VERSION 5.8 ;
BUSBITCHARS "[]" ;
DIVIDERCHAR "/" ;
UNITS
    DATABASE MICRONS 1000 ;
END UNITS

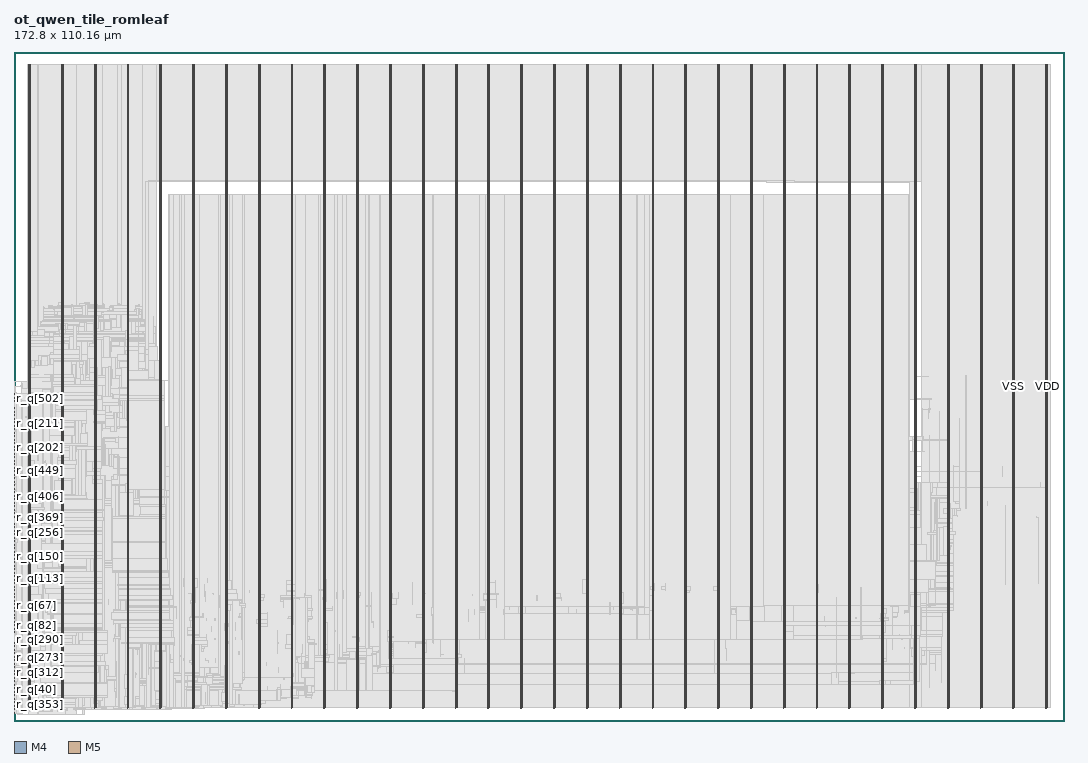
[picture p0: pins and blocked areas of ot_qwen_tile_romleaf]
MACRO ot_qwen_tile_romleaf
  FOREIGN ot_qwen_tile_romleaf 0 0 ;
  CLASS BLOCK ;
  SIZE 172.8 BY 110.16 ;
  PIN ad_d[0]
    DIRECTION INPUT ;
    USE SIGNAL ;
    PORT
      LAYER M4 ;
        RECT  0 20.4 0.084 20.424 ;
    END
  END ad_d[0]
  PIN ad_d[10]
    DIRECTION INPUT ;
    USE SIGNAL ;
    PORT
      LAYER M4 ;
        RECT  0 21.36 0.084 21.384 ;
    END
  END ad_d[10]
  PIN ad_d[11]
    DIRECTION INPUT ;
    USE SIGNAL ;
    PORT
      LAYER M4 ;
        RECT  0 21.456 0.084 21.48 ;
    END
  END ad_d[11]
  PIN ad_d[1]
    DIRECTION INPUT ;
    USE SIGNAL ;
    PORT
      LAYER M4 ;
        RECT  0 20.496 0.084 20.52 ;
    END
  END ad_d[1]
  PIN ad_d[2]
    DIRECTION INPUT ;
    USE SIGNAL ;
    PORT
      LAYER M4 ;
        RECT  0 20.592 0.084 20.616 ;
    END
  END ad_d[2]
  PIN ad_d[3]
    DIRECTION INPUT ;
    USE SIGNAL ;
    PORT
      LAYER M4 ;
        RECT  0 20.688 0.084 20.712 ;
    END
  END ad_d[3]
  PIN ad_d[4]
    DIRECTION INPUT ;
    USE SIGNAL ;
    PORT
      LAYER M4 ;
        RECT  0 20.784 0.084 20.808 ;
    END
  END ad_d[4]
  PIN ad_d[5]
    DIRECTION INPUT ;
    USE SIGNAL ;
    PORT
      LAYER M4 ;
        RECT  0 20.88 0.084 20.904 ;
    END
  END ad_d[5]
  PIN ad_d[6]
    DIRECTION INPUT ;
    USE SIGNAL ;
    PORT
      LAYER M4 ;
        RECT  0 20.976 0.084 21 ;
    END
  END ad_d[6]
  PIN ad_d[7]
    DIRECTION INPUT ;
    USE SIGNAL ;
    PORT
      LAYER M4 ;
        RECT  0 21.072 0.084 21.096 ;
    END
  END ad_d[7]
  PIN ad_d[8]
    DIRECTION INPUT ;
    USE SIGNAL ;
    PORT
      LAYER M4 ;
        RECT  0 21.168 0.084 21.192 ;
    END
  END ad_d[8]
  PIN ad_d[9]
    DIRECTION INPUT ;
    USE SIGNAL ;
    PORT
      LAYER M4 ;
        RECT  0 21.264 0.084 21.288 ;
    END
  END ad_d[9]
  PIN any_d
    DIRECTION INPUT ;
    USE SIGNAL ;
    PORT
      LAYER M4 ;
        RECT  0 21.552 0.084 21.576 ;
    END
  END any_d
  PIN ce_d
    DIRECTION INPUT ;
    USE SIGNAL ;
    PORT
      LAYER M4 ;
        RECT  0 21.648 0.084 21.672 ;
    END
  END ce_d
  PIN clk
    DIRECTION INPUT ;
    USE SIGNAL ;
    PORT
      LAYER M4 ;
        RECT  0 21.744 0.084 21.768 ;
    END
  END clk
  PIN r_q[0]
    DIRECTION OUTPUT ;
    USE SIGNAL ;
    PORT
      LAYER M4 ;
        RECT  0 21.84 0.084 21.864 ;
    END
  END r_q[0]
  PIN r_q[100]
    DIRECTION OUTPUT ;
    USE SIGNAL ;
    PORT
      LAYER M4 ;
        RECT  0 16.08 0.084 16.104 ;
    END
  END r_q[100]
  PIN r_q[101]
    DIRECTION OUTPUT ;
    USE SIGNAL ;
    PORT
      LAYER M4 ;
        RECT  0 16.176 0.084 16.2 ;
    END
  END r_q[101]
  PIN r_q[102]
    DIRECTION OUTPUT ;
    USE SIGNAL ;
    PORT
      LAYER M4 ;
        RECT  0 16.272 0.084 16.296 ;
    END
  END r_q[102]
  PIN r_q[103]
    DIRECTION OUTPUT ;
    USE SIGNAL ;
    PORT
      LAYER M4 ;
        RECT  0 16.368 0.084 16.392 ;
    END
  END r_q[103]
  PIN r_q[104]
    DIRECTION OUTPUT ;
    USE SIGNAL ;
    PORT
      LAYER M4 ;
        RECT  0 16.464 0.084 16.488 ;
    END
  END r_q[104]
  PIN r_q[105]
    DIRECTION OUTPUT ;
    USE SIGNAL ;
    PORT
      LAYER M4 ;
        RECT  0 16.56 0.084 16.584 ;
    END
  END r_q[105]
  PIN r_q[106]
    DIRECTION OUTPUT ;
    USE SIGNAL ;
    PORT
      LAYER M4 ;
        RECT  0 16.656 0.084 16.68 ;
    END
  END r_q[106]
  PIN r_q[107]
    DIRECTION OUTPUT ;
    USE SIGNAL ;
    PORT
      LAYER M4 ;
        RECT  0 16.752 0.084 16.776 ;
    END
  END r_q[107]
  PIN r_q[108]
    DIRECTION OUTPUT ;
    USE SIGNAL ;
    PORT
      LAYER M4 ;
        RECT  0 16.848 0.084 16.872 ;
    END
  END r_q[108]
  PIN r_q[109]
    DIRECTION OUTPUT ;
    USE SIGNAL ;
    PORT
      LAYER M4 ;
        RECT  0 16.944 0.084 16.968 ;
    END
  END r_q[109]
  PIN r_q[10]
    DIRECTION OUTPUT ;
    USE SIGNAL ;
    PORT
      LAYER M4 ;
        RECT  0 22.8 0.084 22.824 ;
    END
  END r_q[10]
  PIN r_q[110]
    DIRECTION OUTPUT ;
    USE SIGNAL ;
    PORT
      LAYER M4 ;
        RECT  0 17.04 0.084 17.064 ;
    END
  END r_q[110]
  PIN r_q[111]
    DIRECTION OUTPUT ;
    USE SIGNAL ;
    PORT
      LAYER M4 ;
        RECT  0 17.136 0.084 17.16 ;
    END
  END r_q[111]
  PIN r_q[112]
    DIRECTION OUTPUT ;
    USE SIGNAL ;
    PORT
      LAYER M4 ;
        RECT  0 17.232 0.084 17.256 ;
    END
  END r_q[112]
  PIN r_q[113]
    DIRECTION OUTPUT ;
    USE SIGNAL ;
    PORT
      LAYER M4 ;
        RECT  0 23.472 0.084 23.496 ;
    END
  END r_q[113]
  PIN r_q[114]
    DIRECTION OUTPUT ;
    USE SIGNAL ;
    PORT
      LAYER M4 ;
        RECT  0 23.568 0.084 23.592 ;
    END
  END r_q[114]
  PIN r_q[115]
    DIRECTION OUTPUT ;
    USE SIGNAL ;
    PORT
      LAYER M4 ;
        RECT  0 23.664 0.084 23.688 ;
    END
  END r_q[115]
  PIN r_q[116]
    DIRECTION OUTPUT ;
    USE SIGNAL ;
    PORT
      LAYER M4 ;
        RECT  0 23.76 0.084 23.784 ;
    END
  END r_q[116]
  PIN r_q[117]
    DIRECTION OUTPUT ;
    USE SIGNAL ;
    PORT
      LAYER M4 ;
        RECT  0 23.856 0.084 23.88 ;
    END
  END r_q[117]
  PIN r_q[118]
    DIRECTION OUTPUT ;
    USE SIGNAL ;
    PORT
      LAYER M4 ;
        RECT  0 23.952 0.084 23.976 ;
    END
  END r_q[118]
  PIN r_q[119]
    DIRECTION OUTPUT ;
    USE SIGNAL ;
    PORT
      LAYER M4 ;
        RECT  0 24.048 0.084 24.072 ;
    END
  END r_q[119]
  PIN r_q[11]
    DIRECTION OUTPUT ;
    USE SIGNAL ;
    PORT
      LAYER M4 ;
        RECT  0 22.896 0.084 22.92 ;
    END
  END r_q[11]
  PIN r_q[120]
    DIRECTION OUTPUT ;
    USE SIGNAL ;
    PORT
      LAYER M4 ;
        RECT  0 24.144 0.084 24.168 ;
    END
  END r_q[120]
  PIN r_q[121]
    DIRECTION OUTPUT ;
    USE SIGNAL ;
    PORT
      LAYER M4 ;
        RECT  0 24.24 0.084 24.264 ;
    END
  END r_q[121]
  PIN r_q[122]
    DIRECTION OUTPUT ;
    USE SIGNAL ;
    PORT
      LAYER M4 ;
        RECT  0 24.336 0.084 24.36 ;
    END
  END r_q[122]
  PIN r_q[123]
    DIRECTION OUTPUT ;
    USE SIGNAL ;
    PORT
      LAYER M4 ;
        RECT  0 24.432 0.084 24.456 ;
    END
  END r_q[123]
  PIN r_q[124]
    DIRECTION OUTPUT ;
    USE SIGNAL ;
    PORT
      LAYER M4 ;
        RECT  0 24.528 0.084 24.552 ;
    END
  END r_q[124]
  PIN r_q[125]
    DIRECTION OUTPUT ;
    USE SIGNAL ;
    PORT
      LAYER M4 ;
        RECT  0 24.624 0.084 24.648 ;
    END
  END r_q[125]
  PIN r_q[126]
    DIRECTION OUTPUT ;
    USE SIGNAL ;
    PORT
      LAYER M4 ;
        RECT  0 24.72 0.084 24.744 ;
    END
  END r_q[126]
  PIN r_q[127]
    DIRECTION OUTPUT ;
    USE SIGNAL ;
    PORT
      LAYER M4 ;
        RECT  0 24.816 0.084 24.84 ;
    END
  END r_q[127]
  PIN r_q[128]
    DIRECTION OUTPUT ;
    USE SIGNAL ;
    PORT
      LAYER M4 ;
        RECT  0 24.912 0.084 24.936 ;
    END
  END r_q[128]
  PIN r_q[129]
    DIRECTION OUTPUT ;
    USE SIGNAL ;
    PORT
      LAYER M4 ;
        RECT  0 25.008 0.084 25.032 ;
    END
  END r_q[129]
  PIN r_q[12]
    DIRECTION OUTPUT ;
    USE SIGNAL ;
    PORT
      LAYER M4 ;
        RECT  0 22.992 0.084 23.016 ;
    END
  END r_q[12]
  PIN r_q[130]
    DIRECTION OUTPUT ;
    USE SIGNAL ;
    PORT
      LAYER M4 ;
        RECT  0 25.104 0.084 25.128 ;
    END
  END r_q[130]
  PIN r_q[131]
    DIRECTION OUTPUT ;
    USE SIGNAL ;
    PORT
      LAYER M4 ;
        RECT  0 25.2 0.084 25.224 ;
    END
  END r_q[131]
  PIN r_q[132]
    DIRECTION OUTPUT ;
    USE SIGNAL ;
    PORT
      LAYER M4 ;
        RECT  0 25.296 0.084 25.32 ;
    END
  END r_q[132]
  PIN r_q[133]
    DIRECTION OUTPUT ;
    USE SIGNAL ;
    PORT
      LAYER M4 ;
        RECT  0 25.392 0.084 25.416 ;
    END
  END r_q[133]
  PIN r_q[134]
    DIRECTION OUTPUT ;
    USE SIGNAL ;
    PORT
      LAYER M4 ;
        RECT  0 25.488 0.084 25.512 ;
    END
  END r_q[134]
  PIN r_q[135]
    DIRECTION OUTPUT ;
    USE SIGNAL ;
    PORT
      LAYER M4 ;
        RECT  0 25.584 0.084 25.608 ;
    END
  END r_q[135]
  PIN r_q[136]
    DIRECTION OUTPUT ;
    USE SIGNAL ;
    PORT
      LAYER M4 ;
        RECT  0 25.68 0.084 25.704 ;
    END
  END r_q[136]
  PIN r_q[137]
    DIRECTION OUTPUT ;
    USE SIGNAL ;
    PORT
      LAYER M4 ;
        RECT  0 25.776 0.084 25.8 ;
    END
  END r_q[137]
  PIN r_q[138]
    DIRECTION OUTPUT ;
    USE SIGNAL ;
    PORT
      LAYER M4 ;
        RECT  0 25.872 0.084 25.896 ;
    END
  END r_q[138]
  PIN r_q[139]
    DIRECTION OUTPUT ;
    USE SIGNAL ;
    PORT
      LAYER M4 ;
        RECT  0 25.968 0.084 25.992 ;
    END
  END r_q[139]
  PIN r_q[13]
    DIRECTION OUTPUT ;
    USE SIGNAL ;
    PORT
      LAYER M4 ;
        RECT  0 23.088 0.084 23.112 ;
    END
  END r_q[13]
  PIN r_q[140]
    DIRECTION OUTPUT ;
    USE SIGNAL ;
    PORT
      LAYER M4 ;
        RECT  0 26.064 0.084 26.088 ;
    END
  END r_q[140]
  PIN r_q[141]
    DIRECTION OUTPUT ;
    USE SIGNAL ;
    PORT
      LAYER M4 ;
        RECT  0 26.16 0.084 26.184 ;
    END
  END r_q[141]
  PIN r_q[142]
    DIRECTION OUTPUT ;
    USE SIGNAL ;
    PORT
      LAYER M4 ;
        RECT  0 26.256 0.084 26.28 ;
    END
  END r_q[142]
  PIN r_q[143]
    DIRECTION OUTPUT ;
    USE SIGNAL ;
    PORT
      LAYER M4 ;
        RECT  0 26.352 0.084 26.376 ;
    END
  END r_q[143]
  PIN r_q[144]
    DIRECTION OUTPUT ;
    USE SIGNAL ;
    PORT
      LAYER M4 ;
        RECT  0 26.448 0.084 26.472 ;
    END
  END r_q[144]
  PIN r_q[145]
    DIRECTION OUTPUT ;
    USE SIGNAL ;
    PORT
      LAYER M4 ;
        RECT  0 26.544 0.084 26.568 ;
    END
  END r_q[145]
  PIN r_q[146]
    DIRECTION OUTPUT ;
    USE SIGNAL ;
    PORT
      LAYER M4 ;
        RECT  0 26.64 0.084 26.664 ;
    END
  END r_q[146]
  PIN r_q[147]
    DIRECTION OUTPUT ;
    USE SIGNAL ;
    PORT
      LAYER M4 ;
        RECT  0 26.736 0.084 26.76 ;
    END
  END r_q[147]
  PIN r_q[148]
    DIRECTION OUTPUT ;
    USE SIGNAL ;
    PORT
      LAYER M4 ;
        RECT  0 26.832 0.084 26.856 ;
    END
  END r_q[148]
  PIN r_q[149]
    DIRECTION OUTPUT ;
    USE SIGNAL ;
    PORT
      LAYER M4 ;
        RECT  0 26.928 0.084 26.952 ;
    END
  END r_q[149]
  PIN r_q[14]
    DIRECTION OUTPUT ;
    USE SIGNAL ;
    PORT
      LAYER M4 ;
        RECT  0 23.184 0.084 23.208 ;
    END
  END r_q[14]
  PIN r_q[150]
    DIRECTION OUTPUT ;
    USE SIGNAL ;
    PORT
      LAYER M4 ;
        RECT  0 27.024 0.084 27.048 ;
    END
  END r_q[150]
  PIN r_q[151]
    DIRECTION OUTPUT ;
    USE SIGNAL ;
    PORT
      LAYER M4 ;
        RECT  0 27.12 0.084 27.144 ;
    END
  END r_q[151]
  PIN r_q[152]
    DIRECTION OUTPUT ;
    USE SIGNAL ;
    PORT
      LAYER M4 ;
        RECT  0 27.216 0.084 27.24 ;
    END
  END r_q[152]
  PIN r_q[153]
    DIRECTION OUTPUT ;
    USE SIGNAL ;
    PORT
      LAYER M4 ;
        RECT  0 27.312 0.084 27.336 ;
    END
  END r_q[153]
  PIN r_q[154]
    DIRECTION OUTPUT ;
    USE SIGNAL ;
    PORT
      LAYER M4 ;
        RECT  0 27.408 0.084 27.432 ;
    END
  END r_q[154]
  PIN r_q[155]
    DIRECTION OUTPUT ;
    USE SIGNAL ;
    PORT
      LAYER M4 ;
        RECT  0 27.504 0.084 27.528 ;
    END
  END r_q[155]
  PIN r_q[156]
    DIRECTION OUTPUT ;
    USE SIGNAL ;
    PORT
      LAYER M4 ;
        RECT  0 27.6 0.084 27.624 ;
    END
  END r_q[156]
  PIN r_q[157]
    DIRECTION OUTPUT ;
    USE SIGNAL ;
    PORT
      LAYER M4 ;
        RECT  0 27.696 0.084 27.72 ;
    END
  END r_q[157]
  PIN r_q[158]
    DIRECTION OUTPUT ;
    USE SIGNAL ;
    PORT
      LAYER M4 ;
        RECT  0 27.792 0.084 27.816 ;
    END
  END r_q[158]
  PIN r_q[159]
    DIRECTION OUTPUT ;
    USE SIGNAL ;
    PORT
      LAYER M4 ;
        RECT  0 27.888 0.084 27.912 ;
    END
  END r_q[159]
  PIN r_q[15]
    DIRECTION OUTPUT ;
    USE SIGNAL ;
    PORT
      LAYER M4 ;
        RECT  0 23.28 0.084 23.304 ;
    END
  END r_q[15]
  PIN r_q[160]
    DIRECTION OUTPUT ;
    USE SIGNAL ;
    PORT
      LAYER M4 ;
        RECT  0 27.984 0.084 28.008 ;
    END
  END r_q[160]
  PIN r_q[161]
    DIRECTION OUTPUT ;
    USE SIGNAL ;
    PORT
      LAYER M4 ;
        RECT  0 28.08 0.084 28.104 ;
    END
  END r_q[161]
  PIN r_q[162]
    DIRECTION OUTPUT ;
    USE SIGNAL ;
    PORT
      LAYER M4 ;
        RECT  0 28.176 0.084 28.2 ;
    END
  END r_q[162]
  PIN r_q[163]
    DIRECTION OUTPUT ;
    USE SIGNAL ;
    PORT
      LAYER M4 ;
        RECT  0 28.272 0.084 28.296 ;
    END
  END r_q[163]
  PIN r_q[164]
    DIRECTION OUTPUT ;
    USE SIGNAL ;
    PORT
      LAYER M4 ;
        RECT  0 28.368 0.084 28.392 ;
    END
  END r_q[164]
  PIN r_q[165]
    DIRECTION OUTPUT ;
    USE SIGNAL ;
    PORT
      LAYER M4 ;
        RECT  0 28.464 0.084 28.488 ;
    END
  END r_q[165]
  PIN r_q[166]
    DIRECTION OUTPUT ;
    USE SIGNAL ;
    PORT
      LAYER M4 ;
        RECT  0 28.56 0.084 28.584 ;
    END
  END r_q[166]
  PIN r_q[167]
    DIRECTION OUTPUT ;
    USE SIGNAL ;
    PORT
      LAYER M4 ;
        RECT  0 28.656 0.084 28.68 ;
    END
  END r_q[167]
  PIN r_q[168]
    DIRECTION OUTPUT ;
    USE SIGNAL ;
    PORT
      LAYER M4 ;
        RECT  0 28.752 0.084 28.776 ;
    END
  END r_q[168]
  PIN r_q[169]
    DIRECTION OUTPUT ;
    USE SIGNAL ;
    PORT
      LAYER M4 ;
        RECT  0 28.848 0.084 28.872 ;
    END
  END r_q[169]
  PIN r_q[16]
    DIRECTION OUTPUT ;
    USE SIGNAL ;
    PORT
      LAYER M4 ;
        RECT  0 23.376 0.084 23.4 ;
    END
  END r_q[16]
  PIN r_q[170]
    DIRECTION OUTPUT ;
    USE SIGNAL ;
    PORT
      LAYER M4 ;
        RECT  0 28.944 0.084 28.968 ;
    END
  END r_q[170]
  PIN r_q[171]
    DIRECTION OUTPUT ;
    USE SIGNAL ;
    PORT
      LAYER M4 ;
        RECT  0 29.04 0.084 29.064 ;
    END
  END r_q[171]
  PIN r_q[172]
    DIRECTION OUTPUT ;
    USE SIGNAL ;
    PORT
      LAYER M4 ;
        RECT  0 29.136 0.084 29.16 ;
    END
  END r_q[172]
  PIN r_q[173]
    DIRECTION OUTPUT ;
    USE SIGNAL ;
    PORT
      LAYER M4 ;
        RECT  0 29.232 0.084 29.256 ;
    END
  END r_q[173]
  PIN r_q[174]
    DIRECTION OUTPUT ;
    USE SIGNAL ;
    PORT
      LAYER M4 ;
        RECT  0 29.328 0.084 29.352 ;
    END
  END r_q[174]
  PIN r_q[175]
    DIRECTION OUTPUT ;
    USE SIGNAL ;
    PORT
      LAYER M4 ;
        RECT  0 29.424 0.084 29.448 ;
    END
  END r_q[175]
  PIN r_q[176]
    DIRECTION OUTPUT ;
    USE SIGNAL ;
    PORT
      LAYER M4 ;
        RECT  0 29.52 0.084 29.544 ;
    END
  END r_q[176]
  PIN r_q[177]
    DIRECTION OUTPUT ;
    USE SIGNAL ;
    PORT
      LAYER M4 ;
        RECT  0 42.672 0.084 42.696 ;
    END
  END r_q[177]
  PIN r_q[178]
    DIRECTION OUTPUT ;
    USE SIGNAL ;
    PORT
      LAYER M4 ;
        RECT  0 42.768 0.084 42.792 ;
    END
  END r_q[178]
  PIN r_q[179]
    DIRECTION OUTPUT ;
    USE SIGNAL ;
    PORT
      LAYER M4 ;
        RECT  0 42.864 0.084 42.888 ;
    END
  END r_q[179]
  PIN r_q[17]
    DIRECTION OUTPUT ;
    USE SIGNAL ;
    PORT
      LAYER M4 ;
        RECT  0 4.272 0.084 4.296 ;
    END
  END r_q[17]
  PIN r_q[180]
    DIRECTION OUTPUT ;
    USE SIGNAL ;
    PORT
      LAYER M4 ;
        RECT  0 42.96 0.084 42.984 ;
    END
  END r_q[180]
  PIN r_q[181]
    DIRECTION OUTPUT ;
    USE SIGNAL ;
    PORT
      LAYER M4 ;
        RECT  0 43.056 0.084 43.08 ;
    END
  END r_q[181]
  PIN r_q[182]
    DIRECTION OUTPUT ;
    USE SIGNAL ;
    PORT
      LAYER M4 ;
        RECT  0 43.152 0.084 43.176 ;
    END
  END r_q[182]
  PIN r_q[183]
    DIRECTION OUTPUT ;
    USE SIGNAL ;
    PORT
      LAYER M4 ;
        RECT  0 43.248 0.084 43.272 ;
    END
  END r_q[183]
  PIN r_q[184]
    DIRECTION OUTPUT ;
    USE SIGNAL ;
    PORT
      LAYER M4 ;
        RECT  0 43.344 0.084 43.368 ;
    END
  END r_q[184]
  PIN r_q[185]
    DIRECTION OUTPUT ;
    USE SIGNAL ;
    PORT
      LAYER M4 ;
        RECT  0 43.44 0.084 43.464 ;
    END
  END r_q[185]
  PIN r_q[186]
    DIRECTION OUTPUT ;
    USE SIGNAL ;
    PORT
      LAYER M4 ;
        RECT  0 43.536 0.084 43.56 ;
    END
  END r_q[186]
  PIN r_q[187]
    DIRECTION OUTPUT ;
    USE SIGNAL ;
    PORT
      LAYER M4 ;
        RECT  0 43.632 0.084 43.656 ;
    END
  END r_q[187]
  PIN r_q[188]
    DIRECTION OUTPUT ;
    USE SIGNAL ;
    PORT
      LAYER M4 ;
        RECT  0 43.728 0.084 43.752 ;
    END
  END r_q[188]
  PIN r_q[189]
    DIRECTION OUTPUT ;
    USE SIGNAL ;
    PORT
      LAYER M4 ;
        RECT  0 43.824 0.084 43.848 ;
    END
  END r_q[189]
  PIN r_q[18]
    DIRECTION OUTPUT ;
    USE SIGNAL ;
    PORT
      LAYER M4 ;
        RECT  0 4.368 0.084 4.392 ;
    END
  END r_q[18]
  PIN r_q[190]
    DIRECTION OUTPUT ;
    USE SIGNAL ;
    PORT
      LAYER M4 ;
        RECT  0 43.92 0.084 43.944 ;
    END
  END r_q[190]
  PIN r_q[191]
    DIRECTION OUTPUT ;
    USE SIGNAL ;
    PORT
      LAYER M4 ;
        RECT  0 44.016 0.084 44.04 ;
    END
  END r_q[191]
  PIN r_q[192]
    DIRECTION OUTPUT ;
    USE SIGNAL ;
    PORT
      LAYER M4 ;
        RECT  0 44.112 0.084 44.136 ;
    END
  END r_q[192]
  PIN r_q[193]
    DIRECTION OUTPUT ;
    USE SIGNAL ;
    PORT
      LAYER M4 ;
        RECT  0 44.208 0.084 44.232 ;
    END
  END r_q[193]
  PIN r_q[194]
    DIRECTION OUTPUT ;
    USE SIGNAL ;
    PORT
      LAYER M4 ;
        RECT  0 44.304 0.084 44.328 ;
    END
  END r_q[194]
  PIN r_q[195]
    DIRECTION OUTPUT ;
    USE SIGNAL ;
    PORT
      LAYER M4 ;
        RECT  0 44.4 0.084 44.424 ;
    END
  END r_q[195]
  PIN r_q[196]
    DIRECTION OUTPUT ;
    USE SIGNAL ;
    PORT
      LAYER M4 ;
        RECT  0 44.496 0.084 44.52 ;
    END
  END r_q[196]
  PIN r_q[197]
    DIRECTION OUTPUT ;
    USE SIGNAL ;
    PORT
      LAYER M4 ;
        RECT  0 44.592 0.084 44.616 ;
    END
  END r_q[197]
  PIN r_q[198]
    DIRECTION OUTPUT ;
    USE SIGNAL ;
    PORT
      LAYER M4 ;
        RECT  0 44.688 0.084 44.712 ;
    END
  END r_q[198]
  PIN r_q[199]
    DIRECTION OUTPUT ;
    USE SIGNAL ;
    PORT
      LAYER M4 ;
        RECT  0 44.784 0.084 44.808 ;
    END
  END r_q[199]
  PIN r_q[19]
    DIRECTION OUTPUT ;
    USE SIGNAL ;
    PORT
      LAYER M4 ;
        RECT  0 4.464 0.084 4.488 ;
    END
  END r_q[19]
  PIN r_q[1]
    DIRECTION OUTPUT ;
    USE SIGNAL ;
    PORT
      LAYER M4 ;
        RECT  0 21.936 0.084 21.96 ;
    END
  END r_q[1]
  PIN r_q[200]
    DIRECTION OUTPUT ;
    USE SIGNAL ;
    PORT
      LAYER M4 ;
        RECT  0 44.88 0.084 44.904 ;
    END
  END r_q[200]
  PIN r_q[201]
    DIRECTION OUTPUT ;
    USE SIGNAL ;
    PORT
      LAYER M4 ;
        RECT  0 44.976 0.084 45 ;
    END
  END r_q[201]
  PIN r_q[202]
    DIRECTION OUTPUT ;
    USE SIGNAL ;
    PORT
      LAYER M4 ;
        RECT  0 45.072 0.084 45.096 ;
    END
  END r_q[202]
  PIN r_q[203]
    DIRECTION OUTPUT ;
    USE SIGNAL ;
    PORT
      LAYER M4 ;
        RECT  0 45.168 0.084 45.192 ;
    END
  END r_q[203]
  PIN r_q[204]
    DIRECTION OUTPUT ;
    USE SIGNAL ;
    PORT
      LAYER M4 ;
        RECT  0 45.264 0.084 45.288 ;
    END
  END r_q[204]
  PIN r_q[205]
    DIRECTION OUTPUT ;
    USE SIGNAL ;
    PORT
      LAYER M4 ;
        RECT  0 45.36 0.084 45.384 ;
    END
  END r_q[205]
  PIN r_q[206]
    DIRECTION OUTPUT ;
    USE SIGNAL ;
    PORT
      LAYER M4 ;
        RECT  0 45.456 0.084 45.48 ;
    END
  END r_q[206]
  PIN r_q[207]
    DIRECTION OUTPUT ;
    USE SIGNAL ;
    PORT
      LAYER M4 ;
        RECT  0 45.552 0.084 45.576 ;
    END
  END r_q[207]
  PIN r_q[208]
    DIRECTION OUTPUT ;
    USE SIGNAL ;
    PORT
      LAYER M4 ;
        RECT  0 45.648 0.084 45.672 ;
    END
  END r_q[208]
  PIN r_q[209]
    DIRECTION OUTPUT ;
    USE SIGNAL ;
    PORT
      LAYER M4 ;
        RECT  0 48.816 0.084 48.84 ;
    END
  END r_q[209]
  PIN r_q[20]
    DIRECTION OUTPUT ;
    USE SIGNAL ;
    PORT
      LAYER M4 ;
        RECT  0 4.56 0.084 4.584 ;
    END
  END r_q[20]
  PIN r_q[210]
    DIRECTION OUTPUT ;
    USE SIGNAL ;
    PORT
      LAYER M4 ;
        RECT  0 48.912 0.084 48.936 ;
    END
  END r_q[210]
  PIN r_q[211]
    DIRECTION OUTPUT ;
    USE SIGNAL ;
    PORT
      LAYER M4 ;
        RECT  0 49.008 0.084 49.032 ;
    END
  END r_q[211]
  PIN r_q[212]
    DIRECTION OUTPUT ;
    USE SIGNAL ;
    PORT
      LAYER M4 ;
        RECT  0 49.104 0.084 49.128 ;
    END
  END r_q[212]
  PIN r_q[213]
    DIRECTION OUTPUT ;
    USE SIGNAL ;
    PORT
      LAYER M4 ;
        RECT  0 49.2 0.084 49.224 ;
    END
  END r_q[213]
  PIN r_q[214]
    DIRECTION OUTPUT ;
    USE SIGNAL ;
    PORT
      LAYER M4 ;
        RECT  0 49.296 0.084 49.32 ;
    END
  END r_q[214]
  PIN r_q[215]
    DIRECTION OUTPUT ;
    USE SIGNAL ;
    PORT
      LAYER M4 ;
        RECT  0 49.392 0.084 49.416 ;
    END
  END r_q[215]
  PIN r_q[216]
    DIRECTION OUTPUT ;
    USE SIGNAL ;
    PORT
      LAYER M4 ;
        RECT  0 49.488 0.084 49.512 ;
    END
  END r_q[216]
  PIN r_q[217]
    DIRECTION OUTPUT ;
    USE SIGNAL ;
    PORT
      LAYER M4 ;
        RECT  0 49.584 0.084 49.608 ;
    END
  END r_q[217]
  PIN r_q[218]
    DIRECTION OUTPUT ;
    USE SIGNAL ;
    PORT
      LAYER M4 ;
        RECT  0 49.68 0.084 49.704 ;
    END
  END r_q[218]
  PIN r_q[219]
    DIRECTION OUTPUT ;
    USE SIGNAL ;
    PORT
      LAYER M4 ;
        RECT  0 49.776 0.084 49.8 ;
    END
  END r_q[219]
  PIN r_q[21]
    DIRECTION OUTPUT ;
    USE SIGNAL ;
    PORT
      LAYER M4 ;
        RECT  0 4.656 0.084 4.68 ;
    END
  END r_q[21]
  PIN r_q[220]
    DIRECTION OUTPUT ;
    USE SIGNAL ;
    PORT
      LAYER M4 ;
        RECT  0 49.872 0.084 49.896 ;
    END
  END r_q[220]
  PIN r_q[221]
    DIRECTION OUTPUT ;
    USE SIGNAL ;
    PORT
      LAYER M4 ;
        RECT  0 49.968 0.084 49.992 ;
    END
  END r_q[221]
  PIN r_q[222]
    DIRECTION OUTPUT ;
    USE SIGNAL ;
    PORT
      LAYER M4 ;
        RECT  0 50.064 0.084 50.088 ;
    END
  END r_q[222]
  PIN r_q[223]
    DIRECTION OUTPUT ;
    USE SIGNAL ;
    PORT
      LAYER M4 ;
        RECT  0 50.16 0.084 50.184 ;
    END
  END r_q[223]
  PIN r_q[224]
    DIRECTION OUTPUT ;
    USE SIGNAL ;
    PORT
      LAYER M4 ;
        RECT  0 50.256 0.084 50.28 ;
    END
  END r_q[224]
  PIN r_q[225]
    DIRECTION OUTPUT ;
    USE SIGNAL ;
    PORT
      LAYER M4 ;
        RECT  0 50.352 0.084 50.376 ;
    END
  END r_q[225]
  PIN r_q[226]
    DIRECTION OUTPUT ;
    USE SIGNAL ;
    PORT
      LAYER M4 ;
        RECT  0 50.448 0.084 50.472 ;
    END
  END r_q[226]
  PIN r_q[227]
    DIRECTION OUTPUT ;
    USE SIGNAL ;
    PORT
      LAYER M4 ;
        RECT  0 50.544 0.084 50.568 ;
    END
  END r_q[227]
  PIN r_q[228]
    DIRECTION OUTPUT ;
    USE SIGNAL ;
    PORT
      LAYER M4 ;
        RECT  0 50.64 0.084 50.664 ;
    END
  END r_q[228]
  PIN r_q[229]
    DIRECTION OUTPUT ;
    USE SIGNAL ;
    PORT
      LAYER M4 ;
        RECT  0 50.736 0.084 50.76 ;
    END
  END r_q[229]
  PIN r_q[22]
    DIRECTION OUTPUT ;
    USE SIGNAL ;
    PORT
      LAYER M4 ;
        RECT  0 4.752 0.084 4.776 ;
    END
  END r_q[22]
  PIN r_q[230]
    DIRECTION OUTPUT ;
    USE SIGNAL ;
    PORT
      LAYER M4 ;
        RECT  0 50.832 0.084 50.856 ;
    END
  END r_q[230]
  PIN r_q[231]
    DIRECTION OUTPUT ;
    USE SIGNAL ;
    PORT
      LAYER M4 ;
        RECT  0 50.928 0.084 50.952 ;
    END
  END r_q[231]
  PIN r_q[232]
    DIRECTION OUTPUT ;
    USE SIGNAL ;
    PORT
      LAYER M4 ;
        RECT  0 51.024 0.084 51.048 ;
    END
  END r_q[232]
  PIN r_q[233]
    DIRECTION OUTPUT ;
    USE SIGNAL ;
    PORT
      LAYER M4 ;
        RECT  0 51.12 0.084 51.144 ;
    END
  END r_q[233]
  PIN r_q[234]
    DIRECTION OUTPUT ;
    USE SIGNAL ;
    PORT
      LAYER M4 ;
        RECT  0 51.216 0.084 51.24 ;
    END
  END r_q[234]
  PIN r_q[235]
    DIRECTION OUTPUT ;
    USE SIGNAL ;
    PORT
      LAYER M4 ;
        RECT  0 51.312 0.084 51.336 ;
    END
  END r_q[235]
  PIN r_q[236]
    DIRECTION OUTPUT ;
    USE SIGNAL ;
    PORT
      LAYER M4 ;
        RECT  0 51.408 0.084 51.432 ;
    END
  END r_q[236]
  PIN r_q[237]
    DIRECTION OUTPUT ;
    USE SIGNAL ;
    PORT
      LAYER M4 ;
        RECT  0 51.504 0.084 51.528 ;
    END
  END r_q[237]
  PIN r_q[238]
    DIRECTION OUTPUT ;
    USE SIGNAL ;
    PORT
      LAYER M4 ;
        RECT  0 51.6 0.084 51.624 ;
    END
  END r_q[238]
  PIN r_q[239]
    DIRECTION OUTPUT ;
    USE SIGNAL ;
    PORT
      LAYER M4 ;
        RECT  0 51.696 0.084 51.72 ;
    END
  END r_q[239]
  PIN r_q[23]
    DIRECTION OUTPUT ;
    USE SIGNAL ;
    PORT
      LAYER M4 ;
        RECT  0 4.848 0.084 4.872 ;
    END
  END r_q[23]
  PIN r_q[240]
    DIRECTION OUTPUT ;
    USE SIGNAL ;
    PORT
      LAYER M4 ;
        RECT  0 51.792 0.084 51.816 ;
    END
  END r_q[240]
  PIN r_q[241]
    DIRECTION OUTPUT ;
    USE SIGNAL ;
    PORT
      LAYER M4 ;
        RECT  0 29.616 0.084 29.64 ;
    END
  END r_q[241]
  PIN r_q[242]
    DIRECTION OUTPUT ;
    USE SIGNAL ;
    PORT
      LAYER M4 ;
        RECT  0 29.712 0.084 29.736 ;
    END
  END r_q[242]
  PIN r_q[243]
    DIRECTION OUTPUT ;
    USE SIGNAL ;
    PORT
      LAYER M4 ;
        RECT  0 29.808 0.084 29.832 ;
    END
  END r_q[243]
  PIN r_q[244]
    DIRECTION OUTPUT ;
    USE SIGNAL ;
    PORT
      LAYER M4 ;
        RECT  0 29.904 0.084 29.928 ;
    END
  END r_q[244]
  PIN r_q[245]
    DIRECTION OUTPUT ;
    USE SIGNAL ;
    PORT
      LAYER M4 ;
        RECT  0 30 0.084 30.024 ;
    END
  END r_q[245]
  PIN r_q[246]
    DIRECTION OUTPUT ;
    USE SIGNAL ;
    PORT
      LAYER M4 ;
        RECT  0 30.096 0.084 30.12 ;
    END
  END r_q[246]
  PIN r_q[247]
    DIRECTION OUTPUT ;
    USE SIGNAL ;
    PORT
      LAYER M4 ;
        RECT  0 30.192 0.084 30.216 ;
    END
  END r_q[247]
  PIN r_q[248]
    DIRECTION OUTPUT ;
    USE SIGNAL ;
    PORT
      LAYER M4 ;
        RECT  0 30.288 0.084 30.312 ;
    END
  END r_q[248]
  PIN r_q[249]
    DIRECTION OUTPUT ;
    USE SIGNAL ;
    PORT
      LAYER M4 ;
        RECT  0 30.384 0.084 30.408 ;
    END
  END r_q[249]
  PIN r_q[24]
    DIRECTION OUTPUT ;
    USE SIGNAL ;
    PORT
      LAYER M4 ;
        RECT  0 4.944 0.084 4.968 ;
    END
  END r_q[24]
  PIN r_q[250]
    DIRECTION OUTPUT ;
    USE SIGNAL ;
    PORT
      LAYER M4 ;
        RECT  0 30.48 0.084 30.504 ;
    END
  END r_q[250]
  PIN r_q[251]
    DIRECTION OUTPUT ;
    USE SIGNAL ;
    PORT
      LAYER M4 ;
        RECT  0 30.576 0.084 30.6 ;
    END
  END r_q[251]
  PIN r_q[252]
    DIRECTION OUTPUT ;
    USE SIGNAL ;
    PORT
      LAYER M4 ;
        RECT  0 30.672 0.084 30.696 ;
    END
  END r_q[252]
  PIN r_q[253]
    DIRECTION OUTPUT ;
    USE SIGNAL ;
    PORT
      LAYER M4 ;
        RECT  0 30.768 0.084 30.792 ;
    END
  END r_q[253]
  PIN r_q[254]
    DIRECTION OUTPUT ;
    USE SIGNAL ;
    PORT
      LAYER M4 ;
        RECT  0 30.864 0.084 30.888 ;
    END
  END r_q[254]
  PIN r_q[255]
    DIRECTION OUTPUT ;
    USE SIGNAL ;
    PORT
      LAYER M4 ;
        RECT  0 30.96 0.084 30.984 ;
    END
  END r_q[255]
  PIN r_q[256]
    DIRECTION OUTPUT ;
    USE SIGNAL ;
    PORT
      LAYER M4 ;
        RECT  0 31.056 0.084 31.08 ;
    END
  END r_q[256]
  PIN r_q[257]
    DIRECTION OUTPUT ;
    USE SIGNAL ;
    PORT
      LAYER M4 ;
        RECT  0 31.152 0.084 31.176 ;
    END
  END r_q[257]
  PIN r_q[258]
    DIRECTION OUTPUT ;
    USE SIGNAL ;
    PORT
      LAYER M4 ;
        RECT  0 31.248 0.084 31.272 ;
    END
  END r_q[258]
  PIN r_q[259]
    DIRECTION OUTPUT ;
    USE SIGNAL ;
    PORT
      LAYER M4 ;
        RECT  0 31.344 0.084 31.368 ;
    END
  END r_q[259]
  PIN r_q[25]
    DIRECTION OUTPUT ;
    USE SIGNAL ;
    PORT
      LAYER M4 ;
        RECT  0 5.04 0.084 5.064 ;
    END
  END r_q[25]
  PIN r_q[260]
    DIRECTION OUTPUT ;
    USE SIGNAL ;
    PORT
      LAYER M4 ;
        RECT  0 31.44 0.084 31.464 ;
    END
  END r_q[260]
  PIN r_q[261]
    DIRECTION OUTPUT ;
    USE SIGNAL ;
    PORT
      LAYER M4 ;
        RECT  0 31.536 0.084 31.56 ;
    END
  END r_q[261]
  PIN r_q[262]
    DIRECTION OUTPUT ;
    USE SIGNAL ;
    PORT
      LAYER M4 ;
        RECT  0 31.632 0.084 31.656 ;
    END
  END r_q[262]
  PIN r_q[263]
    DIRECTION OUTPUT ;
    USE SIGNAL ;
    PORT
      LAYER M4 ;
        RECT  0 31.728 0.084 31.752 ;
    END
  END r_q[263]
  PIN r_q[264]
    DIRECTION OUTPUT ;
    USE SIGNAL ;
    PORT
      LAYER M4 ;
        RECT  0 31.824 0.084 31.848 ;
    END
  END r_q[264]
  PIN r_q[265]
    DIRECTION OUTPUT ;
    USE SIGNAL ;
    PORT
      LAYER M4 ;
        RECT  0 31.92 0.084 31.944 ;
    END
  END r_q[265]
  PIN r_q[266]
    DIRECTION OUTPUT ;
    USE SIGNAL ;
    PORT
      LAYER M4 ;
        RECT  0 32.016 0.084 32.04 ;
    END
  END r_q[266]
  PIN r_q[267]
    DIRECTION OUTPUT ;
    USE SIGNAL ;
    PORT
      LAYER M4 ;
        RECT  0 32.112 0.084 32.136 ;
    END
  END r_q[267]
  PIN r_q[268]
    DIRECTION OUTPUT ;
    USE SIGNAL ;
    PORT
      LAYER M4 ;
        RECT  0 32.208 0.084 32.232 ;
    END
  END r_q[268]
  PIN r_q[269]
    DIRECTION OUTPUT ;
    USE SIGNAL ;
    PORT
      LAYER M4 ;
        RECT  0 32.304 0.084 32.328 ;
    END
  END r_q[269]
  PIN r_q[26]
    DIRECTION OUTPUT ;
    USE SIGNAL ;
    PORT
      LAYER M4 ;
        RECT  0 5.136 0.084 5.16 ;
    END
  END r_q[26]
  PIN r_q[270]
    DIRECTION OUTPUT ;
    USE SIGNAL ;
    PORT
      LAYER M4 ;
        RECT  0 32.4 0.084 32.424 ;
    END
  END r_q[270]
  PIN r_q[271]
    DIRECTION OUTPUT ;
    USE SIGNAL ;
    PORT
      LAYER M4 ;
        RECT  0 32.496 0.084 32.52 ;
    END
  END r_q[271]
  PIN r_q[272]
    DIRECTION OUTPUT ;
    USE SIGNAL ;
    PORT
      LAYER M4 ;
        RECT  0 32.592 0.084 32.616 ;
    END
  END r_q[272]
  PIN r_q[273]
    DIRECTION OUTPUT ;
    USE SIGNAL ;
    PORT
      LAYER M4 ;
        RECT  0 10.416 0.084 10.44 ;
    END
  END r_q[273]
  PIN r_q[274]
    DIRECTION OUTPUT ;
    USE SIGNAL ;
    PORT
      LAYER M4 ;
        RECT  0 10.512 0.084 10.536 ;
    END
  END r_q[274]
  PIN r_q[275]
    DIRECTION OUTPUT ;
    USE SIGNAL ;
    PORT
      LAYER M4 ;
        RECT  0 10.608 0.084 10.632 ;
    END
  END r_q[275]
  PIN r_q[276]
    DIRECTION OUTPUT ;
    USE SIGNAL ;
    PORT
      LAYER M4 ;
        RECT  0 10.704 0.084 10.728 ;
    END
  END r_q[276]
  PIN r_q[277]
    DIRECTION OUTPUT ;
    USE SIGNAL ;
    PORT
      LAYER M4 ;
        RECT  0 10.8 0.084 10.824 ;
    END
  END r_q[277]
  PIN r_q[278]
    DIRECTION OUTPUT ;
    USE SIGNAL ;
    PORT
      LAYER M4 ;
        RECT  0 10.896 0.084 10.92 ;
    END
  END r_q[278]
  PIN r_q[279]
    DIRECTION OUTPUT ;
    USE SIGNAL ;
    PORT
      LAYER M4 ;
        RECT  0 10.992 0.084 11.016 ;
    END
  END r_q[279]
  PIN r_q[27]
    DIRECTION OUTPUT ;
    USE SIGNAL ;
    PORT
      LAYER M4 ;
        RECT  0 5.232 0.084 5.256 ;
    END
  END r_q[27]
  PIN r_q[280]
    DIRECTION OUTPUT ;
    USE SIGNAL ;
    PORT
      LAYER M4 ;
        RECT  0 11.088 0.084 11.112 ;
    END
  END r_q[280]
  PIN r_q[281]
    DIRECTION OUTPUT ;
    USE SIGNAL ;
    PORT
      LAYER M4 ;
        RECT  0 11.184 0.084 11.208 ;
    END
  END r_q[281]
  PIN r_q[282]
    DIRECTION OUTPUT ;
    USE SIGNAL ;
    PORT
      LAYER M4 ;
        RECT  0 11.28 0.084 11.304 ;
    END
  END r_q[282]
  PIN r_q[283]
    DIRECTION OUTPUT ;
    USE SIGNAL ;
    PORT
      LAYER M4 ;
        RECT  0 11.376 0.084 11.4 ;
    END
  END r_q[283]
  PIN r_q[284]
    DIRECTION OUTPUT ;
    USE SIGNAL ;
    PORT
      LAYER M4 ;
        RECT  0 11.472 0.084 11.496 ;
    END
  END r_q[284]
  PIN r_q[285]
    DIRECTION OUTPUT ;
    USE SIGNAL ;
    PORT
      LAYER M4 ;
        RECT  0 11.568 0.084 11.592 ;
    END
  END r_q[285]
  PIN r_q[286]
    DIRECTION OUTPUT ;
    USE SIGNAL ;
    PORT
      LAYER M4 ;
        RECT  0 11.664 0.084 11.688 ;
    END
  END r_q[286]
  PIN r_q[287]
    DIRECTION OUTPUT ;
    USE SIGNAL ;
    PORT
      LAYER M4 ;
        RECT  0 11.76 0.084 11.784 ;
    END
  END r_q[287]
  PIN r_q[288]
    DIRECTION OUTPUT ;
    USE SIGNAL ;
    PORT
      LAYER M4 ;
        RECT  0 11.856 0.084 11.88 ;
    END
  END r_q[288]
  PIN r_q[289]
    DIRECTION OUTPUT ;
    USE SIGNAL ;
    PORT
      LAYER M4 ;
        RECT  0 11.952 0.084 11.976 ;
    END
  END r_q[289]
  PIN r_q[28]
    DIRECTION OUTPUT ;
    USE SIGNAL ;
    PORT
      LAYER M4 ;
        RECT  0 5.328 0.084 5.352 ;
    END
  END r_q[28]
  PIN r_q[290]
    DIRECTION OUTPUT ;
    USE SIGNAL ;
    PORT
      LAYER M4 ;
        RECT  0 12.048 0.084 12.072 ;
    END
  END r_q[290]
  PIN r_q[291]
    DIRECTION OUTPUT ;
    USE SIGNAL ;
    PORT
      LAYER M4 ;
        RECT  0 12.144 0.084 12.168 ;
    END
  END r_q[291]
  PIN r_q[292]
    DIRECTION OUTPUT ;
    USE SIGNAL ;
    PORT
      LAYER M4 ;
        RECT  0 12.24 0.084 12.264 ;
    END
  END r_q[292]
  PIN r_q[293]
    DIRECTION OUTPUT ;
    USE SIGNAL ;
    PORT
      LAYER M4 ;
        RECT  0 12.336 0.084 12.36 ;
    END
  END r_q[293]
  PIN r_q[294]
    DIRECTION OUTPUT ;
    USE SIGNAL ;
    PORT
      LAYER M4 ;
        RECT  0 12.432 0.084 12.456 ;
    END
  END r_q[294]
  PIN r_q[295]
    DIRECTION OUTPUT ;
    USE SIGNAL ;
    PORT
      LAYER M4 ;
        RECT  0 12.528 0.084 12.552 ;
    END
  END r_q[295]
  PIN r_q[296]
    DIRECTION OUTPUT ;
    USE SIGNAL ;
    PORT
      LAYER M4 ;
        RECT  0 12.624 0.084 12.648 ;
    END
  END r_q[296]
  PIN r_q[297]
    DIRECTION OUTPUT ;
    USE SIGNAL ;
    PORT
      LAYER M4 ;
        RECT  0 12.72 0.084 12.744 ;
    END
  END r_q[297]
  PIN r_q[298]
    DIRECTION OUTPUT ;
    USE SIGNAL ;
    PORT
      LAYER M4 ;
        RECT  0 12.816 0.084 12.84 ;
    END
  END r_q[298]
  PIN r_q[299]
    DIRECTION OUTPUT ;
    USE SIGNAL ;
    PORT
      LAYER M4 ;
        RECT  0 12.912 0.084 12.936 ;
    END
  END r_q[299]
  PIN r_q[29]
    DIRECTION OUTPUT ;
    USE SIGNAL ;
    PORT
      LAYER M4 ;
        RECT  0 5.424 0.084 5.448 ;
    END
  END r_q[29]
  PIN r_q[2]
    DIRECTION OUTPUT ;
    USE SIGNAL ;
    PORT
      LAYER M4 ;
        RECT  0 22.032 0.084 22.056 ;
    END
  END r_q[2]
  PIN r_q[300]
    DIRECTION OUTPUT ;
    USE SIGNAL ;
    PORT
      LAYER M4 ;
        RECT  0 13.008 0.084 13.032 ;
    END
  END r_q[300]
  PIN r_q[301]
    DIRECTION OUTPUT ;
    USE SIGNAL ;
    PORT
      LAYER M4 ;
        RECT  0 13.104 0.084 13.128 ;
    END
  END r_q[301]
  PIN r_q[302]
    DIRECTION OUTPUT ;
    USE SIGNAL ;
    PORT
      LAYER M4 ;
        RECT  0 13.2 0.084 13.224 ;
    END
  END r_q[302]
  PIN r_q[303]
    DIRECTION OUTPUT ;
    USE SIGNAL ;
    PORT
      LAYER M4 ;
        RECT  0 13.296 0.084 13.32 ;
    END
  END r_q[303]
  PIN r_q[304]
    DIRECTION OUTPUT ;
    USE SIGNAL ;
    PORT
      LAYER M4 ;
        RECT  0 13.392 0.084 13.416 ;
    END
  END r_q[304]
  PIN r_q[305]
    DIRECTION OUTPUT ;
    USE SIGNAL ;
    PORT
      LAYER M4 ;
        RECT  0 7.344 0.084 7.368 ;
    END
  END r_q[305]
  PIN r_q[306]
    DIRECTION OUTPUT ;
    USE SIGNAL ;
    PORT
      LAYER M4 ;
        RECT  0 7.44 0.084 7.464 ;
    END
  END r_q[306]
  PIN r_q[307]
    DIRECTION OUTPUT ;
    USE SIGNAL ;
    PORT
      LAYER M4 ;
        RECT  0 7.536 0.084 7.56 ;
    END
  END r_q[307]
  PIN r_q[308]
    DIRECTION OUTPUT ;
    USE SIGNAL ;
    PORT
      LAYER M4 ;
        RECT  0 7.632 0.084 7.656 ;
    END
  END r_q[308]
  PIN r_q[309]
    DIRECTION OUTPUT ;
    USE SIGNAL ;
    PORT
      LAYER M4 ;
        RECT  0 7.728 0.084 7.752 ;
    END
  END r_q[309]
  PIN r_q[30]
    DIRECTION OUTPUT ;
    USE SIGNAL ;
    PORT
      LAYER M4 ;
        RECT  0 5.52 0.084 5.544 ;
    END
  END r_q[30]
  PIN r_q[310]
    DIRECTION OUTPUT ;
    USE SIGNAL ;
    PORT
      LAYER M4 ;
        RECT  0 7.824 0.084 7.848 ;
    END
  END r_q[310]
  PIN r_q[311]
    DIRECTION OUTPUT ;
    USE SIGNAL ;
    PORT
      LAYER M4 ;
        RECT  0 7.92 0.084 7.944 ;
    END
  END r_q[311]
  PIN r_q[312]
    DIRECTION OUTPUT ;
    USE SIGNAL ;
    PORT
      LAYER M4 ;
        RECT  0 8.016 0.084 8.04 ;
    END
  END r_q[312]
  PIN r_q[313]
    DIRECTION OUTPUT ;
    USE SIGNAL ;
    PORT
      LAYER M4 ;
        RECT  0 8.112 0.084 8.136 ;
    END
  END r_q[313]
  PIN r_q[314]
    DIRECTION OUTPUT ;
    USE SIGNAL ;
    PORT
      LAYER M4 ;
        RECT  0 8.208 0.084 8.232 ;
    END
  END r_q[314]
  PIN r_q[315]
    DIRECTION OUTPUT ;
    USE SIGNAL ;
    PORT
      LAYER M4 ;
        RECT  0 8.304 0.084 8.328 ;
    END
  END r_q[315]
  PIN r_q[316]
    DIRECTION OUTPUT ;
    USE SIGNAL ;
    PORT
      LAYER M4 ;
        RECT  0 8.4 0.084 8.424 ;
    END
  END r_q[316]
  PIN r_q[317]
    DIRECTION OUTPUT ;
    USE SIGNAL ;
    PORT
      LAYER M4 ;
        RECT  0 8.496 0.084 8.52 ;
    END
  END r_q[317]
  PIN r_q[318]
    DIRECTION OUTPUT ;
    USE SIGNAL ;
    PORT
      LAYER M4 ;
        RECT  0 8.592 0.084 8.616 ;
    END
  END r_q[318]
  PIN r_q[319]
    DIRECTION OUTPUT ;
    USE SIGNAL ;
    PORT
      LAYER M4 ;
        RECT  0 8.688 0.084 8.712 ;
    END
  END r_q[319]
  PIN r_q[31]
    DIRECTION OUTPUT ;
    USE SIGNAL ;
    PORT
      LAYER M4 ;
        RECT  0 5.616 0.084 5.64 ;
    END
  END r_q[31]
  PIN r_q[320]
    DIRECTION OUTPUT ;
    USE SIGNAL ;
    PORT
      LAYER M4 ;
        RECT  0 8.784 0.084 8.808 ;
    END
  END r_q[320]
  PIN r_q[321]
    DIRECTION OUTPUT ;
    USE SIGNAL ;
    PORT
      LAYER M4 ;
        RECT  0 8.88 0.084 8.904 ;
    END
  END r_q[321]
  PIN r_q[322]
    DIRECTION OUTPUT ;
    USE SIGNAL ;
    PORT
      LAYER M4 ;
        RECT  0 8.976 0.084 9 ;
    END
  END r_q[322]
  PIN r_q[323]
    DIRECTION OUTPUT ;
    USE SIGNAL ;
    PORT
      LAYER M4 ;
        RECT  0 9.072 0.084 9.096 ;
    END
  END r_q[323]
  PIN r_q[324]
    DIRECTION OUTPUT ;
    USE SIGNAL ;
    PORT
      LAYER M4 ;
        RECT  0 9.168 0.084 9.192 ;
    END
  END r_q[324]
  PIN r_q[325]
    DIRECTION OUTPUT ;
    USE SIGNAL ;
    PORT
      LAYER M4 ;
        RECT  0 9.264 0.084 9.288 ;
    END
  END r_q[325]
  PIN r_q[326]
    DIRECTION OUTPUT ;
    USE SIGNAL ;
    PORT
      LAYER M4 ;
        RECT  0 9.36 0.084 9.384 ;
    END
  END r_q[326]
  PIN r_q[327]
    DIRECTION OUTPUT ;
    USE SIGNAL ;
    PORT
      LAYER M4 ;
        RECT  0 9.456 0.084 9.48 ;
    END
  END r_q[327]
  PIN r_q[328]
    DIRECTION OUTPUT ;
    USE SIGNAL ;
    PORT
      LAYER M4 ;
        RECT  0 9.552 0.084 9.576 ;
    END
  END r_q[328]
  PIN r_q[329]
    DIRECTION OUTPUT ;
    USE SIGNAL ;
    PORT
      LAYER M4 ;
        RECT  0 9.648 0.084 9.672 ;
    END
  END r_q[329]
  PIN r_q[32]
    DIRECTION OUTPUT ;
    USE SIGNAL ;
    PORT
      LAYER M4 ;
        RECT  0 5.712 0.084 5.736 ;
    END
  END r_q[32]
  PIN r_q[330]
    DIRECTION OUTPUT ;
    USE SIGNAL ;
    PORT
      LAYER M4 ;
        RECT  0 9.744 0.084 9.768 ;
    END
  END r_q[330]
  PIN r_q[331]
    DIRECTION OUTPUT ;
    USE SIGNAL ;
    PORT
      LAYER M4 ;
        RECT  0 9.84 0.084 9.864 ;
    END
  END r_q[331]
  PIN r_q[332]
    DIRECTION OUTPUT ;
    USE SIGNAL ;
    PORT
      LAYER M4 ;
        RECT  0 9.936 0.084 9.96 ;
    END
  END r_q[332]
  PIN r_q[333]
    DIRECTION OUTPUT ;
    USE SIGNAL ;
    PORT
      LAYER M4 ;
        RECT  0 10.032 0.084 10.056 ;
    END
  END r_q[333]
  PIN r_q[334]
    DIRECTION OUTPUT ;
    USE SIGNAL ;
    PORT
      LAYER M4 ;
        RECT  0 10.128 0.084 10.152 ;
    END
  END r_q[334]
  PIN r_q[335]
    DIRECTION OUTPUT ;
    USE SIGNAL ;
    PORT
      LAYER M4 ;
        RECT  0 10.224 0.084 10.248 ;
    END
  END r_q[335]
  PIN r_q[336]
    DIRECTION OUTPUT ;
    USE SIGNAL ;
    PORT
      LAYER M4 ;
        RECT  0 10.32 0.084 10.344 ;
    END
  END r_q[336]
  PIN r_q[337]
    DIRECTION OUTPUT ;
    USE SIGNAL ;
    PORT
      LAYER M4 ;
        RECT  0 1.2 0.084 1.224 ;
    END
  END r_q[337]
  PIN r_q[338]
    DIRECTION OUTPUT ;
    USE SIGNAL ;
    PORT
      LAYER M4 ;
        RECT  0 1.296 0.084 1.32 ;
    END
  END r_q[338]
  PIN r_q[339]
    DIRECTION OUTPUT ;
    USE SIGNAL ;
    PORT
      LAYER M4 ;
        RECT  0 1.392 0.084 1.416 ;
    END
  END r_q[339]
  PIN r_q[33]
    DIRECTION OUTPUT ;
    USE SIGNAL ;
    PORT
      LAYER M4 ;
        RECT  0 5.808 0.084 5.832 ;
    END
  END r_q[33]
  PIN r_q[340]
    DIRECTION OUTPUT ;
    USE SIGNAL ;
    PORT
      LAYER M4 ;
        RECT  0 1.488 0.084 1.512 ;
    END
  END r_q[340]
  PIN r_q[341]
    DIRECTION OUTPUT ;
    USE SIGNAL ;
    PORT
      LAYER M4 ;
        RECT  0 1.584 0.084 1.608 ;
    END
  END r_q[341]
  PIN r_q[342]
    DIRECTION OUTPUT ;
    USE SIGNAL ;
    PORT
      LAYER M4 ;
        RECT  0 1.68 0.084 1.704 ;
    END
  END r_q[342]
  PIN r_q[343]
    DIRECTION OUTPUT ;
    USE SIGNAL ;
    PORT
      LAYER M4 ;
        RECT  0 1.776 0.084 1.8 ;
    END
  END r_q[343]
  PIN r_q[344]
    DIRECTION OUTPUT ;
    USE SIGNAL ;
    PORT
      LAYER M4 ;
        RECT  0 1.872 0.084 1.896 ;
    END
  END r_q[344]
  PIN r_q[345]
    DIRECTION OUTPUT ;
    USE SIGNAL ;
    PORT
      LAYER M4 ;
        RECT  0 1.968 0.084 1.992 ;
    END
  END r_q[345]
  PIN r_q[346]
    DIRECTION OUTPUT ;
    USE SIGNAL ;
    PORT
      LAYER M4 ;
        RECT  0 2.064 0.084 2.088 ;
    END
  END r_q[346]
  PIN r_q[347]
    DIRECTION OUTPUT ;
    USE SIGNAL ;
    PORT
      LAYER M4 ;
        RECT  0 2.16 0.084 2.184 ;
    END
  END r_q[347]
  PIN r_q[348]
    DIRECTION OUTPUT ;
    USE SIGNAL ;
    PORT
      LAYER M4 ;
        RECT  0 2.256 0.084 2.28 ;
    END
  END r_q[348]
  PIN r_q[349]
    DIRECTION OUTPUT ;
    USE SIGNAL ;
    PORT
      LAYER M4 ;
        RECT  0 2.352 0.084 2.376 ;
    END
  END r_q[349]
  PIN r_q[34]
    DIRECTION OUTPUT ;
    USE SIGNAL ;
    PORT
      LAYER M4 ;
        RECT  0 5.904 0.084 5.928 ;
    END
  END r_q[34]
  PIN r_q[350]
    DIRECTION OUTPUT ;
    USE SIGNAL ;
    PORT
      LAYER M4 ;
        RECT  0 2.448 0.084 2.472 ;
    END
  END r_q[350]
  PIN r_q[351]
    DIRECTION OUTPUT ;
    USE SIGNAL ;
    PORT
      LAYER M4 ;
        RECT  0 2.544 0.084 2.568 ;
    END
  END r_q[351]
  PIN r_q[352]
    DIRECTION OUTPUT ;
    USE SIGNAL ;
    PORT
      LAYER M4 ;
        RECT  0 2.64 0.084 2.664 ;
    END
  END r_q[352]
  PIN r_q[353]
    DIRECTION OUTPUT ;
    USE SIGNAL ;
    PORT
      LAYER M4 ;
        RECT  0 2.736 0.084 2.76 ;
    END
  END r_q[353]
  PIN r_q[354]
    DIRECTION OUTPUT ;
    USE SIGNAL ;
    PORT
      LAYER M4 ;
        RECT  0 2.832 0.084 2.856 ;
    END
  END r_q[354]
  PIN r_q[355]
    DIRECTION OUTPUT ;
    USE SIGNAL ;
    PORT
      LAYER M4 ;
        RECT  0 2.928 0.084 2.952 ;
    END
  END r_q[355]
  PIN r_q[356]
    DIRECTION OUTPUT ;
    USE SIGNAL ;
    PORT
      LAYER M4 ;
        RECT  0 3.024 0.084 3.048 ;
    END
  END r_q[356]
  PIN r_q[357]
    DIRECTION OUTPUT ;
    USE SIGNAL ;
    PORT
      LAYER M4 ;
        RECT  0 3.12 0.084 3.144 ;
    END
  END r_q[357]
  PIN r_q[358]
    DIRECTION OUTPUT ;
    USE SIGNAL ;
    PORT
      LAYER M4 ;
        RECT  0 3.216 0.084 3.24 ;
    END
  END r_q[358]
  PIN r_q[359]
    DIRECTION OUTPUT ;
    USE SIGNAL ;
    PORT
      LAYER M4 ;
        RECT  0 3.312 0.084 3.336 ;
    END
  END r_q[359]
  PIN r_q[35]
    DIRECTION OUTPUT ;
    USE SIGNAL ;
    PORT
      LAYER M4 ;
        RECT  0 6 0.084 6.024 ;
    END
  END r_q[35]
  PIN r_q[360]
    DIRECTION OUTPUT ;
    USE SIGNAL ;
    PORT
      LAYER M4 ;
        RECT  0 3.408 0.084 3.432 ;
    END
  END r_q[360]
  PIN r_q[361]
    DIRECTION OUTPUT ;
    USE SIGNAL ;
    PORT
      LAYER M4 ;
        RECT  0 3.504 0.084 3.528 ;
    END
  END r_q[361]
  PIN r_q[362]
    DIRECTION OUTPUT ;
    USE SIGNAL ;
    PORT
      LAYER M4 ;
        RECT  0 3.6 0.084 3.624 ;
    END
  END r_q[362]
  PIN r_q[363]
    DIRECTION OUTPUT ;
    USE SIGNAL ;
    PORT
      LAYER M4 ;
        RECT  0 3.696 0.084 3.72 ;
    END
  END r_q[363]
  PIN r_q[364]
    DIRECTION OUTPUT ;
    USE SIGNAL ;
    PORT
      LAYER M4 ;
        RECT  0 3.792 0.084 3.816 ;
    END
  END r_q[364]
  PIN r_q[365]
    DIRECTION OUTPUT ;
    USE SIGNAL ;
    PORT
      LAYER M4 ;
        RECT  0 3.888 0.084 3.912 ;
    END
  END r_q[365]
  PIN r_q[366]
    DIRECTION OUTPUT ;
    USE SIGNAL ;
    PORT
      LAYER M4 ;
        RECT  0 3.984 0.084 4.008 ;
    END
  END r_q[366]
  PIN r_q[367]
    DIRECTION OUTPUT ;
    USE SIGNAL ;
    PORT
      LAYER M4 ;
        RECT  0 4.08 0.084 4.104 ;
    END
  END r_q[367]
  PIN r_q[368]
    DIRECTION OUTPUT ;
    USE SIGNAL ;
    PORT
      LAYER M4 ;
        RECT  0 4.176 0.084 4.2 ;
    END
  END r_q[368]
  PIN r_q[369]
    DIRECTION OUTPUT ;
    USE SIGNAL ;
    PORT
      LAYER M4 ;
        RECT  0 33.456 0.084 33.48 ;
    END
  END r_q[369]
  PIN r_q[36]
    DIRECTION OUTPUT ;
    USE SIGNAL ;
    PORT
      LAYER M4 ;
        RECT  0 6.096 0.084 6.12 ;
    END
  END r_q[36]
  PIN r_q[370]
    DIRECTION OUTPUT ;
    USE SIGNAL ;
    PORT
      LAYER M4 ;
        RECT  0 33.552 0.084 33.576 ;
    END
  END r_q[370]
  PIN r_q[371]
    DIRECTION OUTPUT ;
    USE SIGNAL ;
    PORT
      LAYER M4 ;
        RECT  0 33.648 0.084 33.672 ;
    END
  END r_q[371]
  PIN r_q[372]
    DIRECTION OUTPUT ;
    USE SIGNAL ;
    PORT
      LAYER M4 ;
        RECT  0 33.744 0.084 33.768 ;
    END
  END r_q[372]
  PIN r_q[373]
    DIRECTION OUTPUT ;
    USE SIGNAL ;
    PORT
      LAYER M4 ;
        RECT  0 33.84 0.084 33.864 ;
    END
  END r_q[373]
  PIN r_q[374]
    DIRECTION OUTPUT ;
    USE SIGNAL ;
    PORT
      LAYER M4 ;
        RECT  0 33.936 0.084 33.96 ;
    END
  END r_q[374]
  PIN r_q[375]
    DIRECTION OUTPUT ;
    USE SIGNAL ;
    PORT
      LAYER M4 ;
        RECT  0 34.032 0.084 34.056 ;
    END
  END r_q[375]
  PIN r_q[376]
    DIRECTION OUTPUT ;
    USE SIGNAL ;
    PORT
      LAYER M4 ;
        RECT  0 34.128 0.084 34.152 ;
    END
  END r_q[376]
  PIN r_q[377]
    DIRECTION OUTPUT ;
    USE SIGNAL ;
    PORT
      LAYER M4 ;
        RECT  0 34.224 0.084 34.248 ;
    END
  END r_q[377]
  PIN r_q[378]
    DIRECTION OUTPUT ;
    USE SIGNAL ;
    PORT
      LAYER M4 ;
        RECT  0 34.32 0.084 34.344 ;
    END
  END r_q[378]
  PIN r_q[379]
    DIRECTION OUTPUT ;
    USE SIGNAL ;
    PORT
      LAYER M4 ;
        RECT  0 34.416 0.084 34.44 ;
    END
  END r_q[379]
  PIN r_q[37]
    DIRECTION OUTPUT ;
    USE SIGNAL ;
    PORT
      LAYER M4 ;
        RECT  0 6.192 0.084 6.216 ;
    END
  END r_q[37]
  PIN r_q[380]
    DIRECTION OUTPUT ;
    USE SIGNAL ;
    PORT
      LAYER M4 ;
        RECT  0 34.512 0.084 34.536 ;
    END
  END r_q[380]
  PIN r_q[381]
    DIRECTION OUTPUT ;
    USE SIGNAL ;
    PORT
      LAYER M4 ;
        RECT  0 34.608 0.084 34.632 ;
    END
  END r_q[381]
  PIN r_q[382]
    DIRECTION OUTPUT ;
    USE SIGNAL ;
    PORT
      LAYER M4 ;
        RECT  0 34.704 0.084 34.728 ;
    END
  END r_q[382]
  PIN r_q[383]
    DIRECTION OUTPUT ;
    USE SIGNAL ;
    PORT
      LAYER M4 ;
        RECT  0 34.8 0.084 34.824 ;
    END
  END r_q[383]
  PIN r_q[384]
    DIRECTION OUTPUT ;
    USE SIGNAL ;
    PORT
      LAYER M4 ;
        RECT  0 34.896 0.084 34.92 ;
    END
  END r_q[384]
  PIN r_q[385]
    DIRECTION OUTPUT ;
    USE SIGNAL ;
    PORT
      LAYER M4 ;
        RECT  0 34.992 0.084 35.016 ;
    END
  END r_q[385]
  PIN r_q[386]
    DIRECTION OUTPUT ;
    USE SIGNAL ;
    PORT
      LAYER M4 ;
        RECT  0 35.088 0.084 35.112 ;
    END
  END r_q[386]
  PIN r_q[387]
    DIRECTION OUTPUT ;
    USE SIGNAL ;
    PORT
      LAYER M4 ;
        RECT  0 35.184 0.084 35.208 ;
    END
  END r_q[387]
  PIN r_q[388]
    DIRECTION OUTPUT ;
    USE SIGNAL ;
    PORT
      LAYER M4 ;
        RECT  0 35.28 0.084 35.304 ;
    END
  END r_q[388]
  PIN r_q[389]
    DIRECTION OUTPUT ;
    USE SIGNAL ;
    PORT
      LAYER M4 ;
        RECT  0 35.376 0.084 35.4 ;
    END
  END r_q[389]
  PIN r_q[38]
    DIRECTION OUTPUT ;
    USE SIGNAL ;
    PORT
      LAYER M4 ;
        RECT  0 6.288 0.084 6.312 ;
    END
  END r_q[38]
  PIN r_q[390]
    DIRECTION OUTPUT ;
    USE SIGNAL ;
    PORT
      LAYER M4 ;
        RECT  0 35.472 0.084 35.496 ;
    END
  END r_q[390]
  PIN r_q[391]
    DIRECTION OUTPUT ;
    USE SIGNAL ;
    PORT
      LAYER M4 ;
        RECT  0 35.568 0.084 35.592 ;
    END
  END r_q[391]
  PIN r_q[392]
    DIRECTION OUTPUT ;
    USE SIGNAL ;
    PORT
      LAYER M4 ;
        RECT  0 35.664 0.084 35.688 ;
    END
  END r_q[392]
  PIN r_q[393]
    DIRECTION OUTPUT ;
    USE SIGNAL ;
    PORT
      LAYER M4 ;
        RECT  0 35.76 0.084 35.784 ;
    END
  END r_q[393]
  PIN r_q[394]
    DIRECTION OUTPUT ;
    USE SIGNAL ;
    PORT
      LAYER M4 ;
        RECT  0 35.856 0.084 35.88 ;
    END
  END r_q[394]
  PIN r_q[395]
    DIRECTION OUTPUT ;
    USE SIGNAL ;
    PORT
      LAYER M4 ;
        RECT  0 35.952 0.084 35.976 ;
    END
  END r_q[395]
  PIN r_q[396]
    DIRECTION OUTPUT ;
    USE SIGNAL ;
    PORT
      LAYER M4 ;
        RECT  0 36.048 0.084 36.072 ;
    END
  END r_q[396]
  PIN r_q[397]
    DIRECTION OUTPUT ;
    USE SIGNAL ;
    PORT
      LAYER M4 ;
        RECT  0 36.144 0.084 36.168 ;
    END
  END r_q[397]
  PIN r_q[398]
    DIRECTION OUTPUT ;
    USE SIGNAL ;
    PORT
      LAYER M4 ;
        RECT  0 36.24 0.084 36.264 ;
    END
  END r_q[398]
  PIN r_q[399]
    DIRECTION OUTPUT ;
    USE SIGNAL ;
    PORT
      LAYER M4 ;
        RECT  0 36.336 0.084 36.36 ;
    END
  END r_q[399]
  PIN r_q[39]
    DIRECTION OUTPUT ;
    USE SIGNAL ;
    PORT
      LAYER M4 ;
        RECT  0 6.384 0.084 6.408 ;
    END
  END r_q[39]
  PIN r_q[3]
    DIRECTION OUTPUT ;
    USE SIGNAL ;
    PORT
      LAYER M4 ;
        RECT  0 22.128 0.084 22.152 ;
    END
  END r_q[3]
  PIN r_q[400]
    DIRECTION OUTPUT ;
    USE SIGNAL ;
    PORT
      LAYER M4 ;
        RECT  0 36.432 0.084 36.456 ;
    END
  END r_q[400]
  PIN r_q[401]
    DIRECTION OUTPUT ;
    USE SIGNAL ;
    PORT
      LAYER M4 ;
        RECT  0 36.528 0.084 36.552 ;
    END
  END r_q[401]
  PIN r_q[402]
    DIRECTION OUTPUT ;
    USE SIGNAL ;
    PORT
      LAYER M4 ;
        RECT  0 36.624 0.084 36.648 ;
    END
  END r_q[402]
  PIN r_q[403]
    DIRECTION OUTPUT ;
    USE SIGNAL ;
    PORT
      LAYER M4 ;
        RECT  0 36.72 0.084 36.744 ;
    END
  END r_q[403]
  PIN r_q[404]
    DIRECTION OUTPUT ;
    USE SIGNAL ;
    PORT
      LAYER M4 ;
        RECT  0 36.816 0.084 36.84 ;
    END
  END r_q[404]
  PIN r_q[405]
    DIRECTION OUTPUT ;
    USE SIGNAL ;
    PORT
      LAYER M4 ;
        RECT  0 36.912 0.084 36.936 ;
    END
  END r_q[405]
  PIN r_q[406]
    DIRECTION OUTPUT ;
    USE SIGNAL ;
    PORT
      LAYER M4 ;
        RECT  0 37.008 0.084 37.032 ;
    END
  END r_q[406]
  PIN r_q[407]
    DIRECTION OUTPUT ;
    USE SIGNAL ;
    PORT
      LAYER M4 ;
        RECT  0 37.104 0.084 37.128 ;
    END
  END r_q[407]
  PIN r_q[408]
    DIRECTION OUTPUT ;
    USE SIGNAL ;
    PORT
      LAYER M4 ;
        RECT  0 37.2 0.084 37.224 ;
    END
  END r_q[408]
  PIN r_q[409]
    DIRECTION OUTPUT ;
    USE SIGNAL ;
    PORT
      LAYER M4 ;
        RECT  0 37.296 0.084 37.32 ;
    END
  END r_q[409]
  PIN r_q[40]
    DIRECTION OUTPUT ;
    USE SIGNAL ;
    PORT
      LAYER M4 ;
        RECT  0 6.48 0.084 6.504 ;
    END
  END r_q[40]
  PIN r_q[410]
    DIRECTION OUTPUT ;
    USE SIGNAL ;
    PORT
      LAYER M4 ;
        RECT  0 37.392 0.084 37.416 ;
    END
  END r_q[410]
  PIN r_q[411]
    DIRECTION OUTPUT ;
    USE SIGNAL ;
    PORT
      LAYER M4 ;
        RECT  0 37.488 0.084 37.512 ;
    END
  END r_q[411]
  PIN r_q[412]
    DIRECTION OUTPUT ;
    USE SIGNAL ;
    PORT
      LAYER M4 ;
        RECT  0 37.584 0.084 37.608 ;
    END
  END r_q[412]
  PIN r_q[413]
    DIRECTION OUTPUT ;
    USE SIGNAL ;
    PORT
      LAYER M4 ;
        RECT  0 37.68 0.084 37.704 ;
    END
  END r_q[413]
  PIN r_q[414]
    DIRECTION OUTPUT ;
    USE SIGNAL ;
    PORT
      LAYER M4 ;
        RECT  0 37.776 0.084 37.8 ;
    END
  END r_q[414]
  PIN r_q[415]
    DIRECTION OUTPUT ;
    USE SIGNAL ;
    PORT
      LAYER M4 ;
        RECT  0 37.872 0.084 37.896 ;
    END
  END r_q[415]
  PIN r_q[416]
    DIRECTION OUTPUT ;
    USE SIGNAL ;
    PORT
      LAYER M4 ;
        RECT  0 37.968 0.084 37.992 ;
    END
  END r_q[416]
  PIN r_q[417]
    DIRECTION OUTPUT ;
    USE SIGNAL ;
    PORT
      LAYER M4 ;
        RECT  0 38.064 0.084 38.088 ;
    END
  END r_q[417]
  PIN r_q[418]
    DIRECTION OUTPUT ;
    USE SIGNAL ;
    PORT
      LAYER M4 ;
        RECT  0 38.16 0.084 38.184 ;
    END
  END r_q[418]
  PIN r_q[419]
    DIRECTION OUTPUT ;
    USE SIGNAL ;
    PORT
      LAYER M4 ;
        RECT  0 38.256 0.084 38.28 ;
    END
  END r_q[419]
  PIN r_q[41]
    DIRECTION OUTPUT ;
    USE SIGNAL ;
    PORT
      LAYER M4 ;
        RECT  0 6.576 0.084 6.6 ;
    END
  END r_q[41]
  PIN r_q[420]
    DIRECTION OUTPUT ;
    USE SIGNAL ;
    PORT
      LAYER M4 ;
        RECT  0 38.352 0.084 38.376 ;
    END
  END r_q[420]
  PIN r_q[421]
    DIRECTION OUTPUT ;
    USE SIGNAL ;
    PORT
      LAYER M4 ;
        RECT  0 38.448 0.084 38.472 ;
    END
  END r_q[421]
  PIN r_q[422]
    DIRECTION OUTPUT ;
    USE SIGNAL ;
    PORT
      LAYER M4 ;
        RECT  0 38.544 0.084 38.568 ;
    END
  END r_q[422]
  PIN r_q[423]
    DIRECTION OUTPUT ;
    USE SIGNAL ;
    PORT
      LAYER M4 ;
        RECT  0 38.64 0.084 38.664 ;
    END
  END r_q[423]
  PIN r_q[424]
    DIRECTION OUTPUT ;
    USE SIGNAL ;
    PORT
      LAYER M4 ;
        RECT  0 38.736 0.084 38.76 ;
    END
  END r_q[424]
  PIN r_q[425]
    DIRECTION OUTPUT ;
    USE SIGNAL ;
    PORT
      LAYER M4 ;
        RECT  0 38.832 0.084 38.856 ;
    END
  END r_q[425]
  PIN r_q[426]
    DIRECTION OUTPUT ;
    USE SIGNAL ;
    PORT
      LAYER M4 ;
        RECT  0 38.928 0.084 38.952 ;
    END
  END r_q[426]
  PIN r_q[427]
    DIRECTION OUTPUT ;
    USE SIGNAL ;
    PORT
      LAYER M4 ;
        RECT  0 39.024 0.084 39.048 ;
    END
  END r_q[427]
  PIN r_q[428]
    DIRECTION OUTPUT ;
    USE SIGNAL ;
    PORT
      LAYER M4 ;
        RECT  0 39.12 0.084 39.144 ;
    END
  END r_q[428]
  PIN r_q[429]
    DIRECTION OUTPUT ;
    USE SIGNAL ;
    PORT
      LAYER M4 ;
        RECT  0 39.216 0.084 39.24 ;
    END
  END r_q[429]
  PIN r_q[42]
    DIRECTION OUTPUT ;
    USE SIGNAL ;
    PORT
      LAYER M4 ;
        RECT  0 6.672 0.084 6.696 ;
    END
  END r_q[42]
  PIN r_q[430]
    DIRECTION OUTPUT ;
    USE SIGNAL ;
    PORT
      LAYER M4 ;
        RECT  0 39.312 0.084 39.336 ;
    END
  END r_q[430]
  PIN r_q[431]
    DIRECTION OUTPUT ;
    USE SIGNAL ;
    PORT
      LAYER M4 ;
        RECT  0 39.408 0.084 39.432 ;
    END
  END r_q[431]
  PIN r_q[432]
    DIRECTION OUTPUT ;
    USE SIGNAL ;
    PORT
      LAYER M4 ;
        RECT  0 39.504 0.084 39.528 ;
    END
  END r_q[432]
  PIN r_q[433]
    DIRECTION OUTPUT ;
    USE SIGNAL ;
    PORT
      LAYER M4 ;
        RECT  0 39.6 0.084 39.624 ;
    END
  END r_q[433]
  PIN r_q[434]
    DIRECTION OUTPUT ;
    USE SIGNAL ;
    PORT
      LAYER M4 ;
        RECT  0 39.696 0.084 39.72 ;
    END
  END r_q[434]
  PIN r_q[435]
    DIRECTION OUTPUT ;
    USE SIGNAL ;
    PORT
      LAYER M4 ;
        RECT  0 39.792 0.084 39.816 ;
    END
  END r_q[435]
  PIN r_q[436]
    DIRECTION OUTPUT ;
    USE SIGNAL ;
    PORT
      LAYER M4 ;
        RECT  0 39.888 0.084 39.912 ;
    END
  END r_q[436]
  PIN r_q[437]
    DIRECTION OUTPUT ;
    USE SIGNAL ;
    PORT
      LAYER M4 ;
        RECT  0 39.984 0.084 40.008 ;
    END
  END r_q[437]
  PIN r_q[438]
    DIRECTION OUTPUT ;
    USE SIGNAL ;
    PORT
      LAYER M4 ;
        RECT  0 40.08 0.084 40.104 ;
    END
  END r_q[438]
  PIN r_q[439]
    DIRECTION OUTPUT ;
    USE SIGNAL ;
    PORT
      LAYER M4 ;
        RECT  0 40.176 0.084 40.2 ;
    END
  END r_q[439]
  PIN r_q[43]
    DIRECTION OUTPUT ;
    USE SIGNAL ;
    PORT
      LAYER M4 ;
        RECT  0 6.768 0.084 6.792 ;
    END
  END r_q[43]
  PIN r_q[440]
    DIRECTION OUTPUT ;
    USE SIGNAL ;
    PORT
      LAYER M4 ;
        RECT  0 40.272 0.084 40.296 ;
    END
  END r_q[440]
  PIN r_q[441]
    DIRECTION OUTPUT ;
    USE SIGNAL ;
    PORT
      LAYER M4 ;
        RECT  0 40.368 0.084 40.392 ;
    END
  END r_q[441]
  PIN r_q[442]
    DIRECTION OUTPUT ;
    USE SIGNAL ;
    PORT
      LAYER M4 ;
        RECT  0 40.464 0.084 40.488 ;
    END
  END r_q[442]
  PIN r_q[443]
    DIRECTION OUTPUT ;
    USE SIGNAL ;
    PORT
      LAYER M4 ;
        RECT  0 40.56 0.084 40.584 ;
    END
  END r_q[443]
  PIN r_q[444]
    DIRECTION OUTPUT ;
    USE SIGNAL ;
    PORT
      LAYER M4 ;
        RECT  0 40.656 0.084 40.68 ;
    END
  END r_q[444]
  PIN r_q[445]
    DIRECTION OUTPUT ;
    USE SIGNAL ;
    PORT
      LAYER M4 ;
        RECT  0 40.752 0.084 40.776 ;
    END
  END r_q[445]
  PIN r_q[446]
    DIRECTION OUTPUT ;
    USE SIGNAL ;
    PORT
      LAYER M4 ;
        RECT  0 40.848 0.084 40.872 ;
    END
  END r_q[446]
  PIN r_q[447]
    DIRECTION OUTPUT ;
    USE SIGNAL ;
    PORT
      LAYER M4 ;
        RECT  0 40.944 0.084 40.968 ;
    END
  END r_q[447]
  PIN r_q[448]
    DIRECTION OUTPUT ;
    USE SIGNAL ;
    PORT
      LAYER M4 ;
        RECT  0 41.04 0.084 41.064 ;
    END
  END r_q[448]
  PIN r_q[449]
    DIRECTION OUTPUT ;
    USE SIGNAL ;
    PORT
      LAYER M4 ;
        RECT  0 41.136 0.084 41.16 ;
    END
  END r_q[449]
  PIN r_q[44]
    DIRECTION OUTPUT ;
    USE SIGNAL ;
    PORT
      LAYER M4 ;
        RECT  0 6.864 0.084 6.888 ;
    END
  END r_q[44]
  PIN r_q[450]
    DIRECTION OUTPUT ;
    USE SIGNAL ;
    PORT
      LAYER M4 ;
        RECT  0 41.232 0.084 41.256 ;
    END
  END r_q[450]
  PIN r_q[451]
    DIRECTION OUTPUT ;
    USE SIGNAL ;
    PORT
      LAYER M4 ;
        RECT  0 41.328 0.084 41.352 ;
    END
  END r_q[451]
  PIN r_q[452]
    DIRECTION OUTPUT ;
    USE SIGNAL ;
    PORT
      LAYER M4 ;
        RECT  0 41.424 0.084 41.448 ;
    END
  END r_q[452]
  PIN r_q[453]
    DIRECTION OUTPUT ;
    USE SIGNAL ;
    PORT
      LAYER M4 ;
        RECT  0 41.52 0.084 41.544 ;
    END
  END r_q[453]
  PIN r_q[454]
    DIRECTION OUTPUT ;
    USE SIGNAL ;
    PORT
      LAYER M4 ;
        RECT  0 41.616 0.084 41.64 ;
    END
  END r_q[454]
  PIN r_q[455]
    DIRECTION OUTPUT ;
    USE SIGNAL ;
    PORT
      LAYER M4 ;
        RECT  0 41.712 0.084 41.736 ;
    END
  END r_q[455]
  PIN r_q[456]
    DIRECTION OUTPUT ;
    USE SIGNAL ;
    PORT
      LAYER M4 ;
        RECT  0 41.808 0.084 41.832 ;
    END
  END r_q[456]
  PIN r_q[457]
    DIRECTION OUTPUT ;
    USE SIGNAL ;
    PORT
      LAYER M4 ;
        RECT  0 41.904 0.084 41.928 ;
    END
  END r_q[457]
  PIN r_q[458]
    DIRECTION OUTPUT ;
    USE SIGNAL ;
    PORT
      LAYER M4 ;
        RECT  0 42 0.084 42.024 ;
    END
  END r_q[458]
  PIN r_q[459]
    DIRECTION OUTPUT ;
    USE SIGNAL ;
    PORT
      LAYER M4 ;
        RECT  0 42.096 0.084 42.12 ;
    END
  END r_q[459]
  PIN r_q[45]
    DIRECTION OUTPUT ;
    USE SIGNAL ;
    PORT
      LAYER M4 ;
        RECT  0 6.96 0.084 6.984 ;
    END
  END r_q[45]
  PIN r_q[460]
    DIRECTION OUTPUT ;
    USE SIGNAL ;
    PORT
      LAYER M4 ;
        RECT  0 42.192 0.084 42.216 ;
    END
  END r_q[460]
  PIN r_q[461]
    DIRECTION OUTPUT ;
    USE SIGNAL ;
    PORT
      LAYER M4 ;
        RECT  0 42.288 0.084 42.312 ;
    END
  END r_q[461]
  PIN r_q[462]
    DIRECTION OUTPUT ;
    USE SIGNAL ;
    PORT
      LAYER M4 ;
        RECT  0 42.384 0.084 42.408 ;
    END
  END r_q[462]
  PIN r_q[463]
    DIRECTION OUTPUT ;
    USE SIGNAL ;
    PORT
      LAYER M4 ;
        RECT  0 42.48 0.084 42.504 ;
    END
  END r_q[463]
  PIN r_q[464]
    DIRECTION OUTPUT ;
    USE SIGNAL ;
    PORT
      LAYER M4 ;
        RECT  0 42.576 0.084 42.6 ;
    END
  END r_q[464]
  PIN r_q[465]
    DIRECTION OUTPUT ;
    USE SIGNAL ;
    PORT
      LAYER M4 ;
        RECT  0 45.744 0.084 45.768 ;
    END
  END r_q[465]
  PIN r_q[466]
    DIRECTION OUTPUT ;
    USE SIGNAL ;
    PORT
      LAYER M4 ;
        RECT  0 45.84 0.084 45.864 ;
    END
  END r_q[466]
  PIN r_q[467]
    DIRECTION OUTPUT ;
    USE SIGNAL ;
    PORT
      LAYER M4 ;
        RECT  0 45.936 0.084 45.96 ;
    END
  END r_q[467]
  PIN r_q[468]
    DIRECTION OUTPUT ;
    USE SIGNAL ;
    PORT
      LAYER M4 ;
        RECT  0 46.032 0.084 46.056 ;
    END
  END r_q[468]
  PIN r_q[469]
    DIRECTION OUTPUT ;
    USE SIGNAL ;
    PORT
      LAYER M4 ;
        RECT  0 46.128 0.084 46.152 ;
    END
  END r_q[469]
  PIN r_q[46]
    DIRECTION OUTPUT ;
    USE SIGNAL ;
    PORT
      LAYER M4 ;
        RECT  0 7.056 0.084 7.08 ;
    END
  END r_q[46]
  PIN r_q[470]
    DIRECTION OUTPUT ;
    USE SIGNAL ;
    PORT
      LAYER M4 ;
        RECT  0 46.224 0.084 46.248 ;
    END
  END r_q[470]
  PIN r_q[471]
    DIRECTION OUTPUT ;
    USE SIGNAL ;
    PORT
      LAYER M4 ;
        RECT  0 46.32 0.084 46.344 ;
    END
  END r_q[471]
  PIN r_q[472]
    DIRECTION OUTPUT ;
    USE SIGNAL ;
    PORT
      LAYER M4 ;
        RECT  0 46.416 0.084 46.44 ;
    END
  END r_q[472]
  PIN r_q[473]
    DIRECTION OUTPUT ;
    USE SIGNAL ;
    PORT
      LAYER M4 ;
        RECT  0 46.512 0.084 46.536 ;
    END
  END r_q[473]
  PIN r_q[474]
    DIRECTION OUTPUT ;
    USE SIGNAL ;
    PORT
      LAYER M4 ;
        RECT  0 46.608 0.084 46.632 ;
    END
  END r_q[474]
  PIN r_q[475]
    DIRECTION OUTPUT ;
    USE SIGNAL ;
    PORT
      LAYER M4 ;
        RECT  0 46.704 0.084 46.728 ;
    END
  END r_q[475]
  PIN r_q[476]
    DIRECTION OUTPUT ;
    USE SIGNAL ;
    PORT
      LAYER M4 ;
        RECT  0 46.8 0.084 46.824 ;
    END
  END r_q[476]
  PIN r_q[477]
    DIRECTION OUTPUT ;
    USE SIGNAL ;
    PORT
      LAYER M4 ;
        RECT  0 46.896 0.084 46.92 ;
    END
  END r_q[477]
  PIN r_q[478]
    DIRECTION OUTPUT ;
    USE SIGNAL ;
    PORT
      LAYER M4 ;
        RECT  0 46.992 0.084 47.016 ;
    END
  END r_q[478]
  PIN r_q[479]
    DIRECTION OUTPUT ;
    USE SIGNAL ;
    PORT
      LAYER M4 ;
        RECT  0 47.088 0.084 47.112 ;
    END
  END r_q[479]
  PIN r_q[47]
    DIRECTION OUTPUT ;
    USE SIGNAL ;
    PORT
      LAYER M4 ;
        RECT  0 7.152 0.084 7.176 ;
    END
  END r_q[47]
  PIN r_q[480]
    DIRECTION OUTPUT ;
    USE SIGNAL ;
    PORT
      LAYER M4 ;
        RECT  0 47.184 0.084 47.208 ;
    END
  END r_q[480]
  PIN r_q[481]
    DIRECTION OUTPUT ;
    USE SIGNAL ;
    PORT
      LAYER M4 ;
        RECT  0 47.28 0.084 47.304 ;
    END
  END r_q[481]
  PIN r_q[482]
    DIRECTION OUTPUT ;
    USE SIGNAL ;
    PORT
      LAYER M4 ;
        RECT  0 47.376 0.084 47.4 ;
    END
  END r_q[482]
  PIN r_q[483]
    DIRECTION OUTPUT ;
    USE SIGNAL ;
    PORT
      LAYER M4 ;
        RECT  0 47.472 0.084 47.496 ;
    END
  END r_q[483]
  PIN r_q[484]
    DIRECTION OUTPUT ;
    USE SIGNAL ;
    PORT
      LAYER M4 ;
        RECT  0 47.568 0.084 47.592 ;
    END
  END r_q[484]
  PIN r_q[485]
    DIRECTION OUTPUT ;
    USE SIGNAL ;
    PORT
      LAYER M4 ;
        RECT  0 47.664 0.084 47.688 ;
    END
  END r_q[485]
  PIN r_q[486]
    DIRECTION OUTPUT ;
    USE SIGNAL ;
    PORT
      LAYER M4 ;
        RECT  0 47.76 0.084 47.784 ;
    END
  END r_q[486]
  PIN r_q[487]
    DIRECTION OUTPUT ;
    USE SIGNAL ;
    PORT
      LAYER M4 ;
        RECT  0 47.856 0.084 47.88 ;
    END
  END r_q[487]
  PIN r_q[488]
    DIRECTION OUTPUT ;
    USE SIGNAL ;
    PORT
      LAYER M4 ;
        RECT  0 47.952 0.084 47.976 ;
    END
  END r_q[488]
  PIN r_q[489]
    DIRECTION OUTPUT ;
    USE SIGNAL ;
    PORT
      LAYER M4 ;
        RECT  0 48.048 0.084 48.072 ;
    END
  END r_q[489]
  PIN r_q[48]
    DIRECTION OUTPUT ;
    USE SIGNAL ;
    PORT
      LAYER M4 ;
        RECT  0 7.248 0.084 7.272 ;
    END
  END r_q[48]
  PIN r_q[490]
    DIRECTION OUTPUT ;
    USE SIGNAL ;
    PORT
      LAYER M4 ;
        RECT  0 48.144 0.084 48.168 ;
    END
  END r_q[490]
  PIN r_q[491]
    DIRECTION OUTPUT ;
    USE SIGNAL ;
    PORT
      LAYER M4 ;
        RECT  0 48.24 0.084 48.264 ;
    END
  END r_q[491]
  PIN r_q[492]
    DIRECTION OUTPUT ;
    USE SIGNAL ;
    PORT
      LAYER M4 ;
        RECT  0 48.336 0.084 48.36 ;
    END
  END r_q[492]
  PIN r_q[493]
    DIRECTION OUTPUT ;
    USE SIGNAL ;
    PORT
      LAYER M4 ;
        RECT  0 48.432 0.084 48.456 ;
    END
  END r_q[493]
  PIN r_q[494]
    DIRECTION OUTPUT ;
    USE SIGNAL ;
    PORT
      LAYER M4 ;
        RECT  0 48.528 0.084 48.552 ;
    END
  END r_q[494]
  PIN r_q[495]
    DIRECTION OUTPUT ;
    USE SIGNAL ;
    PORT
      LAYER M4 ;
        RECT  0 48.624 0.084 48.648 ;
    END
  END r_q[495]
  PIN r_q[496]
    DIRECTION OUTPUT ;
    USE SIGNAL ;
    PORT
      LAYER M4 ;
        RECT  0 48.72 0.084 48.744 ;
    END
  END r_q[496]
  PIN r_q[497]
    DIRECTION OUTPUT ;
    USE SIGNAL ;
    PORT
      LAYER M4 ;
        RECT  0 52.656 0.084 52.68 ;
    END
  END r_q[497]
  PIN r_q[498]
    DIRECTION OUTPUT ;
    USE SIGNAL ;
    PORT
      LAYER M4 ;
        RECT  0 52.752 0.084 52.776 ;
    END
  END r_q[498]
  PIN r_q[499]
    DIRECTION OUTPUT ;
    USE SIGNAL ;
    PORT
      LAYER M4 ;
        RECT  0 52.848 0.084 52.872 ;
    END
  END r_q[499]
  PIN r_q[49]
    DIRECTION OUTPUT ;
    USE SIGNAL ;
    PORT
      LAYER M4 ;
        RECT  0 17.328 0.084 17.352 ;
    END
  END r_q[49]
  PIN r_q[4]
    DIRECTION OUTPUT ;
    USE SIGNAL ;
    PORT
      LAYER M4 ;
        RECT  0 22.224 0.084 22.248 ;
    END
  END r_q[4]
  PIN r_q[500]
    DIRECTION OUTPUT ;
    USE SIGNAL ;
    PORT
      LAYER M4 ;
        RECT  0 52.944 0.084 52.968 ;
    END
  END r_q[500]
  PIN r_q[501]
    DIRECTION OUTPUT ;
    USE SIGNAL ;
    PORT
      LAYER M4 ;
        RECT  0 53.04 0.084 53.064 ;
    END
  END r_q[501]
  PIN r_q[502]
    DIRECTION OUTPUT ;
    USE SIGNAL ;
    PORT
      LAYER M4 ;
        RECT  0 53.136 0.084 53.16 ;
    END
  END r_q[502]
  PIN r_q[503]
    DIRECTION OUTPUT ;
    USE SIGNAL ;
    PORT
      LAYER M4 ;
        RECT  0 53.232 0.084 53.256 ;
    END
  END r_q[503]
  PIN r_q[504]
    DIRECTION OUTPUT ;
    USE SIGNAL ;
    PORT
      LAYER M4 ;
        RECT  0 53.328 0.084 53.352 ;
    END
  END r_q[504]
  PIN r_q[505]
    DIRECTION OUTPUT ;
    USE SIGNAL ;
    PORT
      LAYER M4 ;
        RECT  0 53.424 0.084 53.448 ;
    END
  END r_q[505]
  PIN r_q[506]
    DIRECTION OUTPUT ;
    USE SIGNAL ;
    PORT
      LAYER M4 ;
        RECT  0 53.52 0.084 53.544 ;
    END
  END r_q[506]
  PIN r_q[507]
    DIRECTION OUTPUT ;
    USE SIGNAL ;
    PORT
      LAYER M4 ;
        RECT  0 53.616 0.084 53.64 ;
    END
  END r_q[507]
  PIN r_q[508]
    DIRECTION OUTPUT ;
    USE SIGNAL ;
    PORT
      LAYER M4 ;
        RECT  0 53.712 0.084 53.736 ;
    END
  END r_q[508]
  PIN r_q[509]
    DIRECTION OUTPUT ;
    USE SIGNAL ;
    PORT
      LAYER M4 ;
        RECT  0 53.808 0.084 53.832 ;
    END
  END r_q[509]
  PIN r_q[50]
    DIRECTION OUTPUT ;
    USE SIGNAL ;
    PORT
      LAYER M4 ;
        RECT  0 17.424 0.084 17.448 ;
    END
  END r_q[50]
  PIN r_q[510]
    DIRECTION OUTPUT ;
    USE SIGNAL ;
    PORT
      LAYER M4 ;
        RECT  0 53.904 0.084 53.928 ;
    END
  END r_q[510]
  PIN r_q[511]
    DIRECTION OUTPUT ;
    USE SIGNAL ;
    PORT
      LAYER M4 ;
        RECT  0 54 0.084 54.024 ;
    END
  END r_q[511]
  PIN r_q[51]
    DIRECTION OUTPUT ;
    USE SIGNAL ;
    PORT
      LAYER M4 ;
        RECT  0 17.52 0.084 17.544 ;
    END
  END r_q[51]
  PIN r_q[52]
    DIRECTION OUTPUT ;
    USE SIGNAL ;
    PORT
      LAYER M4 ;
        RECT  0 17.616 0.084 17.64 ;
    END
  END r_q[52]
  PIN r_q[53]
    DIRECTION OUTPUT ;
    USE SIGNAL ;
    PORT
      LAYER M4 ;
        RECT  0 17.712 0.084 17.736 ;
    END
  END r_q[53]
  PIN r_q[54]
    DIRECTION OUTPUT ;
    USE SIGNAL ;
    PORT
      LAYER M4 ;
        RECT  0 17.808 0.084 17.832 ;
    END
  END r_q[54]
  PIN r_q[55]
    DIRECTION OUTPUT ;
    USE SIGNAL ;
    PORT
      LAYER M4 ;
        RECT  0 17.904 0.084 17.928 ;
    END
  END r_q[55]
  PIN r_q[56]
    DIRECTION OUTPUT ;
    USE SIGNAL ;
    PORT
      LAYER M4 ;
        RECT  0 18 0.084 18.024 ;
    END
  END r_q[56]
  PIN r_q[57]
    DIRECTION OUTPUT ;
    USE SIGNAL ;
    PORT
      LAYER M4 ;
        RECT  0 18.096 0.084 18.12 ;
    END
  END r_q[57]
  PIN r_q[58]
    DIRECTION OUTPUT ;
    USE SIGNAL ;
    PORT
      LAYER M4 ;
        RECT  0 18.192 0.084 18.216 ;
    END
  END r_q[58]
  PIN r_q[59]
    DIRECTION OUTPUT ;
    USE SIGNAL ;
    PORT
      LAYER M4 ;
        RECT  0 18.288 0.084 18.312 ;
    END
  END r_q[59]
  PIN r_q[5]
    DIRECTION OUTPUT ;
    USE SIGNAL ;
    PORT
      LAYER M4 ;
        RECT  0 22.32 0.084 22.344 ;
    END
  END r_q[5]
  PIN r_q[60]
    DIRECTION OUTPUT ;
    USE SIGNAL ;
    PORT
      LAYER M4 ;
        RECT  0 18.384 0.084 18.408 ;
    END
  END r_q[60]
  PIN r_q[61]
    DIRECTION OUTPUT ;
    USE SIGNAL ;
    PORT
      LAYER M4 ;
        RECT  0 18.48 0.084 18.504 ;
    END
  END r_q[61]
  PIN r_q[62]
    DIRECTION OUTPUT ;
    USE SIGNAL ;
    PORT
      LAYER M4 ;
        RECT  0 18.576 0.084 18.6 ;
    END
  END r_q[62]
  PIN r_q[63]
    DIRECTION OUTPUT ;
    USE SIGNAL ;
    PORT
      LAYER M4 ;
        RECT  0 18.672 0.084 18.696 ;
    END
  END r_q[63]
  PIN r_q[64]
    DIRECTION OUTPUT ;
    USE SIGNAL ;
    PORT
      LAYER M4 ;
        RECT  0 18.768 0.084 18.792 ;
    END
  END r_q[64]
  PIN r_q[65]
    DIRECTION OUTPUT ;
    USE SIGNAL ;
    PORT
      LAYER M4 ;
        RECT  0 18.864 0.084 18.888 ;
    END
  END r_q[65]
  PIN r_q[66]
    DIRECTION OUTPUT ;
    USE SIGNAL ;
    PORT
      LAYER M4 ;
        RECT  0 18.96 0.084 18.984 ;
    END
  END r_q[66]
  PIN r_q[67]
    DIRECTION OUTPUT ;
    USE SIGNAL ;
    PORT
      LAYER M4 ;
        RECT  0 19.056 0.084 19.08 ;
    END
  END r_q[67]
  PIN r_q[68]
    DIRECTION OUTPUT ;
    USE SIGNAL ;
    PORT
      LAYER M4 ;
        RECT  0 19.152 0.084 19.176 ;
    END
  END r_q[68]
  PIN r_q[69]
    DIRECTION OUTPUT ;
    USE SIGNAL ;
    PORT
      LAYER M4 ;
        RECT  0 19.248 0.084 19.272 ;
    END
  END r_q[69]
  PIN r_q[6]
    DIRECTION OUTPUT ;
    USE SIGNAL ;
    PORT
      LAYER M4 ;
        RECT  0 22.416 0.084 22.44 ;
    END
  END r_q[6]
  PIN r_q[70]
    DIRECTION OUTPUT ;
    USE SIGNAL ;
    PORT
      LAYER M4 ;
        RECT  0 19.344 0.084 19.368 ;
    END
  END r_q[70]
  PIN r_q[71]
    DIRECTION OUTPUT ;
    USE SIGNAL ;
    PORT
      LAYER M4 ;
        RECT  0 19.44 0.084 19.464 ;
    END
  END r_q[71]
  PIN r_q[72]
    DIRECTION OUTPUT ;
    USE SIGNAL ;
    PORT
      LAYER M4 ;
        RECT  0 19.536 0.084 19.56 ;
    END
  END r_q[72]
  PIN r_q[73]
    DIRECTION OUTPUT ;
    USE SIGNAL ;
    PORT
      LAYER M4 ;
        RECT  0 19.632 0.084 19.656 ;
    END
  END r_q[73]
  PIN r_q[74]
    DIRECTION OUTPUT ;
    USE SIGNAL ;
    PORT
      LAYER M4 ;
        RECT  0 19.728 0.084 19.752 ;
    END
  END r_q[74]
  PIN r_q[75]
    DIRECTION OUTPUT ;
    USE SIGNAL ;
    PORT
      LAYER M4 ;
        RECT  0 19.824 0.084 19.848 ;
    END
  END r_q[75]
  PIN r_q[76]
    DIRECTION OUTPUT ;
    USE SIGNAL ;
    PORT
      LAYER M4 ;
        RECT  0 19.92 0.084 19.944 ;
    END
  END r_q[76]
  PIN r_q[77]
    DIRECTION OUTPUT ;
    USE SIGNAL ;
    PORT
      LAYER M4 ;
        RECT  0 20.016 0.084 20.04 ;
    END
  END r_q[77]
  PIN r_q[78]
    DIRECTION OUTPUT ;
    USE SIGNAL ;
    PORT
      LAYER M4 ;
        RECT  0 20.112 0.084 20.136 ;
    END
  END r_q[78]
  PIN r_q[79]
    DIRECTION OUTPUT ;
    USE SIGNAL ;
    PORT
      LAYER M4 ;
        RECT  0 20.208 0.084 20.232 ;
    END
  END r_q[79]
  PIN r_q[7]
    DIRECTION OUTPUT ;
    USE SIGNAL ;
    PORT
      LAYER M4 ;
        RECT  0 22.512 0.084 22.536 ;
    END
  END r_q[7]
  PIN r_q[80]
    DIRECTION OUTPUT ;
    USE SIGNAL ;
    PORT
      LAYER M4 ;
        RECT  0 20.304 0.084 20.328 ;
    END
  END r_q[80]
  PIN r_q[81]
    DIRECTION OUTPUT ;
    USE SIGNAL ;
    PORT
      LAYER M4 ;
        RECT  0 14.256 0.084 14.28 ;
    END
  END r_q[81]
  PIN r_q[82]
    DIRECTION OUTPUT ;
    USE SIGNAL ;
    PORT
      LAYER M4 ;
        RECT  0 14.352 0.084 14.376 ;
    END
  END r_q[82]
  PIN r_q[83]
    DIRECTION OUTPUT ;
    USE SIGNAL ;
    PORT
      LAYER M4 ;
        RECT  0 14.448 0.084 14.472 ;
    END
  END r_q[83]
  PIN r_q[84]
    DIRECTION OUTPUT ;
    USE SIGNAL ;
    PORT
      LAYER M4 ;
        RECT  0 14.544 0.084 14.568 ;
    END
  END r_q[84]
  PIN r_q[85]
    DIRECTION OUTPUT ;
    USE SIGNAL ;
    PORT
      LAYER M4 ;
        RECT  0 14.64 0.084 14.664 ;
    END
  END r_q[85]
  PIN r_q[86]
    DIRECTION OUTPUT ;
    USE SIGNAL ;
    PORT
      LAYER M4 ;
        RECT  0 14.736 0.084 14.76 ;
    END
  END r_q[86]
  PIN r_q[87]
    DIRECTION OUTPUT ;
    USE SIGNAL ;
    PORT
      LAYER M4 ;
        RECT  0 14.832 0.084 14.856 ;
    END
  END r_q[87]
  PIN r_q[88]
    DIRECTION OUTPUT ;
    USE SIGNAL ;
    PORT
      LAYER M4 ;
        RECT  0 14.928 0.084 14.952 ;
    END
  END r_q[88]
  PIN r_q[89]
    DIRECTION OUTPUT ;
    USE SIGNAL ;
    PORT
      LAYER M4 ;
        RECT  0 15.024 0.084 15.048 ;
    END
  END r_q[89]
  PIN r_q[8]
    DIRECTION OUTPUT ;
    USE SIGNAL ;
    PORT
      LAYER M4 ;
        RECT  0 22.608 0.084 22.632 ;
    END
  END r_q[8]
  PIN r_q[90]
    DIRECTION OUTPUT ;
    USE SIGNAL ;
    PORT
      LAYER M4 ;
        RECT  0 15.12 0.084 15.144 ;
    END
  END r_q[90]
  PIN r_q[91]
    DIRECTION OUTPUT ;
    USE SIGNAL ;
    PORT
      LAYER M4 ;
        RECT  0 15.216 0.084 15.24 ;
    END
  END r_q[91]
  PIN r_q[92]
    DIRECTION OUTPUT ;
    USE SIGNAL ;
    PORT
      LAYER M4 ;
        RECT  0 15.312 0.084 15.336 ;
    END
  END r_q[92]
  PIN r_q[93]
    DIRECTION OUTPUT ;
    USE SIGNAL ;
    PORT
      LAYER M4 ;
        RECT  0 15.408 0.084 15.432 ;
    END
  END r_q[93]
  PIN r_q[94]
    DIRECTION OUTPUT ;
    USE SIGNAL ;
    PORT
      LAYER M4 ;
        RECT  0 15.504 0.084 15.528 ;
    END
  END r_q[94]
  PIN r_q[95]
    DIRECTION OUTPUT ;
    USE SIGNAL ;
    PORT
      LAYER M4 ;
        RECT  0 15.6 0.084 15.624 ;
    END
  END r_q[95]
  PIN r_q[96]
    DIRECTION OUTPUT ;
    USE SIGNAL ;
    PORT
      LAYER M4 ;
        RECT  0 15.696 0.084 15.72 ;
    END
  END r_q[96]
  PIN r_q[97]
    DIRECTION OUTPUT ;
    USE SIGNAL ;
    PORT
      LAYER M4 ;
        RECT  0 15.792 0.084 15.816 ;
    END
  END r_q[97]
  PIN r_q[98]
    DIRECTION OUTPUT ;
    USE SIGNAL ;
    PORT
      LAYER M4 ;
        RECT  0 15.888 0.084 15.912 ;
    END
  END r_q[98]
  PIN r_q[99]
    DIRECTION OUTPUT ;
    USE SIGNAL ;
    PORT
      LAYER M4 ;
        RECT  0 15.984 0.084 16.008 ;
    END
  END r_q[99]
  PIN r_q[9]
    DIRECTION OUTPUT ;
    USE SIGNAL ;
    PORT
      LAYER M4 ;
        RECT  0 22.704 0.084 22.728 ;
    END
  END r_q[9]
  PIN rst_n
    DIRECTION INPUT ;
    USE SIGNAL ;
    PORT
      LAYER M4 ;
        RECT  0 54.096 0.084 54.12 ;
    END
  END rst_n
  PIN VSS
    DIRECTION INOUT ;
    USE GROUND ;
    PORT
      LAYER M5 ;
        RECT  169.8 2.137 169.92 108.023 ;
        RECT  164.4 2.137 164.52 108.023 ;
        RECT  159 2.137 159.12 108.023 ;
        RECT  153.6 2.137 153.72 108.023 ;
        RECT  148.2 2.137 148.32 108.023 ;
        RECT  142.8 2.137 142.92 108.023 ;
        RECT  137.4 2.137 137.52 108.023 ;
        RECT  132 2.137 132.12 108.023 ;
        RECT  126.6 2.137 126.72 108.023 ;
        RECT  121.2 2.137 121.32 108.023 ;
        RECT  115.8 2.137 115.92 108.023 ;
        RECT  110.4 2.137 110.52 108.023 ;
        RECT  105 2.137 105.12 108.023 ;
        RECT  99.6 2.137 99.72 108.023 ;
        RECT  94.2 2.137 94.32 108.023 ;
        RECT  88.8 2.137 88.92 108.023 ;
        RECT  83.4 2.137 83.52 108.023 ;
        RECT  78 2.137 78.12 108.023 ;
        RECT  72.6 2.137 72.72 108.023 ;
        RECT  67.2 2.137 67.32 108.023 ;
        RECT  61.8 2.137 61.92 108.023 ;
        RECT  56.4 2.137 56.52 108.023 ;
        RECT  51 2.137 51.12 108.023 ;
        RECT  45.6 2.137 45.72 108.023 ;
        RECT  40.2 2.137 40.32 108.023 ;
        RECT  34.8 2.137 34.92 108.023 ;
        RECT  29.4 2.137 29.52 108.023 ;
        RECT  24 2.137 24.12 108.023 ;
        RECT  18.6 2.137 18.72 108.023 ;
        RECT  13.2 2.137 13.32 108.023 ;
        RECT  7.8 2.137 7.92 108.023 ;
        RECT  2.4 2.137 2.52 108.023 ;
    END
  END VSS
  PIN VDD
    DIRECTION INOUT ;
    USE POWER ;
    PORT
      LAYER M5 ;
        RECT  169.992 2.151 170.112 108.009 ;
        RECT  164.592 2.151 164.712 108.009 ;
        RECT  159.192 2.151 159.312 108.009 ;
        RECT  153.792 2.151 153.912 108.009 ;
        RECT  148.392 2.151 148.512 108.009 ;
        RECT  142.992 2.151 143.112 108.009 ;
        RECT  137.592 2.151 137.712 108.009 ;
        RECT  132.192 2.151 132.312 108.009 ;
        RECT  126.792 2.151 126.912 108.009 ;
        RECT  121.392 2.151 121.512 108.009 ;
        RECT  115.992 2.151 116.112 108.009 ;
        RECT  110.592 2.151 110.712 108.009 ;
        RECT  105.192 2.151 105.312 108.009 ;
        RECT  99.792 2.151 99.912 108.009 ;
        RECT  94.392 2.151 94.512 108.009 ;
        RECT  88.992 2.151 89.112 108.009 ;
        RECT  83.592 2.151 83.712 108.009 ;
        RECT  78.192 2.151 78.312 108.009 ;
        RECT  72.792 2.151 72.912 108.009 ;
        RECT  67.392 2.151 67.512 108.009 ;
        RECT  61.992 2.151 62.112 108.009 ;
        RECT  56.592 2.151 56.712 108.009 ;
        RECT  51.192 2.151 51.312 108.009 ;
        RECT  45.792 2.151 45.912 108.009 ;
        RECT  40.392 2.151 40.512 108.009 ;
        RECT  34.992 2.151 35.112 108.009 ;
        RECT  29.592 2.151 29.712 108.009 ;
        RECT  24.192 2.151 24.312 108.009 ;
        RECT  18.792 2.151 18.912 108.009 ;
        RECT  13.392 2.151 13.512 108.009 ;
        RECT  7.992 2.151 8.112 108.009 ;
        RECT  2.592 2.151 2.712 108.009 ;
    END
  END VDD
  OBS
    LAYER RVTN ;
     RECT  2.16 2.16 170.64 2.295 ;
     RECT  2.16 2.565 170.64 2.835 ;
     RECT  2.16 3.105 170.64 3.375 ;
     RECT  2.16 3.645 170.64 3.915 ;
     RECT  2.16 4.185 170.64 4.455 ;
     RECT  2.16 4.725 170.64 4.995 ;
     RECT  2.16 5.265 170.64 5.535 ;
     RECT  2.16 5.805 170.64 6.075 ;
     RECT  2.16 6.345 170.64 6.615 ;
     RECT  2.16 6.885 170.64 7.155 ;
     RECT  2.16 7.425 170.64 7.695 ;
     RECT  2.16 7.965 170.64 8.235 ;
     RECT  2.16 8.505 170.64 8.775 ;
     RECT  2.16 9.045 170.64 9.315 ;
     RECT  2.16 9.585 170.64 9.855 ;
     RECT  2.16 10.125 170.64 10.395 ;
     RECT  2.16 10.665 170.64 10.935 ;
     RECT  2.16 11.205 170.64 11.475 ;
     RECT  2.16 11.745 170.64 12.015 ;
     RECT  2.16 12.285 170.64 12.555 ;
     RECT  2.16 12.825 170.64 13.095 ;
     RECT  2.16 13.365 170.64 13.635 ;
     RECT  2.16 13.905 170.64 14.175 ;
     RECT  2.16 14.445 170.64 14.715 ;
     RECT  2.16 14.985 170.64 15.255 ;
     RECT  2.16 15.525 170.64 15.795 ;
     RECT  2.16 16.065 170.64 16.335 ;
     RECT  2.16 16.605 170.64 16.875 ;
     RECT  2.16 17.145 170.64 17.415 ;
     RECT  2.16 17.685 170.64 17.955 ;
     RECT  2.16 18.225 170.64 18.495 ;
     RECT  2.16 18.765 170.64 19.035 ;
     RECT  2.16 19.305 170.64 19.575 ;
     RECT  2.16 19.845 170.64 20.115 ;
     RECT  2.16 20.385 170.64 20.655 ;
     RECT  2.16 20.925 170.64 21.195 ;
     RECT  2.16 21.465 170.64 21.6 ;
     RECT  2.16 21.6 23.436 21.735 ;
     RECT  149.364 21.6 170.64 21.735 ;
     RECT  2.16 22.005 23.436 22.275 ;
     RECT  149.364 22.005 170.64 22.275 ;
     RECT  2.16 22.545 23.436 22.815 ;
     RECT  149.364 22.545 170.64 22.815 ;
     RECT  2.16 23.085 23.436 23.355 ;
     RECT  149.364 23.085 170.64 23.355 ;
     RECT  2.16 23.625 23.436 23.895 ;
     RECT  149.364 23.625 170.64 23.895 ;
     RECT  2.16 24.165 23.436 24.435 ;
     RECT  149.364 24.165 170.64 24.435 ;
     RECT  2.16 24.705 23.436 24.975 ;
     RECT  149.364 24.705 170.64 24.975 ;
     RECT  2.16 25.245 23.436 25.515 ;
     RECT  149.364 25.245 170.64 25.515 ;
     RECT  2.16 25.785 23.436 26.055 ;
     RECT  149.364 25.785 170.64 26.055 ;
     RECT  2.16 26.325 23.436 26.595 ;
     RECT  149.364 26.325 170.64 26.595 ;
     RECT  2.16 26.865 23.436 27.135 ;
     RECT  149.364 26.865 170.64 27.135 ;
     RECT  2.16 27.405 23.436 27.675 ;
     RECT  149.364 27.405 170.64 27.675 ;
     RECT  2.16 27.945 23.436 28.215 ;
     RECT  149.364 27.945 170.64 28.215 ;
     RECT  2.16 28.485 23.436 28.755 ;
     RECT  149.364 28.485 170.64 28.755 ;
     RECT  2.16 29.025 23.436 29.295 ;
     RECT  149.364 29.025 170.64 29.295 ;
     RECT  2.16 29.565 23.436 29.835 ;
     RECT  149.364 29.565 170.64 29.835 ;
     RECT  2.16 30.105 23.436 30.375 ;
     RECT  149.364 30.105 170.64 30.375 ;
     RECT  2.16 30.645 23.436 30.915 ;
     RECT  149.364 30.645 170.64 30.915 ;
     RECT  2.16 31.185 23.436 31.455 ;
     RECT  149.364 31.185 170.64 31.455 ;
     RECT  2.16 31.725 23.436 31.995 ;
     RECT  149.364 31.725 170.64 31.995 ;
     RECT  2.16 32.265 23.436 32.535 ;
     RECT  149.364 32.265 170.64 32.535 ;
     RECT  2.16 32.805 23.436 33.075 ;
     RECT  149.364 32.805 170.64 33.075 ;
     RECT  2.16 33.345 23.436 33.615 ;
     RECT  149.364 33.345 170.64 33.615 ;
     RECT  2.16 33.885 23.436 34.155 ;
     RECT  149.364 33.885 170.64 34.155 ;
     RECT  2.16 34.425 23.436 34.695 ;
     RECT  149.364 34.425 170.64 34.695 ;
     RECT  2.16 34.965 23.436 35.235 ;
     RECT  149.364 34.965 170.64 35.235 ;
     RECT  2.16 35.505 23.436 35.775 ;
     RECT  149.364 35.505 170.64 35.775 ;
     RECT  2.16 36.045 23.436 36.315 ;
     RECT  149.364 36.045 170.64 36.315 ;
     RECT  2.16 36.585 23.436 36.855 ;
     RECT  149.364 36.585 170.64 36.855 ;
     RECT  2.16 37.125 23.436 37.395 ;
     RECT  149.364 37.125 170.64 37.395 ;
     RECT  2.16 37.665 23.436 37.935 ;
     RECT  149.364 37.665 170.64 37.935 ;
     RECT  2.16 38.205 23.436 38.475 ;
     RECT  149.364 38.205 170.64 38.475 ;
     RECT  2.16 38.745 23.436 39.015 ;
     RECT  149.364 38.745 170.64 39.015 ;
     RECT  2.16 39.285 23.436 39.555 ;
     RECT  149.364 39.285 170.64 39.555 ;
     RECT  2.16 39.825 23.436 40.095 ;
     RECT  149.364 39.825 170.64 40.095 ;
     RECT  2.16 40.365 23.436 40.635 ;
     RECT  149.364 40.365 170.64 40.635 ;
     RECT  2.16 40.905 23.436 41.175 ;
     RECT  149.364 40.905 170.64 41.175 ;
     RECT  2.16 41.445 23.436 41.715 ;
     RECT  149.364 41.445 170.64 41.715 ;
     RECT  2.16 41.985 23.436 42.255 ;
     RECT  149.364 41.985 170.64 42.255 ;
     RECT  2.16 42.525 23.436 42.795 ;
     RECT  149.364 42.525 170.64 42.795 ;
     RECT  2.16 43.065 23.436 43.335 ;
     RECT  149.364 43.065 170.64 43.335 ;
     RECT  2.16 43.605 23.436 43.875 ;
     RECT  149.364 43.605 170.64 43.875 ;
     RECT  2.16 44.145 23.436 44.415 ;
     RECT  149.364 44.145 170.64 44.415 ;
     RECT  2.16 44.685 23.436 44.955 ;
     RECT  149.364 44.685 170.64 44.955 ;
     RECT  2.16 45.225 23.436 45.495 ;
     RECT  149.364 45.225 170.64 45.495 ;
     RECT  2.16 45.765 23.436 46.035 ;
     RECT  149.364 45.765 170.64 46.035 ;
     RECT  2.16 46.305 23.436 46.575 ;
     RECT  149.364 46.305 170.64 46.575 ;
     RECT  2.16 46.845 23.436 47.115 ;
     RECT  149.364 46.845 170.64 47.115 ;
     RECT  2.16 47.385 23.436 47.655 ;
     RECT  149.364 47.385 170.64 47.655 ;
     RECT  2.16 47.925 23.436 48.195 ;
     RECT  149.364 47.925 170.64 48.195 ;
     RECT  2.16 48.465 23.436 48.735 ;
     RECT  149.364 48.465 170.64 48.735 ;
     RECT  2.16 49.005 23.436 49.275 ;
     RECT  149.364 49.005 170.64 49.275 ;
     RECT  2.16 49.545 23.436 49.815 ;
     RECT  149.364 49.545 170.64 49.815 ;
     RECT  2.16 50.085 23.436 50.355 ;
     RECT  149.364 50.085 170.64 50.355 ;
     RECT  2.16 50.625 23.436 50.895 ;
     RECT  149.364 50.625 170.64 50.895 ;
     RECT  2.16 51.165 23.436 51.435 ;
     RECT  149.364 51.165 170.64 51.435 ;
     RECT  2.16 51.705 23.436 51.975 ;
     RECT  149.364 51.705 170.64 51.975 ;
     RECT  2.16 52.245 23.436 52.515 ;
     RECT  149.364 52.245 170.64 52.515 ;
     RECT  2.16 52.785 23.436 53.055 ;
     RECT  149.364 52.785 170.64 53.055 ;
     RECT  2.16 53.325 23.436 53.595 ;
     RECT  149.364 53.325 170.64 53.595 ;
     RECT  2.16 53.865 23.436 54.135 ;
     RECT  149.364 53.865 170.64 54.135 ;
     RECT  2.16 54.405 23.436 54.675 ;
     RECT  149.364 54.405 170.64 54.675 ;
     RECT  2.16 54.945 23.436 55.215 ;
     RECT  149.364 54.945 170.64 55.215 ;
     RECT  2.16 55.485 23.436 55.755 ;
     RECT  149.364 55.485 170.64 55.755 ;
     RECT  2.16 56.025 23.436 56.295 ;
     RECT  149.364 56.025 170.64 56.295 ;
     RECT  2.16 56.565 23.436 56.835 ;
     RECT  149.364 56.565 170.64 56.835 ;
     RECT  2.16 57.105 23.436 57.375 ;
     RECT  149.364 57.105 170.64 57.375 ;
     RECT  2.16 57.645 23.436 57.915 ;
     RECT  149.364 57.645 170.64 57.915 ;
     RECT  2.16 58.185 23.436 58.455 ;
     RECT  149.364 58.185 170.64 58.455 ;
     RECT  2.16 58.725 23.436 58.995 ;
     RECT  149.364 58.725 170.64 58.995 ;
     RECT  2.16 59.265 23.436 59.535 ;
     RECT  149.364 59.265 170.64 59.535 ;
     RECT  2.16 59.805 23.436 60.075 ;
     RECT  149.364 59.805 170.64 60.075 ;
     RECT  2.16 60.345 23.436 60.615 ;
     RECT  149.364 60.345 170.64 60.615 ;
     RECT  2.16 60.885 23.436 61.155 ;
     RECT  149.364 60.885 170.64 61.155 ;
     RECT  2.16 61.425 23.436 61.695 ;
     RECT  149.364 61.425 170.64 61.695 ;
     RECT  2.16 61.965 23.436 62.235 ;
     RECT  149.364 61.965 170.64 62.235 ;
     RECT  2.16 62.505 23.436 62.775 ;
     RECT  149.364 62.505 170.64 62.775 ;
     RECT  2.16 63.045 23.436 63.315 ;
     RECT  149.364 63.045 170.64 63.315 ;
     RECT  2.16 63.585 23.436 63.855 ;
     RECT  149.364 63.585 170.64 63.855 ;
     RECT  2.16 64.125 23.436 64.395 ;
     RECT  149.364 64.125 170.64 64.395 ;
     RECT  2.16 64.665 23.436 64.935 ;
     RECT  149.364 64.665 170.64 64.935 ;
     RECT  2.16 65.205 23.436 65.475 ;
     RECT  149.364 65.205 170.64 65.475 ;
     RECT  2.16 65.745 23.436 66.015 ;
     RECT  149.364 65.745 170.64 66.015 ;
     RECT  2.16 66.285 23.436 66.555 ;
     RECT  149.364 66.285 170.64 66.555 ;
     RECT  2.16 66.825 23.436 67.095 ;
     RECT  149.364 66.825 170.64 67.095 ;
     RECT  2.16 67.365 23.436 67.635 ;
     RECT  149.364 67.365 170.64 67.635 ;
     RECT  2.16 67.905 23.436 68.175 ;
     RECT  149.364 67.905 170.64 68.175 ;
     RECT  2.16 68.445 23.436 68.715 ;
     RECT  149.364 68.445 170.64 68.715 ;
     RECT  2.16 68.985 23.436 69.255 ;
     RECT  149.364 68.985 170.64 69.255 ;
     RECT  2.16 69.525 23.436 69.795 ;
     RECT  149.364 69.525 170.64 69.795 ;
     RECT  2.16 70.065 23.436 70.335 ;
     RECT  149.364 70.065 170.64 70.335 ;
     RECT  2.16 70.605 23.436 70.875 ;
     RECT  149.364 70.605 170.64 70.875 ;
     RECT  2.16 71.145 23.436 71.415 ;
     RECT  149.364 71.145 170.64 71.415 ;
     RECT  2.16 71.685 23.436 71.955 ;
     RECT  149.364 71.685 170.64 71.955 ;
     RECT  2.16 72.225 23.436 72.495 ;
     RECT  149.364 72.225 170.64 72.495 ;
     RECT  2.16 72.765 23.436 73.035 ;
     RECT  149.364 72.765 170.64 73.035 ;
     RECT  2.16 73.305 23.436 73.575 ;
     RECT  149.364 73.305 170.64 73.575 ;
     RECT  2.16 73.845 23.436 74.115 ;
     RECT  149.364 73.845 170.64 74.115 ;
     RECT  2.16 74.385 23.436 74.655 ;
     RECT  149.364 74.385 170.64 74.655 ;
     RECT  2.16 74.925 23.436 75.195 ;
     RECT  149.364 74.925 170.64 75.195 ;
     RECT  2.16 75.465 23.436 75.735 ;
     RECT  149.364 75.465 170.64 75.735 ;
     RECT  2.16 76.005 23.436 76.275 ;
     RECT  149.364 76.005 170.64 76.275 ;
     RECT  2.16 76.545 23.436 76.815 ;
     RECT  149.364 76.545 170.64 76.815 ;
     RECT  2.16 77.085 23.436 77.355 ;
     RECT  149.364 77.085 170.64 77.355 ;
     RECT  2.16 77.625 23.436 77.895 ;
     RECT  149.364 77.625 170.64 77.895 ;
     RECT  2.16 78.165 23.436 78.435 ;
     RECT  149.364 78.165 170.64 78.435 ;
     RECT  2.16 78.705 23.436 78.975 ;
     RECT  149.364 78.705 170.64 78.975 ;
     RECT  2.16 79.245 23.436 79.515 ;
     RECT  149.364 79.245 170.64 79.515 ;
     RECT  2.16 79.785 23.436 80.055 ;
     RECT  149.364 79.785 170.64 80.055 ;
     RECT  2.16 80.325 23.436 80.595 ;
     RECT  149.364 80.325 170.64 80.595 ;
     RECT  2.16 80.865 23.436 81.135 ;
     RECT  149.364 80.865 170.64 81.135 ;
     RECT  2.16 81.405 23.436 81.675 ;
     RECT  149.364 81.405 170.64 81.675 ;
     RECT  2.16 81.945 23.436 82.215 ;
     RECT  149.364 81.945 170.64 82.215 ;
     RECT  2.16 82.485 23.436 82.755 ;
     RECT  149.364 82.485 170.64 82.755 ;
     RECT  2.16 83.025 23.436 83.295 ;
     RECT  149.364 83.025 170.64 83.295 ;
     RECT  2.16 83.565 23.436 83.835 ;
     RECT  149.364 83.565 170.64 83.835 ;
     RECT  2.16 84.105 23.436 84.375 ;
     RECT  149.364 84.105 170.64 84.375 ;
     RECT  2.16 84.645 23.436 84.915 ;
     RECT  149.364 84.645 170.64 84.915 ;
     RECT  2.16 85.185 23.436 85.455 ;
     RECT  149.364 85.185 170.64 85.455 ;
     RECT  2.16 85.725 23.436 85.995 ;
     RECT  149.364 85.725 170.64 85.995 ;
     RECT  2.16 86.265 23.436 86.535 ;
     RECT  149.364 86.265 170.64 86.535 ;
     RECT  2.16 86.805 23.436 87.075 ;
     RECT  149.364 86.805 170.64 87.075 ;
     RECT  2.16 87.345 23.436 87.615 ;
     RECT  149.364 87.345 170.64 87.615 ;
     RECT  2.16 87.885 23.436 88.155 ;
     RECT  149.364 87.885 170.64 88.155 ;
     RECT  2.16 88.425 23.436 88.695 ;
     RECT  149.364 88.425 170.64 88.695 ;
     RECT  2.16 88.965 170.64 89.235 ;
     RECT  2.16 89.505 170.64 89.775 ;
     RECT  2.16 90.045 170.64 90.315 ;
     RECT  2.16 90.585 170.64 90.855 ;
     RECT  2.16 91.125 170.64 91.395 ;
     RECT  2.16 91.665 170.64 91.935 ;
     RECT  2.16 92.205 170.64 92.475 ;
     RECT  2.16 92.745 170.64 93.015 ;
     RECT  2.16 93.285 170.64 93.555 ;
     RECT  2.16 93.825 170.64 94.095 ;
     RECT  2.16 94.365 170.64 94.635 ;
     RECT  2.16 94.905 170.64 95.175 ;
     RECT  2.16 95.445 170.64 95.715 ;
     RECT  2.16 95.985 170.64 96.255 ;
     RECT  2.16 96.525 170.64 96.795 ;
     RECT  2.16 97.065 170.64 97.335 ;
     RECT  2.16 97.605 170.64 97.875 ;
     RECT  2.16 98.145 170.64 98.415 ;
     RECT  2.16 98.685 170.64 98.955 ;
     RECT  2.16 99.225 170.64 99.495 ;
     RECT  2.16 99.765 170.64 100.035 ;
     RECT  2.16 100.305 170.64 100.575 ;
     RECT  2.16 100.845 170.64 101.115 ;
     RECT  2.16 101.385 170.64 101.655 ;
     RECT  2.16 101.925 170.64 102.195 ;
     RECT  2.16 102.465 170.64 102.735 ;
     RECT  2.16 103.005 170.64 103.275 ;
     RECT  2.16 103.545 170.64 103.815 ;
     RECT  2.16 104.085 170.64 104.355 ;
     RECT  2.16 104.625 170.64 104.895 ;
     RECT  2.16 105.165 170.64 105.435 ;
     RECT  2.16 105.705 170.64 105.975 ;
     RECT  2.16 106.245 170.64 106.515 ;
     RECT  2.16 106.785 170.64 107.055 ;
     RECT  2.16 107.325 170.64 107.595 ;
     RECT  2.16 107.865 170.64 108 ;
    LAYER RVTP ;
     RECT  2.16 2.295 170.64 2.565 ;
     RECT  2.16 2.835 170.64 3.105 ;
     RECT  2.16 3.375 170.64 3.645 ;
     RECT  2.16 3.915 170.64 4.185 ;
     RECT  2.16 4.455 170.64 4.725 ;
     RECT  2.16 4.995 170.64 5.265 ;
     RECT  2.16 5.535 170.64 5.805 ;
     RECT  2.16 6.075 170.64 6.345 ;
     RECT  2.16 6.615 170.64 6.885 ;
     RECT  2.16 7.155 170.64 7.425 ;
     RECT  2.16 7.695 170.64 7.965 ;
     RECT  2.16 8.235 170.64 8.505 ;
     RECT  2.16 8.775 170.64 9.045 ;
     RECT  2.16 9.315 170.64 9.585 ;
     RECT  2.16 9.855 170.64 10.125 ;
     RECT  2.16 10.395 170.64 10.665 ;
     RECT  2.16 10.935 170.64 11.205 ;
     RECT  2.16 11.475 170.64 11.745 ;
     RECT  2.16 12.015 170.64 12.285 ;
     RECT  2.16 12.555 170.64 12.825 ;
     RECT  2.16 13.095 170.64 13.365 ;
     RECT  2.16 13.635 170.64 13.905 ;
     RECT  2.16 14.175 170.64 14.445 ;
     RECT  2.16 14.715 170.64 14.985 ;
     RECT  2.16 15.255 170.64 15.525 ;
     RECT  2.16 15.795 170.64 16.065 ;
     RECT  2.16 16.335 170.64 16.605 ;
     RECT  2.16 16.875 170.64 17.145 ;
     RECT  2.16 17.415 170.64 17.685 ;
     RECT  2.16 17.955 170.64 18.225 ;
     RECT  2.16 18.495 170.64 18.765 ;
     RECT  2.16 19.035 170.64 19.305 ;
     RECT  2.16 19.575 170.64 19.845 ;
     RECT  2.16 20.115 170.64 20.385 ;
     RECT  2.16 20.655 170.64 20.925 ;
     RECT  2.16 21.195 170.64 21.465 ;
     RECT  2.16 21.735 23.436 22.005 ;
     RECT  149.364 21.735 170.64 22.005 ;
     RECT  2.16 22.275 23.436 22.545 ;
     RECT  149.364 22.275 170.64 22.545 ;
     RECT  2.16 22.815 23.436 23.085 ;
     RECT  149.364 22.815 170.64 23.085 ;
     RECT  2.16 23.355 23.436 23.625 ;
     RECT  149.364 23.355 170.64 23.625 ;
     RECT  2.16 23.895 23.436 24.165 ;
     RECT  149.364 23.895 170.64 24.165 ;
     RECT  2.16 24.435 23.436 24.705 ;
     RECT  149.364 24.435 170.64 24.705 ;
     RECT  2.16 24.975 23.436 25.245 ;
     RECT  149.364 24.975 170.64 25.245 ;
     RECT  2.16 25.515 23.436 25.785 ;
     RECT  149.364 25.515 170.64 25.785 ;
     RECT  2.16 26.055 23.436 26.325 ;
     RECT  149.364 26.055 170.64 26.325 ;
     RECT  2.16 26.595 23.436 26.865 ;
     RECT  149.364 26.595 170.64 26.865 ;
     RECT  2.16 27.135 23.436 27.405 ;
     RECT  149.364 27.135 170.64 27.405 ;
     RECT  2.16 27.675 23.436 27.945 ;
     RECT  149.364 27.675 170.64 27.945 ;
     RECT  2.16 28.215 23.436 28.485 ;
     RECT  149.364 28.215 170.64 28.485 ;
     RECT  2.16 28.755 23.436 29.025 ;
     RECT  149.364 28.755 170.64 29.025 ;
     RECT  2.16 29.295 23.436 29.565 ;
     RECT  149.364 29.295 170.64 29.565 ;
     RECT  2.16 29.835 23.436 30.105 ;
     RECT  149.364 29.835 170.64 30.105 ;
     RECT  2.16 30.375 23.436 30.645 ;
     RECT  149.364 30.375 170.64 30.645 ;
     RECT  2.16 30.915 23.436 31.185 ;
     RECT  149.364 30.915 170.64 31.185 ;
     RECT  2.16 31.455 23.436 31.725 ;
     RECT  149.364 31.455 170.64 31.725 ;
     RECT  2.16 31.995 23.436 32.265 ;
     RECT  149.364 31.995 170.64 32.265 ;
     RECT  2.16 32.535 23.436 32.805 ;
     RECT  149.364 32.535 170.64 32.805 ;
     RECT  2.16 33.075 23.436 33.345 ;
     RECT  149.364 33.075 170.64 33.345 ;
     RECT  2.16 33.615 23.436 33.885 ;
     RECT  149.364 33.615 170.64 33.885 ;
     RECT  2.16 34.155 23.436 34.425 ;
     RECT  149.364 34.155 170.64 34.425 ;
     RECT  2.16 34.695 23.436 34.965 ;
     RECT  149.364 34.695 170.64 34.965 ;
     RECT  2.16 35.235 23.436 35.505 ;
     RECT  149.364 35.235 170.64 35.505 ;
     RECT  2.16 35.775 23.436 36.045 ;
     RECT  149.364 35.775 170.64 36.045 ;
     RECT  2.16 36.315 23.436 36.585 ;
     RECT  149.364 36.315 170.64 36.585 ;
     RECT  2.16 36.855 23.436 37.125 ;
     RECT  149.364 36.855 170.64 37.125 ;
     RECT  2.16 37.395 23.436 37.665 ;
     RECT  149.364 37.395 170.64 37.665 ;
     RECT  2.16 37.935 23.436 38.205 ;
     RECT  149.364 37.935 170.64 38.205 ;
     RECT  2.16 38.475 23.436 38.745 ;
     RECT  149.364 38.475 170.64 38.745 ;
     RECT  2.16 39.015 23.436 39.285 ;
     RECT  149.364 39.015 170.64 39.285 ;
     RECT  2.16 39.555 23.436 39.825 ;
     RECT  149.364 39.555 170.64 39.825 ;
     RECT  2.16 40.095 23.436 40.365 ;
     RECT  149.364 40.095 170.64 40.365 ;
     RECT  2.16 40.635 23.436 40.905 ;
     RECT  149.364 40.635 170.64 40.905 ;
     RECT  2.16 41.175 23.436 41.445 ;
     RECT  149.364 41.175 170.64 41.445 ;
     RECT  2.16 41.715 23.436 41.985 ;
     RECT  149.364 41.715 170.64 41.985 ;
     RECT  2.16 42.255 23.436 42.525 ;
     RECT  149.364 42.255 170.64 42.525 ;
     RECT  2.16 42.795 23.436 43.065 ;
     RECT  149.364 42.795 170.64 43.065 ;
     RECT  2.16 43.335 23.436 43.605 ;
     RECT  149.364 43.335 170.64 43.605 ;
     RECT  2.16 43.875 23.436 44.145 ;
     RECT  149.364 43.875 170.64 44.145 ;
     RECT  2.16 44.415 23.436 44.685 ;
     RECT  149.364 44.415 170.64 44.685 ;
     RECT  2.16 44.955 23.436 45.225 ;
     RECT  149.364 44.955 170.64 45.225 ;
     RECT  2.16 45.495 23.436 45.765 ;
     RECT  149.364 45.495 170.64 45.765 ;
     RECT  2.16 46.035 23.436 46.305 ;
     RECT  149.364 46.035 170.64 46.305 ;
     RECT  2.16 46.575 23.436 46.845 ;
     RECT  149.364 46.575 170.64 46.845 ;
     RECT  2.16 47.115 23.436 47.385 ;
     RECT  149.364 47.115 170.64 47.385 ;
     RECT  2.16 47.655 23.436 47.925 ;
     RECT  149.364 47.655 170.64 47.925 ;
     RECT  2.16 48.195 23.436 48.465 ;
     RECT  149.364 48.195 170.64 48.465 ;
     RECT  2.16 48.735 23.436 49.005 ;
     RECT  149.364 48.735 170.64 49.005 ;
     RECT  2.16 49.275 23.436 49.545 ;
     RECT  149.364 49.275 170.64 49.545 ;
     RECT  2.16 49.815 23.436 50.085 ;
     RECT  149.364 49.815 170.64 50.085 ;
     RECT  2.16 50.355 23.436 50.625 ;
     RECT  149.364 50.355 170.64 50.625 ;
     RECT  2.16 50.895 23.436 51.165 ;
     RECT  149.364 50.895 170.64 51.165 ;
     RECT  2.16 51.435 23.436 51.705 ;
     RECT  149.364 51.435 170.64 51.705 ;
     RECT  2.16 51.975 23.436 52.245 ;
     RECT  149.364 51.975 170.64 52.245 ;
     RECT  2.16 52.515 23.436 52.785 ;
     RECT  149.364 52.515 170.64 52.785 ;
     RECT  2.16 53.055 23.436 53.325 ;
     RECT  149.364 53.055 170.64 53.325 ;
     RECT  2.16 53.595 23.436 53.865 ;
     RECT  149.364 53.595 170.64 53.865 ;
     RECT  2.16 54.135 23.436 54.405 ;
     RECT  149.364 54.135 170.64 54.405 ;
     RECT  2.16 54.675 23.436 54.945 ;
     RECT  149.364 54.675 170.64 54.945 ;
     RECT  2.16 55.215 23.436 55.485 ;
     RECT  149.364 55.215 170.64 55.485 ;
     RECT  2.16 55.755 23.436 56.025 ;
     RECT  149.364 55.755 170.64 56.025 ;
     RECT  2.16 56.295 23.436 56.565 ;
     RECT  149.364 56.295 170.64 56.565 ;
     RECT  2.16 56.835 23.436 57.105 ;
     RECT  149.364 56.835 170.64 57.105 ;
     RECT  2.16 57.375 23.436 57.645 ;
     RECT  149.364 57.375 170.64 57.645 ;
     RECT  2.16 57.915 23.436 58.185 ;
     RECT  149.364 57.915 170.64 58.185 ;
     RECT  2.16 58.455 23.436 58.725 ;
     RECT  149.364 58.455 170.64 58.725 ;
     RECT  2.16 58.995 23.436 59.265 ;
     RECT  149.364 58.995 170.64 59.265 ;
     RECT  2.16 59.535 23.436 59.805 ;
     RECT  149.364 59.535 170.64 59.805 ;
     RECT  2.16 60.075 23.436 60.345 ;
     RECT  149.364 60.075 170.64 60.345 ;
     RECT  2.16 60.615 23.436 60.885 ;
     RECT  149.364 60.615 170.64 60.885 ;
     RECT  2.16 61.155 23.436 61.425 ;
     RECT  149.364 61.155 170.64 61.425 ;
     RECT  2.16 61.695 23.436 61.965 ;
     RECT  149.364 61.695 170.64 61.965 ;
     RECT  2.16 62.235 23.436 62.505 ;
     RECT  149.364 62.235 170.64 62.505 ;
     RECT  2.16 62.775 23.436 63.045 ;
     RECT  149.364 62.775 170.64 63.045 ;
     RECT  2.16 63.315 23.436 63.585 ;
     RECT  149.364 63.315 170.64 63.585 ;
     RECT  2.16 63.855 23.436 64.125 ;
     RECT  149.364 63.855 170.64 64.125 ;
     RECT  2.16 64.395 23.436 64.665 ;
     RECT  149.364 64.395 170.64 64.665 ;
     RECT  2.16 64.935 23.436 65.205 ;
     RECT  149.364 64.935 170.64 65.205 ;
     RECT  2.16 65.475 23.436 65.745 ;
     RECT  149.364 65.475 170.64 65.745 ;
     RECT  2.16 66.015 23.436 66.285 ;
     RECT  149.364 66.015 170.64 66.285 ;
     RECT  2.16 66.555 23.436 66.825 ;
     RECT  149.364 66.555 170.64 66.825 ;
     RECT  2.16 67.095 23.436 67.365 ;
     RECT  149.364 67.095 170.64 67.365 ;
     RECT  2.16 67.635 23.436 67.905 ;
     RECT  149.364 67.635 170.64 67.905 ;
     RECT  2.16 68.175 23.436 68.445 ;
     RECT  149.364 68.175 170.64 68.445 ;
     RECT  2.16 68.715 23.436 68.985 ;
     RECT  149.364 68.715 170.64 68.985 ;
     RECT  2.16 69.255 23.436 69.525 ;
     RECT  149.364 69.255 170.64 69.525 ;
     RECT  2.16 69.795 23.436 70.065 ;
     RECT  149.364 69.795 170.64 70.065 ;
     RECT  2.16 70.335 23.436 70.605 ;
     RECT  149.364 70.335 170.64 70.605 ;
     RECT  2.16 70.875 23.436 71.145 ;
     RECT  149.364 70.875 170.64 71.145 ;
     RECT  2.16 71.415 23.436 71.685 ;
     RECT  149.364 71.415 170.64 71.685 ;
     RECT  2.16 71.955 23.436 72.225 ;
     RECT  149.364 71.955 170.64 72.225 ;
     RECT  2.16 72.495 23.436 72.765 ;
     RECT  149.364 72.495 170.64 72.765 ;
     RECT  2.16 73.035 23.436 73.305 ;
     RECT  149.364 73.035 170.64 73.305 ;
     RECT  2.16 73.575 23.436 73.845 ;
     RECT  149.364 73.575 170.64 73.845 ;
     RECT  2.16 74.115 23.436 74.385 ;
     RECT  149.364 74.115 170.64 74.385 ;
     RECT  2.16 74.655 23.436 74.925 ;
     RECT  149.364 74.655 170.64 74.925 ;
     RECT  2.16 75.195 23.436 75.465 ;
     RECT  149.364 75.195 170.64 75.465 ;
     RECT  2.16 75.735 23.436 76.005 ;
     RECT  149.364 75.735 170.64 76.005 ;
     RECT  2.16 76.275 23.436 76.545 ;
     RECT  149.364 76.275 170.64 76.545 ;
     RECT  2.16 76.815 23.436 77.085 ;
     RECT  149.364 76.815 170.64 77.085 ;
     RECT  2.16 77.355 23.436 77.625 ;
     RECT  149.364 77.355 170.64 77.625 ;
     RECT  2.16 77.895 23.436 78.165 ;
     RECT  149.364 77.895 170.64 78.165 ;
     RECT  2.16 78.435 23.436 78.705 ;
     RECT  149.364 78.435 170.64 78.705 ;
     RECT  2.16 78.975 23.436 79.245 ;
     RECT  149.364 78.975 170.64 79.245 ;
     RECT  2.16 79.515 23.436 79.785 ;
     RECT  149.364 79.515 170.64 79.785 ;
     RECT  2.16 80.055 23.436 80.325 ;
     RECT  149.364 80.055 170.64 80.325 ;
     RECT  2.16 80.595 23.436 80.865 ;
     RECT  149.364 80.595 170.64 80.865 ;
     RECT  2.16 81.135 23.436 81.405 ;
     RECT  149.364 81.135 170.64 81.405 ;
     RECT  2.16 81.675 23.436 81.945 ;
     RECT  149.364 81.675 170.64 81.945 ;
     RECT  2.16 82.215 23.436 82.485 ;
     RECT  149.364 82.215 170.64 82.485 ;
     RECT  2.16 82.755 23.436 83.025 ;
     RECT  149.364 82.755 170.64 83.025 ;
     RECT  2.16 83.295 23.436 83.565 ;
     RECT  149.364 83.295 170.64 83.565 ;
     RECT  2.16 83.835 23.436 84.105 ;
     RECT  149.364 83.835 170.64 84.105 ;
     RECT  2.16 84.375 23.436 84.645 ;
     RECT  149.364 84.375 170.64 84.645 ;
     RECT  2.16 84.915 23.436 85.185 ;
     RECT  149.364 84.915 170.64 85.185 ;
     RECT  2.16 85.455 23.436 85.725 ;
     RECT  149.364 85.455 170.64 85.725 ;
     RECT  2.16 85.995 23.436 86.265 ;
     RECT  149.364 85.995 170.64 86.265 ;
     RECT  2.16 86.535 23.436 86.805 ;
     RECT  149.364 86.535 170.64 86.805 ;
     RECT  2.16 87.075 23.436 87.345 ;
     RECT  149.364 87.075 170.64 87.345 ;
     RECT  2.16 87.615 23.436 87.885 ;
     RECT  149.364 87.615 170.64 87.885 ;
     RECT  2.16 88.155 23.436 88.425 ;
     RECT  149.364 88.155 170.64 88.425 ;
     RECT  2.16 88.695 23.436 88.83 ;
     RECT  149.364 88.695 170.64 88.83 ;
     RECT  2.16 88.83 170.64 88.965 ;
     RECT  2.16 89.235 170.64 89.505 ;
     RECT  2.16 89.775 170.64 90.045 ;
     RECT  2.16 90.315 170.64 90.585 ;
     RECT  2.16 90.855 170.64 91.125 ;
     RECT  2.16 91.395 170.64 91.665 ;
     RECT  2.16 91.935 170.64 92.205 ;
     RECT  2.16 92.475 170.64 92.745 ;
     RECT  2.16 93.015 170.64 93.285 ;
     RECT  2.16 93.555 170.64 93.825 ;
     RECT  2.16 94.095 170.64 94.365 ;
     RECT  2.16 94.635 170.64 94.905 ;
     RECT  2.16 95.175 170.64 95.445 ;
     RECT  2.16 95.715 170.64 95.985 ;
     RECT  2.16 96.255 170.64 96.525 ;
     RECT  2.16 96.795 170.64 97.065 ;
     RECT  2.16 97.335 170.64 97.605 ;
     RECT  2.16 97.875 170.64 98.145 ;
     RECT  2.16 98.415 170.64 98.685 ;
     RECT  2.16 98.955 170.64 99.225 ;
     RECT  2.16 99.495 170.64 99.765 ;
     RECT  2.16 100.035 170.64 100.305 ;
     RECT  2.16 100.575 170.64 100.845 ;
     RECT  2.16 101.115 170.64 101.385 ;
     RECT  2.16 101.655 170.64 101.925 ;
     RECT  2.16 102.195 170.64 102.465 ;
     RECT  2.16 102.735 170.64 103.005 ;
     RECT  2.16 103.275 170.64 103.545 ;
     RECT  2.16 103.815 170.64 104.085 ;
     RECT  2.16 104.355 170.64 104.625 ;
     RECT  2.16 104.895 170.64 105.165 ;
     RECT  2.16 105.435 170.64 105.705 ;
     RECT  2.16 105.975 170.64 106.245 ;
     RECT  2.16 106.515 170.64 106.785 ;
     RECT  2.16 107.055 170.64 107.325 ;
     RECT  2.16 107.595 170.64 107.865 ;
    LAYER M1 ;
     RECT  2.16 2.151 170.64 21.609 ;
     RECT  25.488 23.76 147.312 86.67 ;
     RECT  2.16 21.609 23.436 88.821 ;
     RECT  149.364 21.609 170.64 88.821 ;
     RECT  2.16 88.821 170.64 108.009 ;
    LAYER M2 ;
     RECT  0.067 4.356 0.103 4.374 ;
     RECT  0.103 9.36 0.139 9.378 ;
     RECT  0.103 14.616 0.139 15.318 ;
     RECT  0.103 18.846 0.139 20.178 ;
     RECT  0.103 26.64 0.139 26.658 ;
     RECT  0.103 33.93 0.139 34.686 ;
     RECT  0.103 35.901 0.139 35.919 ;
     RECT  0.103 38.826 0.139 38.844 ;
     RECT  0.103 47.394 0.139 47.718 ;
     RECT  0.103 49.212 0.139 49.23 ;
     RECT  0.067 1.341 0.167 1.359 ;
     RECT  0.067 53.91 0.167 53.928 ;
     RECT  0.103 42.381 0.175 44.334 ;
     RECT  0.103 45.198 0.175 45.909 ;
     RECT  0.103 8.01 0.203 8.028 ;
     RECT  0.139 18.846 0.203 20.988 ;
     RECT  0.103 28.071 0.203 28.548 ;
     RECT  0.103 31.158 0.203 31.176 ;
     RECT  0.139 33.93 0.203 34.92 ;
     RECT  0.175 42.381 0.203 45.909 ;
     RECT  0.203 34.506 0.211 34.92 ;
     RECT  0.139 35.901 0.211 36.144 ;
     RECT  0.139 49.131 0.211 49.23 ;
     RECT  0.139 14.454 0.239 16.02 ;
     RECT  0.139 26.64 0.239 26.694 ;
     RECT  0.203 28.071 0.239 28.206 ;
     RECT  0.211 34.506 0.239 36.144 ;
     RECT  0.139 38.826 0.239 39.114 ;
     RECT  0.139 47.088 0.239 47.718 ;
     RECT  0.031 54.684 0.239 55.044 ;
     RECT  0.239 14.454 0.311 15.318 ;
     RECT  0.211 49.131 0.311 49.536 ;
     RECT  0.239 26.64 0.319 26.658 ;
     RECT  0.211 31.086 0.319 31.104 ;
     RECT  0.103 40.644 0.319 40.662 ;
     RECT  0.103 3.384 0.347 3.402 ;
     RECT  0.139 8.784 0.347 9.378 ;
     RECT  0.319 26.136 0.347 26.658 ;
     RECT  0.103 37.566 0.347 37.962 ;
     RECT  0.319 40.176 0.347 40.662 ;
     RECT  0.203 42.381 0.347 42.588 ;
     RECT  0.203 43.506 0.347 45.486 ;
     RECT  0.311 49.131 0.347 49.23 ;
     RECT  0.283 6.354 0.383 6.372 ;
     RECT  0.203 18.846 0.383 18.99 ;
     RECT  0.347 42.462 0.383 42.588 ;
     RECT  0.347 43.506 0.383 45.216 ;
     RECT  0.347 26.136 0.419 26.154 ;
     RECT  0.319 30.456 0.419 31.104 ;
     RECT  0.347 40.176 0.419 40.356 ;
     RECT  0.383 42.57 0.419 42.588 ;
     RECT  0.239 47.394 0.535 47.718 ;
     RECT  0.463 2.916 0.563 3.024 ;
     RECT  0.103 52.416 0.571 52.434 ;
     RECT  0.103 32.508 0.599 32.526 ;
     RECT  0.347 49.212 0.599 49.23 ;
     RECT  0.311 14.454 0.823 14.634 ;
     RECT  0.103 29.466 0.823 29.484 ;
     RECT  0.535 47.394 0.823 47.754 ;
     RECT  0.563 3.006 1.147 3.024 ;
     RECT  0.347 9.288 1.147 9.306 ;
     RECT  0.103 12.528 1.147 12.546 ;
     RECT  0.535 17.964 1.147 17.982 ;
     RECT  0.383 18.846 1.147 18.864 ;
     RECT  0.203 19.89 1.147 20.988 ;
     RECT  0.103 21.942 1.147 21.96 ;
     RECT  0.571 22.986 1.147 23.004 ;
     RECT  0.823 29.466 1.147 29.754 ;
     RECT  0.347 37.566 1.147 37.584 ;
     RECT  0.419 40.338 1.147 40.356 ;
     RECT  0.175 50.796 1.147 50.814 ;
     RECT  0.571 52.416 1.147 52.884 ;
     RECT  0.239 55.026 1.147 55.044 ;
     RECT  1.147 12.024 1.183 12.546 ;
     RECT  0.823 13.878 1.183 14.634 ;
     RECT  1.147 18.846 1.183 18.954 ;
     RECT  1.147 19.89 1.183 21.186 ;
     RECT  1.147 21.942 1.183 23.004 ;
     RECT  0.103 24.174 1.183 24.192 ;
     RECT  0.535 38.448 1.183 38.466 ;
     RECT  0.383 43.506 1.183 45.018 ;
     RECT  1.147 55.026 1.183 55.134 ;
     RECT  1.183 38.448 1.211 38.664 ;
     RECT  1.147 50.166 1.219 50.814 ;
     RECT  1.183 54.378 1.219 55.134 ;
     RECT  0.067 55.926 1.219 55.944 ;
     RECT  1.147 26.874 1.283 26.892 ;
     RECT  1.255 10.098 1.355 10.116 ;
     RECT  1.147 3.006 1.435 3.564 ;
     RECT  0.103 4.356 1.435 4.644 ;
     RECT  0.239 34.668 1.687 35.694 ;
     RECT  1.687 34.668 1.975 35.766 ;
     RECT  1.687 2.07 2.16 2.088 ;
     RECT  1.435 3.006 2.16 4.644 ;
     RECT  1.147 5.508 2.16 5.526 ;
     RECT  1.723 7.866 2.16 7.884 ;
     RECT  1.147 8.676 2.16 9.306 ;
     RECT  1.183 12.024 2.16 14.634 ;
     RECT  1.687 15.606 2.16 15.624 ;
     RECT  1.723 16.776 2.16 16.794 ;
     RECT  1.147 17.694 2.16 17.982 ;
     RECT  1.183 18.846 2.16 21.186 ;
     RECT  1.183 21.942 2.16 24.192 ;
     RECT  0.239 28.188 2.16 28.206 ;
     RECT  1.147 29.268 2.16 29.754 ;
     RECT  0.419 31.086 2.16 31.104 ;
     RECT  1.291 32.778 2.16 32.796 ;
     RECT  1.975 34.326 2.16 35.766 ;
     RECT  1.147 37.476 2.16 37.584 ;
     RECT  1.211 38.646 2.16 38.664 ;
     RECT  1.147 40.104 2.16 41.094 ;
     RECT  1.183 42.156 2.16 42.174 ;
     RECT  1.183 43.506 2.16 45.144 ;
     RECT  1.975 46.08 2.16 46.098 ;
     RECT  0.823 47.394 2.16 48.294 ;
     RECT  1.147 49.086 2.16 49.104 ;
     RECT  1.219 50.166 2.16 50.994 ;
     RECT  1.147 51.984 2.16 52.884 ;
     RECT  1.219 54.378 2.16 55.944 ;
     RECT  2.16 2.07 2.299 108.009 ;
     RECT  0.535 1.116 2.335 1.134 ;
     RECT  2.299 1.998 2.335 108.009 ;
     RECT  2.335 1.116 3.847 108.009 ;
     RECT  3.847 1.071 3.955 108.009 ;
     RECT  3.955 1.026 10.283 108.009 ;
     RECT  10.283 1.026 11.219 1.089 ;
     RECT  11.219 1.071 11.543 1.089 ;
     RECT  10.283 1.881 14.639 108.009 ;
     RECT  14.639 1.926 16.987 108.009 ;
     RECT  16.987 1.881 17.663 108.009 ;
     RECT  17.663 1.926 21.091 108.009 ;
     RECT  21.091 1.881 23.436 108.009 ;
     RECT  23.436 1.881 23.603 38.034 ;
     RECT  23.436 61.668 23.639 61.686 ;
     RECT  23.436 49.824 23.675 50.31 ;
     RECT  23.675 50.292 23.711 50.31 ;
     RECT  23.603 1.881 23.963 25.434 ;
     RECT  23.603 26.334 23.963 38.034 ;
     RECT  23.963 1.881 24.035 25.344 ;
     RECT  23.963 26.37 24.539 38.034 ;
     RECT  24.035 1.881 25.079 25.2 ;
     RECT  25.079 1.926 25.488 25.2 ;
     RECT  24.539 26.37 25.488 29.25 ;
     RECT  24.539 30.276 25.488 38.034 ;
     RECT  23.436 48.474 25.488 48.492 ;
     RECT  25.488 1.926 25.871 86.67 ;
     RECT  25.871 1.998 31.415 86.67 ;
     RECT  31.415 2.151 147.312 86.67 ;
     RECT  147.312 27.036 147.587 30.744 ;
     RECT  147.312 36.126 148.099 36.954 ;
     RECT  147.587 28.386 148.171 30.744 ;
     RECT  147.312 31.626 148.171 35.064 ;
     RECT  147.312 2.151 149.287 25.434 ;
     RECT  148.783 26.226 149.287 26.244 ;
     RECT  149.287 2.151 149.323 26.244 ;
     RECT  147.587 27.036 149.323 27.594 ;
     RECT  148.099 36.126 149.359 37.494 ;
     RECT  149.323 2.151 149.364 27.594 ;
     RECT  148.171 28.386 149.364 35.064 ;
     RECT  149.359 36.09 149.364 37.494 ;
     RECT  147.312 40.176 149.364 40.194 ;
     RECT  147.312 41.886 149.364 41.904 ;
     RECT  23.436 88.821 149.364 108.009 ;
     RECT  149.364 2.151 170.64 108.009 ;
    LAYER M3 ;
     RECT  3.96 1.021 3.978 1.066 ;
     RECT  11.196 1.021 11.214 1.066 ;
     RECT  0.54 1.111 0.558 1.291 ;
     RECT  0.144 1.291 0.558 1.336 ;
     RECT  0.072 1.336 0.558 1.387 ;
     RECT  1.44 1.195 1.458 1.387 ;
     RECT  2.34 1.606 2.358 1.651 ;
     RECT  8.424 1.111 8.442 1.651 ;
     RECT  6.3 1.579 6.318 1.675 ;
     RECT  2.34 1.651 2.394 1.687 ;
     RECT  3.852 1.066 3.978 1.723 ;
     RECT  10.26 1.687 10.278 1.723 ;
     RECT  2.34 1.687 2.574 1.831 ;
     RECT  3.744 1.723 3.978 1.867 ;
     RECT  4.788 1.483 4.806 1.867 ;
     RECT  10.116 1.723 10.278 1.876 ;
     RECT  11.196 1.066 11.538 1.876 ;
     RECT  10.116 1.876 11.538 1.921 ;
     RECT  14.616 1.876 14.634 1.921 ;
     RECT  21.096 1.876 21.114 1.921 ;
     RECT  2.34 1.831 2.898 1.957 ;
     RECT  3.744 1.867 4.806 1.957 ;
     RECT  7.128 1.606 7.146 1.957 ;
     RECT  21.096 1.921 21.258 1.957 ;
     RECT  2.34 1.957 4.806 1.993 ;
     RECT  9.756 1.921 11.538 1.993 ;
     RECT  16.992 1.876 17.658 1.993 ;
     RECT  21.096 1.957 21.546 1.993 ;
     RECT  25.056 1.876 25.074 1.993 ;
     RECT  25.848 1.921 25.866 1.993 ;
     RECT  7.128 1.957 7.326 2.011 ;
     RECT  2.304 1.993 4.806 2.029 ;
     RECT  5.832 1.675 6.318 2.029 ;
     RECT  7.128 2.011 7.578 2.029 ;
     RECT  14.544 1.921 14.634 2.029 ;
     RECT  2.304 2.029 6.318 2.059 ;
     RECT  7.128 2.029 7.614 2.059 ;
     RECT  0.072 1.387 1.458 2.065 ;
     RECT  2.304 2.059 7.614 2.065 ;
     RECT  25.056 1.993 25.866 2.065 ;
     RECT  0.072 2.065 7.614 2.101 ;
     RECT  14.472 2.029 14.634 2.101 ;
     RECT  24.984 2.065 25.866 2.101 ;
     RECT  0.072 2.101 7.686 2.143 ;
     RECT  8.424 1.651 8.874 2.143 ;
     RECT  12.816 1.957 12.834 2.143 ;
     RECT  19.008 1.921 19.494 2.143 ;
     RECT  29.376 2.029 29.394 2.143 ;
     RECT  9.756 1.993 11.79 2.191 ;
     RECT  12.816 2.143 13.305 2.191 ;
     RECT  14.472 2.101 15.282 2.191 ;
     RECT  20.988 1.993 21.618 2.191 ;
     RECT  24.015 2.143 24.105 2.191 ;
     RECT  31.392 1.993 31.41 2.191 ;
     RECT  40.215 2.143 40.305 2.191 ;
     RECT  9.756 2.191 11.97 2.203 ;
     RECT  0.072 2.143 8.874 2.227 ;
     RECT  9.648 2.203 11.97 2.227 ;
     RECT  12.816 2.191 15.282 2.227 ;
     RECT  18.615 2.143 19.494 2.227 ;
     RECT  20.988 2.191 21.762 2.227 ;
     RECT  23.436 2.191 24.105 2.227 ;
     RECT  31.248 2.191 31.41 2.227 ;
     RECT  34.815 2.143 34.905 2.227 ;
     RECT  40.215 2.191 40.554 2.227 ;
     RECT  31.248 2.227 31.698 2.263 ;
     RECT  32.508 2.191 32.526 2.263 ;
     RECT  34.38 2.227 35.478 2.263 ;
     RECT  36.216 2.191 36.234 2.263 ;
     RECT  18.396 2.227 19.494 2.299 ;
     RECT  20.988 2.227 22.338 2.299 ;
     RECT  23.292 2.227 24.105 2.299 ;
     RECT  29.376 2.143 29.505 2.299 ;
     RECT  30.276 2.227 30.294 2.299 ;
     RECT  0.072 2.227 15.282 2.371 ;
     RECT  16.416 1.993 17.658 2.371 ;
     RECT  18.396 2.299 19.962 2.371 ;
     RECT  27.324 2.335 27.342 2.371 ;
     RECT  28.512 2.299 28.602 2.371 ;
     RECT  29.376 2.299 30.294 2.371 ;
     RECT  24.912 2.101 26.154 2.395 ;
     RECT  27.324 2.371 30.51 2.395 ;
     RECT  20.988 2.299 24.105 2.413 ;
     RECT  24.912 2.395 30.51 2.413 ;
     RECT  45.615 2.143 45.705 2.413 ;
     RECT  51.015 2.143 51.105 2.413 ;
     RECT  56.415 2.143 56.505 2.413 ;
     RECT  61.815 2.143 61.905 2.413 ;
     RECT  67.215 2.143 67.305 2.413 ;
     RECT  72.615 2.143 72.705 2.413 ;
     RECT  78.015 2.143 78.105 2.413 ;
     RECT  83.415 2.143 83.505 2.413 ;
     RECT  88.815 2.143 88.905 2.413 ;
     RECT  94.215 2.143 94.305 2.413 ;
     RECT  99.615 2.143 99.705 2.413 ;
     RECT  105.015 2.143 105.105 2.413 ;
     RECT  110.415 2.143 110.505 2.413 ;
     RECT  115.815 2.143 115.905 2.413 ;
     RECT  121.215 2.143 121.305 2.413 ;
     RECT  126.615 2.143 126.705 2.413 ;
     RECT  132.015 2.143 132.105 2.413 ;
     RECT  137.415 2.143 137.505 2.413 ;
     RECT  142.815 2.143 142.905 2.413 ;
     RECT  148.215 2.143 148.305 2.413 ;
     RECT  153.615 2.143 153.705 2.413 ;
     RECT  159.015 2.143 159.105 2.413 ;
     RECT  164.415 2.143 164.505 2.413 ;
     RECT  169.815 2.143 169.905 2.413 ;
     RECT  0.072 2.371 19.962 2.461 ;
     RECT  20.988 2.413 30.51 2.461 ;
     RECT  34.38 2.263 36.234 2.461 ;
     RECT  0.072 2.461 30.51 2.569 ;
     RECT  31.248 2.263 32.526 2.569 ;
     RECT  0.072 2.569 32.526 2.573 ;
     RECT  2.304 2.573 32.526 2.641 ;
     RECT  37.836 2.497 37.854 2.641 ;
     RECT  39.492 2.227 40.554 2.731 ;
     RECT  33.912 2.461 36.234 2.759 ;
     RECT  37.764 2.641 37.854 2.767 ;
     RECT  2.304 2.641 32.634 2.803 ;
     RECT  33.912 2.759 36.594 2.803 ;
     RECT  37.764 2.767 38.106 2.803 ;
     RECT  39.492 2.731 40.77 2.813 ;
     RECT  2.304 2.803 32.814 2.911 ;
     RECT  33.912 2.803 38.106 2.911 ;
     RECT  39.708 2.813 40.77 2.911 ;
     RECT  39.708 2.911 41.346 3.343 ;
     RECT  39.708 3.343 42.066 3.379 ;
     RECT  2.304 2.911 38.862 3.407 ;
     RECT  43.092 3.355 43.11 3.451 ;
     RECT  26.1 3.407 38.862 3.541 ;
     RECT  39.708 3.379 42.21 3.541 ;
     RECT  42.984 3.451 43.11 3.541 ;
     RECT  43.848 3.307 43.866 3.541 ;
     RECT  26.1 3.541 43.866 3.649 ;
     RECT  26.1 3.649 43.974 3.685 ;
     RECT  26.1 3.685 44.01 3.721 ;
     RECT  45.615 2.413 45.897 3.721 ;
     RECT  48.888 3.721 48.906 3.811 ;
     RECT  26.1 3.721 44.874 3.847 ;
     RECT  45.615 3.721 46.782 3.847 ;
     RECT  2.304 3.407 25.326 3.875 ;
     RECT  48.456 3.811 48.906 3.931 ;
     RECT  0.072 2.573 1.458 3.947 ;
     RECT  47.916 3.931 48.906 4.117 ;
     RECT  26.1 3.847 46.782 4.189 ;
     RECT  47.88 4.117 48.906 4.225 ;
     RECT  25.92 4.189 46.782 4.289 ;
     RECT  0.072 3.947 1.17 4.379 ;
     RECT  2.304 3.875 25.182 4.379 ;
     RECT  26.172 4.289 46.782 4.379 ;
     RECT  43.056 4.379 46.782 4.387 ;
     RECT  47.88 4.225 49.05 4.387 ;
     RECT  0.108 4.379 1.17 4.397 ;
     RECT  28.8 4.379 41.742 4.415 ;
     RECT  28.8 4.415 38.358 4.487 ;
     RECT  28.8 4.487 38.286 4.523 ;
     RECT  28.8 4.523 38.214 4.541 ;
     RECT  39.132 4.415 41.742 4.559 ;
     RECT  26.172 4.379 28.062 4.649 ;
     RECT  39.924 4.559 41.742 4.649 ;
     RECT  0.108 4.397 0.342 4.685 ;
     RECT  43.056 4.387 49.05 4.693 ;
     RECT  43.056 4.693 49.302 4.747 ;
     RECT  2.304 4.379 25.11 4.757 ;
     RECT  39.132 4.559 39.15 4.793 ;
     RECT  72.615 2.413 72.897 4.801 ;
     RECT  26.208 4.649 28.062 4.919 ;
     RECT  43.056 4.747 49.374 4.955 ;
     RECT  2.304 4.757 24.426 4.991 ;
     RECT  43.272 4.955 49.374 5.035 ;
     RECT  2.304 4.991 21.222 5.099 ;
     RECT  40.215 4.649 41.742 5.099 ;
     RECT  43.272 5.035 49.41 5.117 ;
     RECT  28.8 4.541 37.494 5.131 ;
     RECT  26.208 4.919 27.594 5.189 ;
     RECT  43.308 5.117 49.41 5.189 ;
     RECT  45.468 5.189 49.41 5.197 ;
     RECT  43.308 5.189 44.55 5.225 ;
     RECT  1.152 4.397 1.17 5.227 ;
     RECT  45.468 5.197 49.446 5.269 ;
     RECT  45.468 5.269 49.518 5.309 ;
     RECT  26.388 5.189 27.594 5.333 ;
     RECT  41.688 5.099 41.742 5.333 ;
     RECT  45.468 5.309 49.446 5.333 ;
     RECT  51.015 2.413 51.297 5.431 ;
     RECT  28.332 5.131 37.494 5.459 ;
     RECT  45.54 5.333 49.446 5.459 ;
     RECT  0.144 4.685 0.234 5.501 ;
     RECT  43.308 5.225 43.902 5.531 ;
     RECT  45.54 5.459 49.194 5.603 ;
     RECT  41.688 5.333 41.706 5.639 ;
     RECT  27.36 5.333 27.594 5.659 ;
     RECT  28.332 5.459 36.162 5.659 ;
     RECT  22.14 4.991 24.426 5.701 ;
     RECT  25.38 5.161 25.47 5.701 ;
     RECT  0.216 5.501 0.234 5.707 ;
     RECT  27.36 5.659 36.162 5.729 ;
     RECT  1.152 5.227 1.278 5.851 ;
     RECT  2.304 5.099 21.042 5.851 ;
     RECT  22.14 5.701 25.47 5.881 ;
     RECT  61.815 2.413 62.097 5.971 ;
     RECT  142.815 2.413 143.097 5.971 ;
     RECT  43.884 5.531 43.902 5.999 ;
     RECT  142.815 5.971 143.442 6.029 ;
     RECT  29.376 5.729 36.162 6.035 ;
     RECT  1.152 5.851 1.458 6.077 ;
     RECT  142.815 6.029 143.154 6.077 ;
     RECT  22.14 5.881 25.542 6.079 ;
     RECT  26.388 5.333 26.622 6.079 ;
     RECT  29.376 6.035 31.914 6.08 ;
     RECT  45.615 5.603 49.194 6.107 ;
     RECT  1.152 6.077 1.386 6.125 ;
     RECT  2.304 5.851 21.222 6.139 ;
     RECT  22.14 6.079 26.622 6.139 ;
     RECT  45.615 6.107 48.978 6.179 ;
     RECT  32.724 6.035 36.162 6.232 ;
     RECT  37.044 5.459 37.35 6.232 ;
     RECT  45.615 6.179 48.006 6.269 ;
     RECT  0.216 5.707 0.342 6.283 ;
     RECT  29.376 6.08 31.734 6.305 ;
     RECT  45.615 6.269 47.934 6.305 ;
     RECT  2.304 6.139 26.622 6.313 ;
     RECT  27.36 5.729 28.53 6.313 ;
     RECT  0.216 6.283 0.378 6.331 ;
     RECT  29.376 6.305 30.33 6.341 ;
     RECT  45.615 6.305 46.638 6.341 ;
     RECT  2.304 6.313 28.53 6.349 ;
     RECT  45.615 6.341 46.53 6.365 ;
     RECT  31.14 6.305 31.734 6.377 ;
     RECT  47.448 6.305 47.934 6.377 ;
     RECT  47.664 6.377 47.934 6.449 ;
     RECT  48.96 6.179 48.978 6.449 ;
     RECT  0.144 6.331 0.378 6.475 ;
     RECT  1.152 6.125 1.278 6.475 ;
     RECT  2.268 6.349 28.53 6.511 ;
     RECT  29.376 6.341 30.258 6.511 ;
     RECT  56.415 2.413 56.697 6.511 ;
     RECT  67.215 2.413 67.497 6.511 ;
     RECT  78.015 2.413 78.297 6.511 ;
     RECT  88.815 2.413 89.097 6.511 ;
     RECT  99.615 2.413 99.897 6.511 ;
     RECT  110.415 2.413 110.697 6.511 ;
     RECT  121.215 2.413 121.497 6.511 ;
     RECT  132.015 2.413 132.297 6.511 ;
     RECT  142.815 6.077 143.097 6.523 ;
     RECT  2.268 6.511 30.258 6.557 ;
     RECT  56.304 6.511 56.697 6.557 ;
     RECT  67.104 6.511 67.497 6.557 ;
     RECT  77.904 6.511 78.297 6.557 ;
     RECT  88.704 6.511 89.097 6.557 ;
     RECT  99.504 6.511 99.897 6.557 ;
     RECT  110.304 6.511 110.697 6.557 ;
     RECT  121.104 6.511 121.497 6.557 ;
     RECT  131.904 6.511 132.297 6.557 ;
     RECT  0.144 6.475 1.278 6.605 ;
     RECT  2.304 6.557 30.258 6.611 ;
     RECT  143.928 6.571 143.946 6.611 ;
     RECT  142.524 6.523 143.097 6.653 ;
     RECT  32.724 6.232 37.35 6.691 ;
     RECT  144.252 6.619 144.27 6.719 ;
     RECT  50.976 5.431 51.297 6.781 ;
     RECT  0.144 6.605 0.378 6.797 ;
     RECT  32.724 6.691 37.746 6.808 ;
     RECT  32.724 6.808 37.854 6.817 ;
     RECT  44.46 6.781 44.478 6.817 ;
     RECT  72.108 4.801 72.897 6.881 ;
     RECT  50.616 6.781 51.297 6.961 ;
     RECT  44.352 6.817 44.478 7.087 ;
     RECT  45.615 6.365 45.897 7.087 ;
     RECT  32.724 6.817 37.998 7.123 ;
     RECT  115.815 2.413 116.097 7.123 ;
     RECT  0.144 6.797 0.162 7.133 ;
     RECT  31.14 6.377 31.554 7.189 ;
     RECT  48.06 7.003 48.078 7.189 ;
     RECT  29.376 6.611 30.258 7.195 ;
     RECT  31.14 7.189 31.842 7.195 ;
     RECT  44.352 7.087 45.897 7.195 ;
     RECT  49.392 6.925 49.41 7.231 ;
     RECT  50.436 6.961 51.297 7.231 ;
     RECT  135.72 7.147 135.738 7.231 ;
     RECT  29.376 7.195 31.842 7.259 ;
     RECT  135.396 7.231 135.738 7.259 ;
     RECT  135.396 7.259 135.414 7.277 ;
     RECT  47.7 7.189 48.078 7.321 ;
     RECT  49.356 7.231 49.41 7.321 ;
     RECT  47.7 7.321 49.41 7.339 ;
     RECT  50.184 7.231 51.297 7.339 ;
     RECT  29.376 7.259 30.834 7.385 ;
     RECT  44.1 7.195 45.897 7.387 ;
     RECT  47.7 7.339 51.297 7.421 ;
     RECT  48.24 7.421 51.297 7.465 ;
     RECT  2.304 6.611 28.566 7.501 ;
     RECT  29.376 7.385 30.474 7.501 ;
     RECT  31.752 7.259 31.842 7.501 ;
     RECT  32.688 7.123 37.998 7.501 ;
     RECT  1.152 6.605 1.278 7.531 ;
     RECT  48.24 7.465 51.822 7.591 ;
     RECT  31.752 7.501 37.998 7.757 ;
     RECT  31.752 7.757 32.382 7.763 ;
     RECT  33.3 7.757 37.998 7.763 ;
     RECT  41.652 7.699 41.67 7.771 ;
     RECT  48.24 7.591 52.506 7.771 ;
     RECT  0.324 7.531 1.278 7.861 ;
     RECT  2.304 7.501 30.474 7.861 ;
     RECT  33.588 7.763 37.998 7.861 ;
     RECT  38.772 7.591 38.79 7.861 ;
     RECT  42.768 7.501 42.858 7.861 ;
     RECT  137.415 2.413 137.697 7.861 ;
     RECT  32.256 7.763 32.382 7.889 ;
     RECT  33.588 7.861 38.79 7.897 ;
     RECT  42.696 7.861 42.858 7.933 ;
     RECT  43.632 7.387 45.897 7.933 ;
     RECT  0.324 7.861 30.474 7.949 ;
     RECT  0.324 7.949 30.402 7.961 ;
     RECT  0.324 7.961 20.178 7.963 ;
     RECT  33.588 7.897 38.862 7.969 ;
     RECT  134.532 7.867 134.55 7.997 ;
     RECT  137.415 7.861 138.33 7.997 ;
     RECT  0.18 7.963 20.178 8.005 ;
     RECT  42.696 7.933 45.897 8.005 ;
     RECT  41.652 7.771 41.958 8.041 ;
     RECT  42.696 8.005 46.206 8.041 ;
     RECT  61.236 5.971 62.097 8.041 ;
     RECT  0.108 8.005 20.178 8.045 ;
     RECT  33.588 7.969 38.898 8.069 ;
     RECT  48.24 7.771 52.938 8.203 ;
     RECT  0.324 8.045 20.178 8.237 ;
     RECT  48.204 8.203 52.938 8.275 ;
     RECT  33.588 8.069 38.862 8.339 ;
     RECT  20.916 7.961 30.366 8.429 ;
     RECT  33.696 8.339 38.862 8.429 ;
     RECT  33.696 8.429 33.714 8.501 ;
     RECT  34.668 8.429 38.862 8.501 ;
     RECT  47.7 8.275 53.154 8.509 ;
     RECT  47.52 8.509 53.154 8.536 ;
     RECT  47.52 8.536 53.298 8.581 ;
     RECT  54.756 8.545 55.458 8.581 ;
     RECT  56.415 6.557 56.697 8.581 ;
     RECT  59.868 8.203 59.886 8.581 ;
     RECT  41.652 8.041 46.746 8.671 ;
     RECT  47.52 8.581 55.458 8.671 ;
     RECT  0.324 8.237 1.458 8.699 ;
     RECT  41.652 8.671 55.53 8.731 ;
     RECT  56.415 8.581 57.33 8.731 ;
     RECT  59.868 8.581 59.922 8.743 ;
     RECT  0.324 8.699 0.558 8.779 ;
     RECT  41.652 8.731 57.33 8.779 ;
     RECT  58.14 8.671 58.158 8.779 ;
     RECT  34.776 8.501 38.862 8.851 ;
     RECT  40.215 5.099 40.497 8.851 ;
     RECT  41.652 8.779 58.158 8.851 ;
     RECT  20.952 8.429 30.366 8.941 ;
     RECT  32.256 7.889 32.274 8.941 ;
     RECT  58.932 8.779 58.95 8.941 ;
     RECT  59.868 8.743 60.246 8.941 ;
     RECT  61.236 8.041 62.406 8.941 ;
     RECT  34.776 8.851 38.97 8.971 ;
     RECT  40.104 8.851 58.158 8.971 ;
     RECT  32.04 8.941 32.274 9.211 ;
     RECT  34.776 8.971 58.158 9.239 ;
     RECT  0.144 8.779 0.558 9.259 ;
     RECT  34.776 9.239 54.702 9.275 ;
     RECT  31.932 9.211 32.346 9.283 ;
     RECT  1.368 8.699 1.458 9.307 ;
     RECT  2.304 8.237 20.178 9.307 ;
     RECT  0.108 9.259 0.558 9.311 ;
     RECT  1.368 9.307 20.178 9.319 ;
     RECT  20.952 8.941 31.014 9.319 ;
     RECT  0.108 9.311 0.342 9.383 ;
     RECT  0.144 9.383 0.342 9.389 ;
     RECT  20.952 9.319 31.086 9.391 ;
     RECT  31.932 9.283 32.418 9.391 ;
     RECT  34.776 9.275 42.498 9.391 ;
     RECT  150.66 5.431 150.678 9.391 ;
     RECT  151.668 8.311 151.686 9.391 ;
     RECT  1.368 9.319 20.214 9.451 ;
     RECT  1.152 9.451 20.214 9.481 ;
     RECT  20.952 9.391 32.418 9.481 ;
     RECT  55.656 9.239 58.158 9.481 ;
     RECT  58.932 8.941 62.406 9.481 ;
     RECT  1.152 9.481 32.418 9.509 ;
     RECT  43.272 9.275 54.702 9.509 ;
     RECT  43.272 9.509 46.89 9.581 ;
     RECT  47.844 9.509 51.93 9.581 ;
     RECT  31.932 9.509 32.418 9.589 ;
     RECT  43.272 9.581 46.782 9.617 ;
     RECT  0.144 9.389 0.234 9.629 ;
     RECT  25.452 9.509 31.086 9.629 ;
     RECT  47.844 9.581 51.858 9.653 ;
     RECT  52.74 9.509 54.702 9.653 ;
     RECT  31.932 9.589 33.102 9.661 ;
     RECT  1.152 9.509 24.714 9.677 ;
     RECT  47.844 9.653 51.75 9.779 ;
     RECT  142.815 6.653 143.097 9.823 ;
     RECT  31.932 9.661 33.714 9.835 ;
     RECT  34.488 9.391 42.498 9.835 ;
     RECT  31.932 9.835 42.498 9.959 ;
     RECT  32.508 9.959 42.498 10.057 ;
     RECT  43.272 9.617 46.638 10.057 ;
     RECT  1.152 9.677 1.35 10.121 ;
     RECT  1.152 10.121 1.278 10.157 ;
     RECT  53.028 9.653 54.702 10.165 ;
     RECT  55.656 9.481 62.406 10.165 ;
     RECT  1.152 10.157 1.17 10.205 ;
     RECT  53.028 10.165 62.406 10.229 ;
     RECT  0.144 9.629 0.162 10.253 ;
     RECT  2.304 9.677 24.714 10.291 ;
     RECT  25.452 9.629 30.834 10.291 ;
     RECT  72.615 6.881 72.897 10.315 ;
     RECT  2.304 10.291 30.834 10.319 ;
     RECT  32.508 10.057 46.638 10.319 ;
     RECT  53.028 10.229 55.314 10.319 ;
     RECT  74.16 6.853 74.178 10.319 ;
     RECT  142.815 9.823 143.658 10.319 ;
     RECT  35.82 10.319 46.638 10.355 ;
     RECT  32.508 10.319 35.097 10.391 ;
     RECT  47.916 9.779 51.75 10.399 ;
     RECT  53.028 10.319 55.242 10.459 ;
     RECT  37.548 10.355 46.638 10.471 ;
     RECT  72.615 10.315 73.206 10.471 ;
     RECT  32.508 10.391 33.786 10.625 ;
     RECT  37.548 10.471 46.998 10.625 ;
     RECT  37.8 10.625 46.998 10.633 ;
     RECT  148.215 2.413 148.497 10.633 ;
     RECT  31.572 10.315 31.734 10.697 ;
     RECT  149.328 8.815 149.346 10.705 ;
     RECT  37.8 10.633 47.106 10.733 ;
     RECT  52.812 10.459 55.242 10.741 ;
     RECT  56.124 10.229 62.406 10.769 ;
     RECT  0.324 10.507 0.342 10.795 ;
     RECT  37.836 10.733 47.106 10.843 ;
     RECT  47.916 10.399 51.858 10.843 ;
     RECT  58.788 10.769 62.406 10.859 ;
     RECT  70.128 10.561 70.146 10.867 ;
     RECT  150.66 9.391 151.686 10.867 ;
     RECT  152.604 6.313 152.622 10.867 ;
     RECT  37.836 10.843 51.858 10.891 ;
     RECT  52.704 10.741 55.242 10.891 ;
     RECT  28.98 10.319 30.834 10.939 ;
     RECT  70.128 10.867 70.722 10.967 ;
     RECT  72.615 10.471 73.566 10.967 ;
     RECT  58.824 10.859 62.406 11.039 ;
     RECT  0.324 10.795 0.846 11.083 ;
     RECT  2.304 10.319 28.242 11.101 ;
     RECT  28.98 10.939 31.374 11.101 ;
     RECT  35.82 10.355 36.342 11.101 ;
     RECT  72.615 10.967 73.386 11.129 ;
     RECT  0.324 11.083 1.17 11.131 ;
     RECT  58.896 11.039 62.406 11.165 ;
     RECT  34.815 10.391 35.097 11.173 ;
     RECT  35.82 11.101 36.558 11.173 ;
     RECT  67.215 6.557 67.497 11.209 ;
     RECT  34.815 11.173 36.558 11.245 ;
     RECT  150.66 10.867 152.622 11.281 ;
     RECT  32.508 10.625 33.21 11.371 ;
     RECT  2.304 11.101 31.374 11.399 ;
     RECT  37.836 10.891 55.242 11.399 ;
     RECT  32.184 11.371 33.21 11.407 ;
     RECT  34.164 11.245 36.558 11.407 ;
     RECT  50.616 11.399 55.242 11.407 ;
     RECT  56.124 10.769 58.05 11.407 ;
     RECT  58.932 11.165 62.406 11.471 ;
     RECT  32.184 11.407 36.774 11.479 ;
     RECT  0.144 11.131 1.17 11.515 ;
     RECT  37.836 11.399 49.842 11.543 ;
     RECT  59.904 11.471 59.922 11.543 ;
     RECT  0.144 11.515 1.386 11.659 ;
     RECT  2.376 11.399 31.374 11.677 ;
     RECT  32.184 11.479 37.026 11.677 ;
     RECT  149.328 10.705 149.814 11.677 ;
     RECT  150.624 11.281 152.622 11.677 ;
     RECT  0.108 11.659 1.386 11.693 ;
     RECT  60.984 11.471 62.406 11.749 ;
     RECT  2.376 11.677 37.026 11.777 ;
     RECT  37.836 11.543 48.546 11.813 ;
     RECT  70.128 10.967 70.218 11.849 ;
     RECT  117.288 9.931 117.306 11.939 ;
     RECT  28.944 11.777 37.026 11.947 ;
     RECT  37.836 11.813 38.898 11.947 ;
     RECT  50.616 11.407 58.05 11.947 ;
     RECT  58.932 11.471 58.95 11.947 ;
     RECT  147.636 10.633 148.497 11.947 ;
     RECT  28.944 11.947 38.898 11.975 ;
     RECT  0.108 11.693 1.314 11.981 ;
     RECT  147.6 11.947 148.497 12.055 ;
     RECT  149.328 11.677 152.622 12.055 ;
     RECT  146.484 11.983 146.502 12.083 ;
     RECT  60.984 11.749 62.442 12.091 ;
     RECT  49.536 11.543 49.842 12.181 ;
     RECT  50.616 11.947 58.95 12.181 ;
     RECT  2.376 11.777 28.098 12.217 ;
     RECT  60.984 12.091 62.478 12.317 ;
     RECT  2.34 12.217 28.098 12.325 ;
     RECT  39.708 11.813 48.546 12.325 ;
     RECT  49.536 12.181 58.95 12.325 ;
     RECT  60.984 12.317 62.442 12.451 ;
     RECT  2.304 12.325 28.098 12.517 ;
     RECT  49.536 12.325 59.454 12.517 ;
     RECT  49.536 12.517 60.03 12.523 ;
     RECT  60.804 12.451 62.442 12.523 ;
     RECT  0.108 11.981 1.278 12.551 ;
     RECT  39.708 12.325 48.654 12.595 ;
     RECT  0.144 12.551 1.278 12.715 ;
     RECT  2.304 12.517 28.17 12.721 ;
     RECT  29.16 11.975 38.898 12.721 ;
     RECT  39.636 12.595 48.654 12.721 ;
     RECT  49.536 12.523 62.442 12.785 ;
     RECT  2.304 12.721 48.654 12.793 ;
     RECT  49.536 12.785 53.406 12.793 ;
     RECT  66.132 12.055 66.15 12.793 ;
     RECT  67.215 11.209 67.842 12.793 ;
     RECT  54.288 12.785 62.442 12.797 ;
     RECT  2.304 12.793 53.406 12.821 ;
     RECT  69.012 12.793 69.03 12.865 ;
     RECT  66.132 12.793 67.842 12.893 ;
     RECT  68.94 12.865 69.03 12.893 ;
     RECT  68.94 12.893 68.958 13.037 ;
     RECT  0.144 12.715 1.386 13.085 ;
     RECT  2.304 12.821 53.334 13.199 ;
     RECT  0.828 13.085 1.386 13.291 ;
     RECT  2.304 13.199 37.962 13.291 ;
     RECT  78.015 6.557 78.297 13.432 ;
     RECT  88.815 6.557 89.097 13.432 ;
     RECT  99.615 6.557 99.897 13.432 ;
     RECT  110.415 6.557 110.697 13.432 ;
     RECT  121.215 6.557 121.497 13.432 ;
     RECT  132.015 6.557 132.297 13.432 ;
     RECT  54.324 12.797 62.442 13.441 ;
     RECT  139.644 13.435 139.662 13.531 ;
     RECT  142.815 10.319 143.514 13.531 ;
     RECT  144.612 11.785 144.63 13.531 ;
     RECT  139.356 13.531 139.662 13.559 ;
     RECT  38.808 13.199 53.334 13.567 ;
     RECT  54.324 13.441 62.946 13.567 ;
     RECT  54.216 13.567 62.946 13.603 ;
     RECT  142.524 13.531 144.63 13.613 ;
     RECT  83.415 2.413 83.697 13.627 ;
     RECT  139.356 13.559 139.374 13.661 ;
     RECT  143.928 13.613 144.63 13.661 ;
     RECT  0.828 13.291 37.962 13.667 ;
     RECT  38.808 13.567 53.406 13.675 ;
     RECT  54.216 13.603 63.27 13.675 ;
     RECT  66.132 12.893 66.15 13.675 ;
     RECT  67.104 12.893 67.842 13.675 ;
     RECT  83.415 13.627 84.222 13.675 ;
     RECT  38.808 13.675 63.486 13.711 ;
     RECT  38.808 13.711 63.522 13.739 ;
     RECT  72.615 11.129 73.314 13.829 ;
     RECT  146.124 13.369 146.142 13.829 ;
     RECT  70.128 11.849 70.146 13.837 ;
     RECT  52.776 13.739 63.522 13.873 ;
     RECT  0.828 13.667 36.45 13.901 ;
     RECT  74.556 13.801 74.574 13.937 ;
     RECT  146.556 13.837 146.574 13.937 ;
     RECT  64.98 12.829 64.998 13.945 ;
     RECT  66.132 13.675 67.842 13.945 ;
     RECT  70.128 13.837 70.722 13.973 ;
     RECT  118.584 13.873 118.602 13.973 ;
     RECT  130.536 13.873 130.554 13.973 ;
     RECT  138.528 13.873 138.546 13.973 ;
     RECT  38.808 13.739 52.002 13.981 ;
     RECT  52.776 13.873 64.062 13.981 ;
     RECT  64.98 13.945 67.842 13.981 ;
     RECT  147.6 12.055 152.622 13.981 ;
     RECT  121.104 13.432 121.497 13.997 ;
     RECT  131.904 13.432 132.297 13.997 ;
     RECT  52.776 13.981 67.842 14.009 ;
     RECT  77.904 13.432 78.297 14.009 ;
     RECT  88.704 13.432 89.097 14.009 ;
     RECT  99.504 13.432 99.897 14.009 ;
     RECT  110.304 13.432 110.697 14.009 ;
     RECT  117.144 11.947 117.162 14.009 ;
     RECT  37.44 13.667 37.962 14.071 ;
     RECT  38.736 13.981 52.002 14.071 ;
     RECT  1.152 13.901 36.45 14.099 ;
     RECT  142.524 13.613 143.097 14.141 ;
     RECT  145.656 14.071 145.782 14.141 ;
     RECT  126.615 2.413 126.897 14.155 ;
     RECT  37.44 14.071 52.002 14.171 ;
     RECT  145.764 14.141 145.782 14.171 ;
     RECT  47.916 14.171 52.002 14.207 ;
     RECT  47.916 14.207 49.05 14.243 ;
     RECT  147.6 13.981 152.802 14.279 ;
     RECT  70.128 13.973 70.146 14.369 ;
     RECT  36.324 14.099 36.45 14.485 ;
     RECT  1.152 14.099 35.406 14.513 ;
     RECT  36.324 14.485 36.486 14.521 ;
     RECT  36.324 14.521 36.594 14.611 ;
     RECT  37.44 14.171 47.178 14.611 ;
     RECT  49.824 14.207 52.002 14.611 ;
     RECT  52.776 14.009 66.474 14.611 ;
     RECT  142.815 14.141 143.097 14.611 ;
     RECT  49.824 14.611 66.474 14.675 ;
     RECT  52.992 14.675 66.474 14.813 ;
     RECT  53.064 14.813 66.474 14.827 ;
     RECT  67.215 14.009 67.842 14.827 ;
     RECT  53.064 14.827 67.842 14.881 ;
     RECT  83.415 13.675 84.474 14.881 ;
     RECT  148.215 14.279 152.802 14.909 ;
     RECT  36.324 14.611 47.178 14.917 ;
     RECT  53.064 14.881 68.238 14.923 ;
     RECT  53.064 14.923 68.49 14.953 ;
     RECT  53.064 14.953 68.526 14.989 ;
     RECT  106.596 14.917 106.614 15.017 ;
     RECT  1.152 14.513 33.534 15.053 ;
     RECT  34.38 14.513 35.406 15.061 ;
     RECT  36.288 14.917 47.178 15.061 ;
     RECT  48.06 14.243 49.05 15.061 ;
     RECT  0.108 14.251 0.414 15.115 ;
     RECT  1.152 15.053 32.346 15.115 ;
     RECT  74.484 13.945 74.502 15.179 ;
     RECT  53.064 14.989 68.778 15.187 ;
     RECT  0.108 15.115 32.346 15.293 ;
     RECT  33.084 15.053 33.534 15.295 ;
     RECT  34.38 15.061 49.05 15.295 ;
     RECT  53.064 15.187 68.958 15.295 ;
     RECT  121.215 13.997 121.497 15.307 ;
     RECT  70.164 14.731 70.182 15.331 ;
     RECT  0.108 15.293 0.378 15.341 ;
     RECT  33.084 15.295 49.05 15.355 ;
     RECT  49.824 14.675 52.218 15.355 ;
     RECT  53.064 15.295 68.994 15.359 ;
     RECT  67.215 15.359 68.994 15.421 ;
     RECT  69.768 15.331 70.182 15.421 ;
     RECT  33.084 15.355 52.218 15.601 ;
     RECT  53.064 15.359 66.402 15.601 ;
     RECT  148.215 14.909 148.497 15.601 ;
     RECT  1.152 15.293 32.346 15.629 ;
     RECT  110.415 14.009 110.697 15.685 ;
     RECT  83.052 14.881 84.474 15.691 ;
     RECT  88.815 14.009 89.097 15.691 ;
     RECT  99.615 14.009 99.897 15.691 ;
     RECT  132.015 13.997 132.297 15.691 ;
     RECT  142.815 14.611 143.442 15.691 ;
     RECT  33.084 15.601 66.402 15.719 ;
     RECT  133.524 15.565 133.542 15.719 ;
     RECT  110.304 15.685 110.697 15.725 ;
     RECT  88.704 15.691 89.097 15.728 ;
     RECT  99.504 15.691 99.897 15.728 ;
     RECT  131.904 15.691 132.297 15.728 ;
     RECT  82.548 15.691 84.474 15.787 ;
     RECT  33.084 15.719 57.294 15.827 ;
     RECT  82.368 15.787 84.474 15.827 ;
     RECT  105.015 2.413 105.297 15.835 ;
     RECT  1.152 15.629 1.278 15.869 ;
     RECT  2.34 15.629 32.346 15.871 ;
     RECT  33.084 15.827 43.65 15.871 ;
     RECT  2.34 15.871 43.65 15.989 ;
     RECT  44.388 15.827 57.294 15.989 ;
     RECT  67.215 15.421 70.182 15.997 ;
     RECT  75.096 15.295 75.114 15.997 ;
     RECT  102.024 15.457 102.042 16.027 ;
     RECT  58.176 15.719 66.402 16.105 ;
     RECT  67.215 15.997 70.722 16.105 ;
     RECT  53.46 15.989 57.294 16.133 ;
     RECT  58.176 16.105 70.722 16.303 ;
     RECT  142.704 15.691 143.442 16.315 ;
     RECT  58.176 16.303 70.794 16.403 ;
     RECT  75.096 15.997 75.726 16.405 ;
     RECT  68.652 16.403 70.794 16.439 ;
     RECT  0.144 15.341 0.378 16.459 ;
     RECT  78.015 14.009 78.297 16.501 ;
     RECT  121.032 15.307 121.497 16.501 ;
     RECT  58.176 16.403 67.806 16.529 ;
     RECT  142.524 16.315 143.442 16.537 ;
     RECT  133.416 15.835 133.434 16.573 ;
     RECT  58.176 16.529 67.497 16.601 ;
     RECT  2.415 15.989 43.65 16.609 ;
     RECT  44.388 15.989 52.722 16.609 ;
     RECT  133.38 16.573 133.434 16.673 ;
     RECT  2.415 16.609 52.722 16.709 ;
     RECT  2.415 16.709 32.202 16.771 ;
     RECT  0.144 16.459 0.558 16.781 ;
     RECT  104.904 15.835 105.297 16.795 ;
     RECT  83.052 15.827 84.474 16.799 ;
     RECT  142.524 16.537 143.838 16.807 ;
     RECT  147.636 15.601 148.497 16.807 ;
     RECT  0.54 16.781 0.558 16.843 ;
     RECT  1.728 16.771 32.202 16.843 ;
     RECT  32.94 16.709 52.722 16.843 ;
     RECT  53.46 16.133 56.79 16.843 ;
     RECT  74.736 16.405 75.726 16.843 ;
     RECT  76.968 15.529 76.986 16.843 ;
     RECT  147.492 16.807 148.497 16.843 ;
     RECT  83.052 16.799 84.402 16.871 ;
     RECT  138.564 16.843 138.582 16.879 ;
     RECT  86.688 16.807 86.706 16.907 ;
     RECT  101.484 16.027 102.042 16.907 ;
     RECT  142.38 16.807 143.838 16.907 ;
     RECT  58.176 16.601 65.358 16.915 ;
     RECT  74.664 16.843 76.986 16.943 ;
     RECT  32.94 16.843 56.79 16.951 ;
     RECT  57.852 16.915 65.358 16.951 ;
     RECT  138.528 16.879 138.582 16.979 ;
     RECT  142.524 16.907 143.838 16.979 ;
     RECT  144.612 13.661 144.63 17.041 ;
     RECT  138.528 16.979 138.546 17.069 ;
     RECT  32.94 16.951 57.006 17.083 ;
     RECT  57.78 16.951 65.358 17.083 ;
     RECT  74.736 16.943 76.986 17.105 ;
     RECT  72.615 13.829 72.897 17.113 ;
     RECT  74.808 17.105 76.986 17.113 ;
     RECT  144.612 17.041 144.954 17.113 ;
     RECT  72.615 17.113 73.098 17.149 ;
     RECT  74.808 17.113 77.274 17.149 ;
     RECT  78.015 16.501 78.606 17.149 ;
     RECT  149.328 14.909 152.802 17.149 ;
     RECT  74.808 17.149 78.606 17.213 ;
     RECT  144.612 17.113 145.278 17.221 ;
     RECT  133.38 16.673 133.398 17.249 ;
     RECT  0.54 16.843 32.202 17.261 ;
     RECT  66.132 16.601 67.497 17.311 ;
     RECT  71.964 17.149 73.098 17.311 ;
     RECT  71.568 17.311 73.098 17.338 ;
     RECT  32.94 17.083 65.358 17.339 ;
     RECT  101.736 16.907 102.042 17.339 ;
     RECT  66.132 17.311 67.554 17.347 ;
     RECT  98.604 17.221 98.622 17.371 ;
     RECT  99.615 15.728 99.897 17.371 ;
     RECT  98.604 17.371 99.897 17.375 ;
     RECT  101.808 17.339 102.042 17.375 ;
     RECT  98.928 17.375 99.897 17.383 ;
     RECT  100.8 17.347 100.962 17.383 ;
     RECT  68.652 16.439 70.722 17.419 ;
     RECT  71.568 17.338 73.134 17.419 ;
     RECT  153.615 2.413 153.897 17.419 ;
     RECT  102.024 17.375 102.042 17.447 ;
     RECT  2.304 17.261 32.202 17.455 ;
     RECT  32.94 17.339 55.494 17.455 ;
     RECT  56.415 17.339 65.358 17.467 ;
     RECT  66.132 17.347 67.626 17.467 ;
     RECT  104.904 16.795 105.462 17.483 ;
     RECT  0.54 17.261 1.17 17.515 ;
     RECT  68.652 17.419 73.134 17.519 ;
     RECT  93.42 17.221 93.438 17.609 ;
     RECT  98.928 17.383 100.962 17.609 ;
     RECT  0.324 17.515 1.17 17.611 ;
     RECT  92.628 17.581 92.646 17.611 ;
     RECT  98.928 17.609 100.35 17.645 ;
     RECT  92.484 17.611 92.646 17.651 ;
     RECT  56.415 17.467 67.626 17.653 ;
     RECT  68.652 17.519 73.062 17.653 ;
     RECT  74.88 17.213 78.606 17.653 ;
     RECT  142.524 16.979 143.442 17.681 ;
     RECT  56.415 17.653 67.734 17.761 ;
     RECT  68.544 17.653 73.062 17.761 ;
     RECT  80.568 17.689 80.586 17.761 ;
     RECT  142.815 17.681 143.442 17.761 ;
     RECT  153.576 17.419 153.897 17.761 ;
     RECT  118.872 17.467 118.89 17.887 ;
     RECT  144.612 17.221 145.35 17.923 ;
     RECT  146.484 17.761 146.502 17.923 ;
     RECT  147.312 16.843 148.497 17.923 ;
     RECT  149.328 17.149 152.838 17.923 ;
     RECT  153.576 17.761 153.99 17.923 ;
     RECT  80.532 17.761 80.622 17.959 ;
     RECT  0.108 17.611 1.17 17.987 ;
     RECT  146.484 17.923 148.497 17.987 ;
     RECT  104.904 17.483 105.297 17.995 ;
     RECT  91.26 16.609 91.278 18.031 ;
     RECT  80.46 17.959 80.622 18.121 ;
     RECT  74.88 17.653 78.678 18.157 ;
     RECT  80.172 18.121 80.622 18.157 ;
     RECT  118.008 17.491 118.026 18.157 ;
     RECT  146.556 17.987 148.497 18.221 ;
     RECT  2.304 17.455 55.494 18.229 ;
     RECT  56.415 17.761 73.062 18.229 ;
     RECT  104.724 17.995 105.297 18.229 ;
     RECT  74.772 18.157 78.678 18.235 ;
     RECT  79.524 18.157 80.622 18.235 ;
     RECT  2.304 18.229 73.062 18.257 ;
     RECT  102.708 17.581 102.726 18.265 ;
     RECT  149.328 17.923 153.99 18.265 ;
     RECT  92.628 17.651 92.646 18.293 ;
     RECT  55.476 18.257 73.062 18.301 ;
     RECT  102.636 18.265 102.726 18.301 ;
     RECT  117.864 18.157 118.026 18.301 ;
     RECT  55.476 18.301 73.17 18.379 ;
     RECT  74.376 18.235 80.622 18.379 ;
     RECT  101.736 18.229 101.754 18.391 ;
     RECT  81.468 18.301 81.558 18.419 ;
     RECT  55.476 18.379 80.622 18.427 ;
     RECT  115.2 7.123 116.097 18.427 ;
     RECT  117.864 18.301 118.062 18.427 ;
     RECT  118.8 17.887 118.89 18.427 ;
     RECT  55.476 18.427 80.73 18.464 ;
     RECT  81.468 18.419 81.522 18.491 ;
     RECT  99.615 17.645 100.35 18.499 ;
     RECT  101.376 18.391 101.754 18.499 ;
     RECT  99.615 18.499 101.754 18.535 ;
     RECT  102.492 18.301 102.726 18.535 ;
     RECT  104.724 18.229 105.894 18.535 ;
     RECT  98.604 18.427 98.694 18.563 ;
     RECT  142.815 17.761 143.658 18.563 ;
     RECT  1.152 17.987 1.17 18.571 ;
     RECT  117.864 18.427 118.89 18.571 ;
     RECT  114.588 18.427 116.097 18.599 ;
     RECT  104.724 18.535 105.966 18.661 ;
     RECT  147.168 18.221 148.497 18.661 ;
     RECT  149.328 18.265 154.638 18.661 ;
     RECT  55.476 18.464 80.658 18.689 ;
     RECT  81.504 18.491 81.522 18.689 ;
     RECT  99.615 18.535 102.726 18.697 ;
     RECT  103.788 17.371 103.806 18.697 ;
     RECT  123.516 14.203 123.534 18.763 ;
     RECT  107.388 18.733 107.406 18.769 ;
     RECT  0.108 17.987 0.162 18.811 ;
     RECT  99.615 18.697 103.806 18.841 ;
     RECT  104.652 18.661 106.362 18.841 ;
     RECT  144.612 17.923 145.638 18.841 ;
     RECT  0.108 18.811 0.198 18.859 ;
     RECT  1.152 18.571 1.206 18.959 ;
     RECT  99.615 18.841 106.362 18.959 ;
     RECT  117.684 18.571 118.89 18.959 ;
     RECT  0.108 18.859 0.342 18.967 ;
     RECT  2.304 18.257 54.63 19.003 ;
     RECT  55.476 18.689 63.054 19.003 ;
     RECT  91.224 18.031 91.278 19.003 ;
     RECT  117.684 18.959 117.81 19.003 ;
     RECT  107.388 18.769 107.694 19.075 ;
     RECT  0.108 18.967 0.378 19.085 ;
     RECT  84.96 19.003 84.978 19.099 ;
     RECT  88.815 15.728 89.097 19.111 ;
     RECT  91.224 19.003 91.746 19.111 ;
     RECT  107.388 19.075 107.874 19.111 ;
     RECT  83.052 16.871 84.222 19.201 ;
     RECT  84.96 19.099 85.05 19.201 ;
     RECT  147.168 18.661 154.638 19.201 ;
     RECT  90.864 19.111 91.746 19.229 ;
     RECT  107.388 19.111 107.946 19.229 ;
     RECT  117.504 19.003 117.81 19.229 ;
     RECT  118.548 18.959 118.89 19.229 ;
     RECT  144.216 18.841 145.638 19.229 ;
     RECT  82.872 19.201 85.05 19.237 ;
     RECT  64.044 18.689 80.658 19.273 ;
     RECT  82.8 19.237 85.05 19.273 ;
     RECT  96.696 19.201 96.714 19.277 ;
     RECT  145.116 19.229 145.638 19.301 ;
     RECT  82.8 19.273 85.086 19.309 ;
     RECT  88.02 19.111 88.038 19.309 ;
     RECT  88.815 19.111 89.226 19.309 ;
     RECT  99.615 18.959 106.29 19.337 ;
     RECT  64.044 19.273 80.694 19.373 ;
     RECT  91.26 19.229 91.746 19.373 ;
     RECT  102.168 19.337 106.29 19.373 ;
     RECT  107.388 19.229 107.874 19.373 ;
     RECT  117.576 19.229 117.81 19.373 ;
     RECT  146.484 19.201 154.638 19.373 ;
     RECT  82.656 19.309 85.086 19.381 ;
     RECT  99.615 19.337 101.07 19.381 ;
     RECT  1.188 18.959 1.206 19.409 ;
     RECT  2.304 19.003 63.054 19.471 ;
     RECT  64.044 19.373 68.094 19.471 ;
     RECT  98.676 18.563 98.694 19.471 ;
     RECT  99.576 19.381 101.07 19.471 ;
     RECT  81.432 19.381 81.45 19.507 ;
     RECT  82.26 19.381 85.086 19.507 ;
     RECT  97.92 19.381 97.938 19.543 ;
     RECT  98.676 19.471 101.07 19.543 ;
     RECT  90 19.309 90.018 19.579 ;
     RECT  107.424 19.373 107.874 19.607 ;
     RECT  68.976 19.373 80.694 19.651 ;
     RECT  81.432 19.507 85.086 19.651 ;
     RECT  87.012 19.543 87.03 19.651 ;
     RECT  97.92 19.543 101.07 19.651 ;
     RECT  97.884 19.651 101.07 19.723 ;
     RECT  117.576 19.373 117.63 19.769 ;
     RECT  86.796 19.651 87.03 19.777 ;
     RECT  88.02 19.309 89.226 19.777 ;
     RECT  137.415 7.997 137.697 19.777 ;
     RECT  117.612 19.769 117.63 19.805 ;
     RECT  144.216 19.229 144.234 19.805 ;
     RECT  68.976 19.651 85.086 19.849 ;
     RECT  86.796 19.777 89.226 19.849 ;
     RECT  90 19.579 90.234 19.849 ;
     RECT  110.415 15.725 110.697 20.005 ;
     RECT  86.004 19.003 86.022 20.011 ;
     RECT  86.796 19.849 90.234 20.011 ;
     RECT  94.215 2.413 94.497 20.011 ;
     RECT  132.015 15.728 132.297 20.011 ;
     RECT  142.815 18.563 143.097 20.011 ;
     RECT  110.304 20.005 110.697 20.045 ;
     RECT  96.3 19.885 96.318 20.047 ;
     RECT  131.904 20.011 132.297 20.048 ;
     RECT  142.704 20.011 143.097 20.048 ;
     RECT  86.004 20.011 90.234 20.059 ;
     RECT  93.312 20.047 93.33 20.083 ;
     RECT  96.3 20.047 96.966 20.083 ;
     RECT  102.24 19.373 106.29 20.083 ;
     RECT  68.976 19.849 85.158 20.111 ;
     RECT  85.968 20.059 90.234 20.119 ;
     RECT  91.26 19.373 91.566 20.119 ;
     RECT  92.592 20.083 93.33 20.119 ;
     RECT  94.215 20.011 95.094 20.119 ;
     RECT  97.812 19.723 101.07 20.119 ;
     RECT  76.356 20.111 85.158 20.147 ;
     RECT  1.152 20.107 1.17 20.155 ;
     RECT  85.968 20.119 91.566 20.155 ;
     RECT  94.215 20.119 95.562 20.155 ;
     RECT  96.3 20.083 97.038 20.155 ;
     RECT  97.812 20.119 101.214 20.155 ;
     RECT  2.304 19.471 68.094 20.191 ;
     RECT  68.976 20.111 75.618 20.191 ;
     RECT  85.968 20.155 91.602 20.191 ;
     RECT  102.24 20.083 106.614 20.191 ;
     RECT  107.424 19.607 107.73 20.191 ;
     RECT  137.415 19.777 137.97 20.219 ;
     RECT  94.215 20.155 97.038 20.281 ;
     RECT  97.812 20.155 101.25 20.281 ;
     RECT  102.24 20.191 107.73 20.281 ;
     RECT  94.215 20.281 107.73 20.309 ;
     RECT  1.152 20.155 1.278 20.425 ;
     RECT  2.304 20.191 75.618 20.425 ;
     RECT  145.62 19.301 145.638 20.453 ;
     RECT  92.556 20.119 93.33 20.461 ;
     RECT  85.932 20.191 91.602 20.491 ;
     RECT  92.52 20.461 93.33 20.491 ;
     RECT  94.215 20.309 96.498 20.491 ;
     RECT  76.392 20.147 85.158 20.539 ;
     RECT  85.932 20.491 96.498 20.539 ;
     RECT  1.152 20.425 75.618 20.579 ;
     RECT  115.2 18.599 116.097 20.579 ;
     RECT  97.524 20.309 107.73 20.587 ;
     RECT  1.152 20.579 47.034 20.615 ;
     RECT  97.524 20.587 108.126 20.623 ;
     RECT  76.392 20.539 96.498 20.687 ;
     RECT  0.108 19.085 0.198 20.695 ;
     RECT  1.152 20.615 46.998 20.695 ;
     RECT  97.524 20.623 108.234 20.695 ;
     RECT  0.108 20.695 46.998 20.717 ;
     RECT  97.524 20.695 108.342 20.723 ;
     RECT  0.108 20.717 1.17 20.813 ;
     RECT  123.3 18.763 123.534 20.821 ;
     RECT  82.548 20.687 96.498 20.849 ;
     RECT  97.524 20.723 103.086 20.849 ;
     RECT  82.584 20.849 91.602 20.885 ;
     RECT  98.46 20.849 103.05 20.885 ;
     RECT  82.584 20.885 89.478 20.921 ;
     RECT  47.844 20.579 75.618 20.923 ;
     RECT  76.392 20.687 81.486 20.923 ;
     RECT  123.3 20.821 124.038 20.923 ;
     RECT  142.815 20.048 143.097 20.929 ;
     RECT  47.844 20.923 81.486 20.957 ;
     RECT  82.584 20.921 87.714 20.957 ;
     RECT  88.524 20.921 89.478 20.957 ;
     RECT  90.216 20.885 91.602 20.957 ;
     RECT  47.844 20.957 76.41 20.993 ;
     RECT  77.184 20.957 80.694 20.993 ;
     RECT  88.704 20.957 89.478 20.993 ;
     RECT  90.684 20.957 91.602 20.993 ;
     RECT  98.46 20.885 102.942 20.993 ;
     RECT  47.844 20.993 75.474 21.005 ;
     RECT  98.46 20.993 101.646 21.005 ;
     RECT  47.844 21.005 72.99 21.029 ;
     RECT  100.728 21.005 101.646 21.029 ;
     RECT  102.384 20.993 102.942 21.029 ;
     RECT  123.3 20.923 124.326 21.029 ;
     RECT  52.236 21.029 72.99 21.053 ;
     RECT  90.864 20.993 91.602 21.053 ;
     RECT  121.032 16.501 121.554 21.091 ;
     RECT  137.415 20.219 137.697 21.091 ;
     RECT  0.108 20.813 0.162 21.101 ;
     RECT  103.824 20.723 108.342 21.115 ;
     RECT  126.324 14.155 126.897 21.115 ;
     RECT  142.56 20.929 143.097 21.115 ;
     RECT  52.236 21.053 59.31 21.119 ;
     RECT  63.18 21.053 72.954 21.119 ;
     RECT  73.98 21.005 75.474 21.119 ;
     RECT  82.584 20.957 87.426 21.119 ;
     RECT  123.3 21.029 123.678 21.119 ;
     RECT  126.324 21.115 127.098 21.119 ;
     RECT  125.208 21.091 125.226 21.149 ;
     RECT  63.18 21.119 63.81 21.155 ;
     RECT  64.8 21.119 72.954 21.155 ;
     RECT  82.584 21.119 87.354 21.155 ;
     RECT  92.376 20.849 96.498 21.155 ;
     RECT  97.488 21.115 97.506 21.155 ;
     RECT  132.015 20.048 132.297 21.163 ;
     RECT  141.408 20.107 141.426 21.163 ;
     RECT  92.376 21.155 95.814 21.191 ;
     RECT  114.948 20.695 114.966 21.199 ;
     RECT  126.396 21.119 127.098 21.199 ;
     RECT  131.976 21.163 132.297 21.199 ;
     RECT  138.564 21.163 138.582 21.199 ;
     RECT  141.408 21.163 141.57 21.199 ;
     RECT  114.66 21.199 114.966 21.211 ;
     RECT  115.704 20.579 116.097 21.211 ;
     RECT  118.872 19.229 118.89 21.211 ;
     RECT  122.616 21.163 122.634 21.211 ;
     RECT  56.34 21.119 59.31 21.227 ;
     RECT  103.824 21.115 108.558 21.235 ;
     RECT  144.216 21.115 144.234 21.235 ;
     RECT  103.824 21.235 108.702 21.259 ;
     RECT  2.268 20.717 46.998 21.263 ;
     RECT  119.664 21.091 119.682 21.271 ;
     RECT  121.032 21.091 121.626 21.271 ;
     RECT  131.94 21.199 132.297 21.271 ;
     RECT  137.016 21.091 137.697 21.271 ;
     RECT  147.168 19.373 154.638 21.271 ;
     RECT  103.824 21.259 108.918 21.293 ;
     RECT  81.468 20.957 81.486 21.299 ;
     RECT  98.46 21.005 99.897 21.299 ;
     RECT  101.412 21.029 101.646 21.299 ;
     RECT  126.396 21.199 127.386 21.299 ;
     RECT  110.415 20.045 110.697 21.307 ;
     RECT  130.608 21.163 130.626 21.307 ;
     RECT  131.904 21.271 132.297 21.307 ;
     RECT  134.64 21.199 134.658 21.307 ;
     RECT  136.548 21.271 137.697 21.307 ;
     RECT  141.336 21.199 141.57 21.307 ;
     RECT  142.524 21.115 143.097 21.307 ;
     RECT  2.268 21.263 36.27 21.341 ;
     RECT  114.588 21.211 114.966 21.341 ;
     RECT  118.584 21.211 118.89 21.341 ;
     RECT  60.048 21.053 62.097 21.347 ;
     RECT  64.8 21.155 72.897 21.347 ;
     RECT  88.704 20.993 89.097 21.347 ;
     RECT  99.504 21.299 99.897 21.347 ;
     RECT  115.704 21.211 116.19 21.347 ;
     RECT  138.564 21.199 138.618 21.355 ;
     RECT  141.336 21.307 143.097 21.355 ;
     RECT  126.54 21.299 127.386 21.361 ;
     RECT  128.268 14.683 128.286 21.361 ;
     RECT  131.904 21.307 132.39 21.361 ;
     RECT  144.18 21.235 144.234 21.361 ;
     RECT  2.268 21.341 36.018 21.389 ;
     RECT  37.008 21.263 46.998 21.389 ;
     RECT  47.844 21.029 51.39 21.389 ;
     RECT  56.34 21.227 58.914 21.389 ;
     RECT  60.048 21.347 61.905 21.389 ;
     RECT  64.8 21.347 72.81 21.389 ;
     RECT  74.304 21.119 75.474 21.389 ;
     RECT  82.584 21.155 84.222 21.389 ;
     RECT  102.564 21.029 102.906 21.389 ;
     RECT  103.824 21.293 106.83 21.389 ;
     RECT  107.748 21.293 108.918 21.389 ;
     RECT  115.704 21.347 115.905 21.389 ;
     RECT  118.62 21.341 118.89 21.389 ;
     RECT  120.78 21.271 121.626 21.389 ;
     RECT  123.516 21.119 123.678 21.389 ;
     RECT  136.548 21.307 137.79 21.389 ;
     RECT  141.336 21.355 143.19 21.389 ;
     RECT  49.932 21.389 51.39 21.395 ;
     RECT  142.524 21.389 143.19 21.395 ;
     RECT  111.636 21.211 111.654 21.397 ;
     RECT  129.168 21.163 129.186 21.397 ;
     RECT  130.536 21.307 130.626 21.397 ;
     RECT  138.528 21.355 138.618 21.397 ;
     RECT  144.108 21.361 144.234 21.397 ;
     RECT  110.415 21.307 110.79 21.403 ;
     RECT  134.64 21.307 134.694 21.403 ;
     RECT  136.692 21.389 137.79 21.403 ;
     RECT  138.528 21.397 138.654 21.403 ;
     RECT  2.268 21.389 35.91 21.425 ;
     RECT  37.08 21.389 46.998 21.425 ;
     RECT  60.048 21.389 61.002 21.425 ;
     RECT  64.8 21.389 65.142 21.425 ;
     RECT  66.708 21.389 69.174 21.425 ;
     RECT  70.812 21.389 72.81 21.425 ;
     RECT  74.304 21.389 75.33 21.425 ;
     RECT  76.248 20.993 76.41 21.425 ;
     RECT  91.332 21.053 91.602 21.425 ;
     RECT  47.844 21.389 49.086 21.433 ;
     RECT  122.544 21.211 122.634 21.433 ;
     RECT  52.236 21.119 55.566 21.437 ;
     RECT  57.42 21.389 58.482 21.437 ;
     RECT  82.584 21.389 84.078 21.437 ;
     RECT  126.54 21.361 128.286 21.437 ;
     RECT  130.536 21.397 130.662 21.437 ;
     RECT  142.524 21.395 142.905 21.437 ;
     RECT  143.928 21.397 144.234 21.437 ;
     RECT  134.532 21.403 134.694 21.451 ;
     RECT  136.692 21.403 138.654 21.451 ;
     RECT  60.12 21.425 61.002 21.461 ;
     RECT  77.904 20.993 80.694 21.461 ;
     RECT  82.584 21.437 83.97 21.461 ;
     RECT  96.588 21.271 96.606 21.461 ;
     RECT  107.784 21.389 108.846 21.461 ;
     RECT  133.992 21.451 134.694 21.469 ;
     RECT  2.268 21.425 35.874 21.497 ;
     RECT  37.08 21.425 46.53 21.497 ;
     RECT  56.34 21.389 56.574 21.497 ;
     RECT  63.18 21.155 63.702 21.497 ;
     RECT  66.708 21.425 67.842 21.497 ;
     RECT  70.812 21.425 71.766 21.497 ;
     RECT  86.004 21.155 87.354 21.497 ;
     RECT  92.412 21.191 95.814 21.497 ;
     RECT  111.636 21.397 111.726 21.497 ;
     RECT  118.62 21.389 118.674 21.497 ;
     RECT  123.588 21.389 123.678 21.497 ;
     RECT  129.096 21.397 129.186 21.497 ;
     RECT  130.572 21.437 130.662 21.497 ;
     RECT  131.904 21.361 132.642 21.497 ;
     RECT  133.992 21.469 134.73 21.499 ;
     RECT  110.415 21.403 110.898 21.505 ;
     RECT  117.54 21.361 117.558 21.505 ;
     RECT  2.268 21.497 32.454 21.533 ;
     RECT  47.7 21.433 49.086 21.533 ;
     RECT  57.564 21.437 58.482 21.533 ;
     RECT  82.728 21.461 83.97 21.533 ;
     RECT  97.38 21.271 97.398 21.533 ;
     RECT  103.932 21.389 106.83 21.533 ;
     RECT  118.656 21.497 118.674 21.533 ;
     RECT  110.415 21.505 111.33 21.541 ;
     RECT  114.624 21.341 114.966 21.541 ;
     RECT  42.408 21.497 46.53 21.542 ;
     RECT  82.728 21.533 83.862 21.542 ;
     RECT  2.268 21.533 31.446 21.569 ;
     RECT  32.292 21.533 32.454 21.569 ;
     RECT  33.228 21.497 35.874 21.569 ;
     RECT  37.08 21.497 41.526 21.569 ;
     RECT  42.444 21.542 46.53 21.569 ;
     RECT  60.12 21.461 60.39 21.569 ;
     RECT  63.288 21.497 63.702 21.569 ;
     RECT  64.8 21.425 65.106 21.569 ;
     RECT  66.708 21.497 67.305 21.569 ;
     RECT  71.532 21.497 71.55 21.569 ;
     RECT  76.392 21.425 76.41 21.569 ;
     RECT  103.932 21.533 105.105 21.569 ;
     RECT  106.02 21.533 106.83 21.569 ;
     RECT  133.668 21.499 134.73 21.569 ;
     RECT  136.692 21.451 138.69 21.569 ;
     RECT  29.34 21.569 31.266 21.581 ;
     RECT  33.372 21.569 35.262 21.581 ;
     RECT  37.512 21.569 41.526 21.581 ;
     RECT  42.444 21.569 45.882 21.581 ;
     RECT  47.7 21.533 48.978 21.581 ;
     RECT  52.236 21.437 52.578 21.581 ;
     RECT  72.504 21.425 72.81 21.581 ;
     RECT  77.904 21.461 78.75 21.581 ;
     RECT  88.704 21.347 89.01 21.581 ;
     RECT  99.504 21.347 99.81 21.581 ;
     RECT  106.02 21.569 106.722 21.581 ;
     RECT  110.304 21.541 111.33 21.581 ;
     RECT  114.624 21.541 115.074 21.581 ;
     RECT  134.532 21.569 134.73 21.581 ;
     RECT  142.56 21.437 142.905 21.581 ;
     RECT  143.928 21.437 143.946 21.581 ;
     RECT  56.415 21.497 56.574 21.617 ;
     RECT  61.815 21.389 61.905 21.617 ;
     RECT  67.032 21.569 67.305 21.617 ;
     RECT  72.615 21.581 72.705 21.617 ;
     RECT  78.015 21.581 78.75 21.617 ;
     RECT  82.728 21.542 83.826 21.617 ;
     RECT  88.815 21.581 88.905 21.617 ;
     RECT  99.615 21.581 99.705 21.617 ;
     RECT  104.364 21.569 105.105 21.617 ;
     RECT  110.415 21.581 110.97 21.617 ;
     RECT  115.815 21.389 115.905 21.617 ;
     RECT  126.54 21.437 127.926 21.617 ;
     RECT  136.692 21.569 137.574 21.617 ;
     RECT  142.632 21.581 142.905 21.617 ;
     RECT  33.732 21.581 35.262 21.629 ;
     RECT  37.512 21.581 41.418 21.629 ;
     RECT  53.316 21.437 55.206 21.629 ;
     RECT  131.904 21.497 132.282 21.631 ;
     RECT  145.98 20.857 146.034 21.631 ;
     RECT  32.328 21.569 32.454 21.659 ;
     RECT  33.732 21.629 35.082 21.659 ;
     RECT  49.932 21.395 51.354 21.659 ;
     RECT  52.488 21.581 52.578 21.659 ;
     RECT  53.316 21.629 53.73 21.659 ;
     RECT  57.564 21.533 57.654 21.659 ;
     RECT  60.12 21.569 60.21 21.659 ;
     RECT  74.304 21.425 74.97 21.659 ;
     RECT  82.728 21.617 82.746 21.659 ;
     RECT  86.004 21.497 86.742 21.659 ;
     RECT  92.412 21.497 94.554 21.659 ;
     RECT  95.796 21.497 95.814 21.659 ;
     RECT  98.46 21.299 98.694 21.659 ;
     RECT  101.412 21.299 101.502 21.659 ;
     RECT  102.672 21.389 102.906 21.659 ;
     RECT  110.592 21.617 110.97 21.659 ;
     RECT  114.624 21.581 114.966 21.659 ;
     RECT  122.436 21.433 122.634 21.659 ;
     RECT  123.66 21.497 123.678 21.659 ;
     RECT  134.64 21.581 134.73 21.659 ;
     RECT  137.556 21.617 137.574 21.659 ;
     RECT  138.6 21.569 138.69 21.659 ;
     RECT  142.632 21.617 142.722 21.659 ;
     RECT  33.732 21.659 35.01 21.677 ;
     RECT  47.7 21.581 48.798 21.677 ;
     RECT  104.364 21.617 104.382 21.677 ;
     RECT  106.02 21.581 106.434 21.677 ;
     RECT  138.672 21.659 138.69 21.677 ;
     RECT  37.512 21.629 39.582 21.695 ;
     RECT  47.844 21.677 48.798 21.695 ;
     RECT  145.944 21.631 146.034 21.703 ;
     RECT  146.952 21.271 154.638 21.703 ;
     RECT  29.34 21.581 30.762 21.725 ;
     RECT  37.512 21.695 39.402 21.725 ;
     RECT  40.356 21.629 41.058 21.725 ;
     RECT  50.004 21.659 51.354 21.725 ;
     RECT  54.54 21.629 55.206 21.725 ;
     RECT  29.34 21.725 29.358 21.731 ;
     RECT  32.364 21.659 32.454 21.731 ;
     RECT  37.512 21.725 38.358 21.731 ;
     RECT  42.516 21.581 45.882 21.731 ;
     RECT  47.844 21.695 48.114 21.731 ;
     RECT  92.412 21.659 93.762 21.731 ;
     RECT  131.832 21.631 132.282 21.731 ;
     RECT  33.732 21.677 34.65 21.767 ;
     RECT  54.54 21.725 54.882 21.767 ;
     RECT  92.412 21.731 93.078 21.767 ;
     RECT  126.54 21.617 126.558 21.767 ;
     RECT  128.772 21.631 128.79 21.767 ;
     RECT  40.464 21.725 41.058 21.773 ;
     RECT  110.592 21.659 110.61 21.773 ;
     RECT  2.268 21.569 28.494 21.803 ;
     RECT  40.464 21.773 41.022 21.803 ;
     RECT  51.336 21.725 51.354 21.803 ;
     RECT  33.876 21.767 34.65 21.821 ;
     RECT  37.512 21.731 38.142 21.821 ;
     RECT  45.288 21.731 45.882 21.821 ;
     RECT  136.692 21.617 136.71 21.821 ;
     RECT  0.108 21.101 0.126 21.835 ;
     RECT  30.168 21.725 30.762 21.839 ;
     RECT  33.876 21.821 34.542 21.839 ;
     RECT  42.516 21.731 44.262 21.839 ;
     RECT  45.288 21.821 45.594 21.839 ;
     RECT  50.04 21.725 50.346 21.839 ;
     RECT  145.944 21.703 154.638 21.839 ;
     RECT  27.9 21.803 28.494 21.869 ;
     RECT  127.368 21.617 127.926 21.869 ;
     RECT  27.9 21.869 28.134 21.884 ;
     RECT  45.288 21.839 45.414 21.884 ;
     RECT  47.844 21.731 47.862 21.884 ;
     RECT  120.78 21.389 121.554 21.917 ;
     RECT  32.436 21.731 32.454 21.929 ;
     RECT  78.732 21.617 78.75 21.929 ;
     RECT  0.108 21.835 0.162 21.965 ;
     RECT  58.464 21.533 58.482 21.965 ;
     RECT  79.668 21.461 80.694 21.965 ;
     RECT  101.412 21.659 101.43 22.001 ;
     RECT  50.328 21.839 50.346 22.013 ;
     RECT  64.872 21.569 65.034 22.013 ;
     RECT  67.032 21.617 67.05 22.037 ;
     RECT  106.02 21.677 106.362 22.037 ;
     RECT  106.02 22.037 106.038 22.061 ;
     RECT  39.384 21.725 39.402 22.073 ;
     RECT  127.368 21.869 127.386 22.109 ;
     RECT  131.94 21.731 131.958 22.154 ;
     RECT  86.004 21.659 86.49 22.199 ;
     RECT  42.624 21.839 44.262 22.205 ;
     RECT  80.676 21.965 80.694 22.235 ;
     RECT  74.952 21.659 74.97 22.271 ;
     RECT  79.668 21.965 79.686 22.271 ;
     RECT  53.316 21.659 53.442 22.307 ;
     RECT  54.54 21.767 54.558 22.307 ;
     RECT  98.46 21.659 98.622 22.307 ;
     RECT  42.696 22.205 44.262 22.343 ;
     RECT  53.316 22.307 53.334 22.343 ;
     RECT  28.116 21.884 28.134 22.379 ;
     RECT  98.604 22.307 98.622 22.379 ;
     RECT  1.152 20.813 1.17 22.411 ;
     RECT  92.412 21.767 92.97 22.445 ;
     RECT  116.784 21.505 117.558 22.541 ;
     RECT  119.664 21.271 119.718 22.541 ;
     RECT  91.332 21.425 91.494 22.577 ;
     RECT  107.82 21.461 108.846 22.577 ;
     RECT  117.54 22.541 117.558 22.589 ;
     RECT  68.58 21.425 68.598 22.613 ;
     RECT  116.784 22.541 116.802 22.613 ;
     RECT  44.244 22.343 44.262 22.649 ;
     RECT  122.616 21.659 122.634 22.649 ;
     RECT  120.78 21.917 121.158 22.694 ;
     RECT  102.888 21.659 102.906 22.733 ;
     RECT  40.464 21.803 40.482 22.739 ;
     RECT  145.98 21.839 154.638 22.739 ;
     RECT  2.268 21.803 27.018 22.775 ;
     RECT  91.332 22.577 91.35 22.781 ;
     RECT  27 22.775 27.018 22.795 ;
     RECT  30.744 21.839 30.762 22.811 ;
     RECT  146.484 22.739 154.638 22.811 ;
     RECT  2.268 22.775 26.01 22.829 ;
     RECT  27 22.795 27.126 22.829 ;
     RECT  37.512 21.821 37.53 22.847 ;
     RECT  56.556 21.617 56.574 22.847 ;
     RECT  108.828 22.577 108.846 22.877 ;
     RECT  107.82 22.577 108.054 22.883 ;
     RECT  27.108 22.829 27.126 22.891 ;
     RECT  121.14 22.694 121.158 22.919 ;
     RECT  0.144 21.965 0.162 22.981 ;
     RECT  1.152 22.411 1.206 22.981 ;
     RECT  35.964 23.083 35.982 23.359 ;
     RECT  30.168 23.179 30.186 23.371 ;
     RECT  0.144 22.981 1.206 23.459 ;
     RECT  27.108 22.891 27.234 23.467 ;
     RECT  2.304 22.829 26.01 23.76 ;
     RECT  27.108 23.467 27.954 23.76 ;
     RECT  30.132 23.371 30.186 23.76 ;
     RECT  31.86 23.371 31.878 23.76 ;
     RECT  34.524 21.839 34.542 23.76 ;
     RECT  35.892 23.359 35.982 23.76 ;
     RECT  42.696 22.343 43.506 23.76 ;
     RECT  45.396 21.884 45.414 23.76 ;
     RECT  63.288 21.569 63.486 23.76 ;
     RECT  65.016 22.013 65.034 23.76 ;
     RECT  83.808 21.617 83.826 23.76 ;
     RECT  86.472 22.199 86.49 23.76 ;
     RECT  92.484 22.445 92.97 23.76 ;
     RECT  107.82 22.883 107.838 23.76 ;
     RECT  114.948 21.659 114.966 23.76 ;
     RECT  141.336 21.389 141.354 23.76 ;
     RECT  146.556 22.811 154.638 23.76 ;
     RECT  2.304 23.76 154.638 23.971 ;
     RECT  0.144 23.459 0.594 24.043 ;
     RECT  0.108 24.043 0.594 24.197 ;
     RECT  0.216 24.197 0.594 24.221 ;
     RECT  2.268 23.971 154.638 24.619 ;
     RECT  2.232 24.619 154.638 24.665 ;
     RECT  0.324 24.221 0.594 25.099 ;
     RECT  0.144 25.099 0.594 25.195 ;
     RECT  2.304 24.665 154.638 25.555 ;
     RECT  2.304 25.555 154.674 25.963 ;
     RECT  2.268 25.963 154.674 26.051 ;
     RECT  0.144 25.195 1.17 26.107 ;
     RECT  0.144 26.107 1.278 26.539 ;
     RECT  0.108 26.539 1.278 26.663 ;
     RECT  0.144 26.663 1.278 26.923 ;
     RECT  0.144 26.923 1.386 27.149 ;
     RECT  2.304 26.051 154.674 27.629 ;
     RECT  0.144 27.149 0.846 27.931 ;
     RECT  0.144 27.931 1.242 28.066 ;
     RECT  0.108 28.066 1.242 28.205 ;
     RECT  0.108 28.205 1.17 28.556 ;
     RECT  2.304 27.629 148.662 29.191 ;
     RECT  149.472 27.629 154.674 29.191 ;
     RECT  0.144 28.556 1.17 29.227 ;
     RECT  0.144 29.227 1.278 29.323 ;
     RECT  0.108 29.323 1.278 29.357 ;
     RECT  2.304 29.191 154.674 29.419 ;
     RECT  0.108 29.357 1.17 29.489 ;
     RECT  0.144 29.489 1.17 29.501 ;
     RECT  0.144 29.501 0.846 29.759 ;
     RECT  2.268 29.419 154.674 29.795 ;
     RECT  0.144 29.759 0.414 30.479 ;
     RECT  0.144 30.479 0.342 30.509 ;
     RECT  2.304 29.795 154.674 30.619 ;
     RECT  1.98 30.619 154.674 30.685 ;
     RECT  1.98 30.685 154.89 31.109 ;
     RECT  0.144 30.509 0.234 31.153 ;
     RECT  0.108 31.153 0.234 31.373 ;
     RECT  0.144 31.373 0.234 31.435 ;
     RECT  1.98 31.109 154.386 31.661 ;
     RECT  1.152 31.627 1.17 31.675 ;
     RECT  1.98 31.661 148.806 31.675 ;
     RECT  0.144 31.435 0.27 31.709 ;
     RECT  0.144 31.709 0.162 32.203 ;
     RECT  1.152 31.675 148.806 32.395 ;
     RECT  149.58 31.661 154.386 32.491 ;
     RECT  0.108 32.203 0.162 32.503 ;
     RECT  1.116 32.395 148.806 32.503 ;
     RECT  0.108 32.503 148.806 32.525 ;
     RECT  0.108 32.525 148.122 32.531 ;
     RECT  149.544 32.491 154.386 32.531 ;
     RECT  0.576 32.531 148.122 32.729 ;
     RECT  149.688 32.531 154.386 32.729 ;
     RECT  0.576 32.729 23.994 32.801 ;
     RECT  1.98 32.801 23.994 33.269 ;
     RECT  149.76 32.729 154.386 33.307 ;
     RECT  0.576 32.801 1.17 33.341 ;
     RECT  1.116 33.341 1.17 33.389 ;
     RECT  168.552 22.585 168.57 33.421 ;
     RECT  1.98 33.269 23.958 33.539 ;
     RECT  149.76 33.307 154.422 33.539 ;
     RECT  168.3 33.421 168.57 33.539 ;
     RECT  168.3 33.539 168.318 33.575 ;
     RECT  0.108 33.355 0.342 33.581 ;
     RECT  149.76 33.539 154.386 33.691 ;
     RECT  20.304 33.539 23.958 33.809 ;
     RECT  155.196 33.691 155.214 33.845 ;
     RECT  20.448 33.809 23.958 33.965 ;
     RECT  155.124 33.883 155.142 33.989 ;
     RECT  1.98 33.539 19.53 34.079 ;
     RECT  1.116 33.389 1.134 34.219 ;
     RECT  1.98 34.079 19.278 34.219 ;
     RECT  0.108 33.581 0.198 34.315 ;
     RECT  149.58 33.691 154.386 34.349 ;
     RECT  20.448 33.965 23.706 34.627 ;
     RECT  20.376 34.627 23.706 34.637 ;
     RECT  24.876 32.729 148.122 34.795 ;
     RECT  20.376 34.637 22.698 34.861 ;
     RECT  149.688 34.349 154.386 34.861 ;
     RECT  155.808 34.699 155.826 34.888 ;
     RECT  155.664 34.888 155.826 34.889 ;
     RECT  0.108 34.315 0.342 34.897 ;
     RECT  155.664 34.889 155.682 34.925 ;
     RECT  149.688 34.861 154.602 34.973 ;
     RECT  0.108 34.897 0.378 35.021 ;
     RECT  154.728 34.987 154.746 35.033 ;
     RECT  1.116 34.219 19.278 35.041 ;
     RECT  20.232 34.861 22.698 35.041 ;
     RECT  1.116 35.041 22.698 35.339 ;
     RECT  24.48 34.795 148.122 35.429 ;
     RECT  163.152 22.513 163.17 35.429 ;
     RECT  23.616 34.637 23.706 35.467 ;
     RECT  1.692 35.339 22.698 35.473 ;
     RECT  23.616 35.467 23.922 35.473 ;
     RECT  149.688 34.973 153.897 35.707 ;
     RECT  149.688 35.707 154.098 35.743 ;
     RECT  149.58 35.743 154.098 35.755 ;
     RECT  1.692 35.473 23.922 35.771 ;
     RECT  149.364 35.755 154.098 35.843 ;
     RECT  155.52 35.041 155.538 35.851 ;
     RECT  0.108 35.021 0.342 35.924 ;
     RECT  0.144 35.924 0.342 36.077 ;
     RECT  160.164 35.545 160.182 36.113 ;
     RECT  154.944 35.851 155.538 36.121 ;
     RECT  2.304 35.771 23.922 36.239 ;
     RECT  1.224 36.283 1.242 36.331 ;
     RECT  1.152 36.331 1.242 36.461 ;
     RECT  149.364 35.843 153.897 36.653 ;
     RECT  149.4 36.653 153.897 36.779 ;
     RECT  0.144 36.077 0.27 36.845 ;
     RECT  0.144 36.845 0.162 36.893 ;
     RECT  24.876 35.429 148.122 36.907 ;
     RECT  149.508 36.779 153.897 37.049 ;
     RECT  24.48 36.907 148.122 37.195 ;
     RECT  2.304 36.239 23.706 37.339 ;
     RECT  24.444 37.195 148.122 37.355 ;
     RECT  1.152 36.461 1.17 37.499 ;
     RECT  24.876 37.355 148.122 37.499 ;
     RECT  1.98 37.339 23.706 37.517 ;
     RECT  149.508 37.049 151.074 37.613 ;
     RECT  0.108 37.291 0.126 37.771 ;
     RECT  149.508 37.613 150.606 37.859 ;
     RECT  0.108 37.771 0.342 37.967 ;
     RECT  149.904 37.859 150.606 38.129 ;
     RECT  0.144 37.967 0.342 38.443 ;
     RECT  2.304 37.517 23.706 38.551 ;
     RECT  150.372 38.129 150.606 38.705 ;
     RECT  0.144 38.443 1.206 38.765 ;
     RECT  0.144 38.765 0.342 38.821 ;
     RECT  0.108 38.821 0.342 38.861 ;
     RECT  2.268 38.551 23.706 38.909 ;
     RECT  0.144 38.861 0.342 39.053 ;
     RECT  1.152 38.765 1.206 39.067 ;
     RECT  0.144 39.053 0.234 39.119 ;
     RECT  168.912 38.443 168.93 39.209 ;
     RECT  1.152 39.067 1.386 39.245 ;
     RECT  151.848 37.049 153.897 39.245 ;
     RECT  0.144 39.119 0.162 39.821 ;
     RECT  0.18 39.883 0.342 40.123 ;
     RECT  24.876 37.499 147.942 40.199 ;
     RECT  0.18 40.123 0.414 40.333 ;
     RECT  1.152 39.245 1.17 40.333 ;
     RECT  0.18 40.333 1.17 40.507 ;
     RECT  0.18 40.507 1.314 40.555 ;
     RECT  0.108 40.555 1.314 40.603 ;
     RECT  0.108 40.603 1.386 40.667 ;
     RECT  0.144 40.667 1.386 40.781 ;
     RECT  158.22 41.071 158.238 41.117 ;
     RECT  24.876 40.199 147.906 41.909 ;
     RECT  162.684 40.171 162.702 41.909 ;
     RECT  154.62 36.121 155.538 41.945 ;
     RECT  154.62 41.945 154.638 42.053 ;
     RECT  0.144 40.781 1.206 42.179 ;
     RECT  0.144 42.179 0.594 42.283 ;
     RECT  0.108 42.283 0.594 42.701 ;
     RECT  0.108 42.701 0.558 43.819 ;
     RECT  0.108 43.819 1.17 44.107 ;
     RECT  0.108 44.107 1.314 44.237 ;
     RECT  149.796 44.299 149.814 44.311 ;
     RECT  0.108 44.237 1.206 44.339 ;
     RECT  149.508 44.311 149.814 44.339 ;
     RECT  149.508 44.339 149.526 44.477 ;
     RECT  0.18 44.339 1.206 45.149 ;
     RECT  0.18 45.149 0.846 45.163 ;
     RECT  2.304 38.909 23.706 46.075 ;
     RECT  152.352 39.245 153.897 46.265 ;
     RECT  149.724 46.741 149.742 46.781 ;
     RECT  150.588 38.705 150.606 46.913 ;
     RECT  0.108 45.163 0.846 47.723 ;
     RECT  0.18 47.723 0.846 48.299 ;
     RECT  24.876 41.909 147.312 48.497 ;
     RECT  0.18 48.299 0.234 48.523 ;
     RECT  1.116 48.427 1.17 48.811 ;
     RECT  0.144 48.523 0.234 49.126 ;
     RECT  0.144 49.126 0.342 49.195 ;
     RECT  0.108 49.195 0.342 49.207 ;
     RECT  1.116 48.811 1.242 49.207 ;
     RECT  0.108 49.207 1.242 49.235 ;
     RECT  155.52 41.945 155.538 49.775 ;
     RECT  1.98 46.075 23.706 50.315 ;
     RECT  0.18 49.235 1.242 50.443 ;
     RECT  150.516 49.711 150.534 50.791 ;
     RECT  152.352 46.265 152.37 50.855 ;
     RECT  0.144 50.443 1.242 50.909 ;
     RECT  0.216 50.909 1.242 50.999 ;
     RECT  150.516 50.791 150.714 51.307 ;
     RECT  150.516 51.307 150.858 51.359 ;
     RECT  0.216 50.999 1.206 51.787 ;
     RECT  0.216 51.787 1.242 52.411 ;
     RECT  1.98 50.315 23.634 52.439 ;
     RECT  0.108 52.411 1.242 52.889 ;
     RECT  150.696 51.359 150.714 52.951 ;
     RECT  0.108 52.889 0.27 52.973 ;
     RECT  150.696 52.951 151.002 52.979 ;
     RECT  150.984 52.979 151.002 53.021 ;
     RECT  1.152 52.889 1.242 53.515 ;
     RECT  1.152 53.515 1.422 53.707 ;
     RECT  2.304 52.439 23.634 53.707 ;
     RECT  0.108 52.973 0.234 53.899 ;
     RECT  0.108 53.899 0.342 53.905 ;
     RECT  0.072 53.905 0.342 54.029 ;
     RECT  0.072 54.029 0.234 54.679 ;
     RECT  0.036 54.679 0.234 54.707 ;
     RECT  1.152 53.707 23.634 54.779 ;
     RECT  0.036 54.707 0.09 55.049 ;
     RECT  1.152 54.779 1.422 55.139 ;
     RECT  1.224 55.139 1.422 55.517 ;
     RECT  1.224 55.517 1.242 55.859 ;
     RECT  0.072 55.049 0.09 55.949 ;
     RECT  2.304 54.779 23.634 56.489 ;
     RECT  150.192 56.641 150.21 56.731 ;
     RECT  150.192 56.731 150.534 56.759 ;
     RECT  167.112 56.641 167.13 56.759 ;
     RECT  150.516 56.759 150.534 56.768 ;
     RECT  156.672 35.041 156.69 56.795 ;
     RECT  2.415 56.489 23.634 61.691 ;
     RECT  2.415 61.691 23.274 62.141 ;
     RECT  2.415 62.141 22.158 62.195 ;
     RECT  16.092 62.195 22.158 62.501 ;
     RECT  2.415 62.195 15.318 62.581 ;
     RECT  16.092 62.501 22.122 62.699 ;
     RECT  16.092 62.699 21.654 62.771 ;
     RECT  16.092 62.771 21.51 62.879 ;
     RECT  2.376 62.581 15.318 63.049 ;
     RECT  16.092 62.879 21.402 63.049 ;
     RECT  2.376 63.049 21.402 63.533 ;
     RECT  2.415 63.533 21.402 63.787 ;
     RECT  22.896 62.141 23.274 63.851 ;
     RECT  2.415 63.787 21.582 64.049 ;
     RECT  2.415 64.049 3.078 64.085 ;
     RECT  3.924 64.049 21.582 64.165 ;
     RECT  3.924 64.165 21.798 64.895 ;
     RECT  22.968 63.851 23.274 65.003 ;
     RECT  4.428 64.895 21.798 65.101 ;
     RECT  4.428 65.101 21.834 65.209 ;
     RECT  4.428 65.209 21.942 65.309 ;
     RECT  4.428 65.309 21.906 65.669 ;
     RECT  4.716 65.669 21.906 65.849 ;
     RECT  4.824 65.849 21.906 65.939 ;
     RECT  4.824 65.939 21.546 66.047 ;
     RECT  15.696 66.047 21.546 66.083 ;
     RECT  15.696 66.083 21.042 66.317 ;
     RECT  4.824 66.047 14.67 66.353 ;
     RECT  4.86 66.353 14.67 66.515 ;
     RECT  22.968 65.003 22.986 66.623 ;
     RECT  4.932 66.515 14.67 66.829 ;
     RECT  15.696 66.317 20.97 66.829 ;
     RECT  4.932 66.829 20.97 67.441 ;
     RECT  4.86 67.441 20.97 67.469 ;
     RECT  19.908 67.469 20.97 67.667 ;
     RECT  19.944 67.667 20.97 67.711 ;
     RECT  4.86 67.469 18.897 67.829 ;
     RECT  4.86 67.829 14.922 67.865 ;
     RECT  15.66 67.829 18.897 68.009 ;
     RECT  4.86 67.865 4.95 68.099 ;
     RECT  5.76 67.865 14.922 68.099 ;
     RECT  4.86 68.099 4.878 68.135 ;
     RECT  19.944 67.711 21.15 68.171 ;
     RECT  5.76 68.099 14.85 68.243 ;
     RECT  15.732 68.009 18.897 68.243 ;
     RECT  19.944 68.171 20.718 68.279 ;
     RECT  5.76 68.243 6.282 68.369 ;
     RECT  7.092 68.243 14.85 68.369 ;
     RECT  15.84 68.243 18.897 68.369 ;
     RECT  16.236 68.369 18.897 68.381 ;
     RECT  5.76 68.369 5.778 68.405 ;
     RECT  9.144 68.369 9.846 68.405 ;
     RECT  10.764 68.369 13.806 68.405 ;
     RECT  16.92 68.381 18.897 68.405 ;
     RECT  19.944 68.279 20.574 68.405 ;
     RECT  9.36 68.405 9.738 68.441 ;
     RECT  17.208 68.405 18.897 68.441 ;
     RECT  20.052 68.405 20.574 68.441 ;
     RECT  13.215 68.405 13.806 68.477 ;
     RECT  20.556 68.441 20.574 68.477 ;
     RECT  14.724 68.369 14.85 68.513 ;
     RECT  17.208 68.441 17.658 68.513 ;
     RECT  9.54 68.441 9.558 68.549 ;
     RECT  17.208 68.513 17.586 68.549 ;
     RECT  10.764 68.405 12.366 68.675 ;
     RECT  14.724 68.513 14.742 68.675 ;
     RECT  10.764 68.675 10.926 68.747 ;
     RECT  10.764 68.747 10.782 68.783 ;
     RECT  17.208 68.549 17.406 68.783 ;
     RECT  11.664 68.675 12.366 68.819 ;
     RECT  7.272 68.369 8.097 68.909 ;
     RECT  11.664 68.819 11.682 68.909 ;
     RECT  25.488 48.497 147.312 86.67 ;
     RECT  123.84 88.699 123.858 88.747 ;
     RECT  128.16 88.747 128.178 88.861 ;
     RECT  123.84 88.747 124.182 88.889 ;
     RECT  128.16 88.861 128.502 88.889 ;
     RECT  128.484 88.889 128.502 88.925 ;
     RECT  24.207 88.813 24.297 89.083 ;
     RECT  29.607 88.813 29.697 89.083 ;
     RECT  35.007 88.813 35.097 89.083 ;
     RECT  40.407 88.813 40.497 89.083 ;
     RECT  45.807 88.813 45.897 89.083 ;
     RECT  51.207 88.813 51.297 89.083 ;
     RECT  56.607 88.813 56.697 89.083 ;
     RECT  62.007 88.813 62.097 89.083 ;
     RECT  67.407 88.813 67.497 89.083 ;
     RECT  72.807 88.813 72.897 89.083 ;
     RECT  78.207 88.813 78.297 89.083 ;
     RECT  83.607 88.813 83.697 89.083 ;
     RECT  89.007 88.813 89.097 89.083 ;
     RECT  94.407 88.813 94.497 89.083 ;
     RECT  99.807 88.813 99.897 89.083 ;
     RECT  105.207 88.813 105.297 89.083 ;
     RECT  110.607 88.813 110.697 89.083 ;
     RECT  116.007 88.813 116.097 89.083 ;
     RECT  121.407 88.813 121.497 89.083 ;
     RECT  126.807 88.813 126.897 89.083 ;
     RECT  132.207 88.813 132.297 89.083 ;
     RECT  137.607 88.813 137.697 89.083 ;
     RECT  143.007 88.813 143.097 89.083 ;
     RECT  148.407 88.813 148.497 89.083 ;
     RECT  2.415 64.085 2.697 107.747 ;
     RECT  7.815 68.909 8.097 107.747 ;
     RECT  13.215 68.477 13.497 107.747 ;
     RECT  18.615 68.441 18.897 107.747 ;
     RECT  24.015 89.083 24.297 107.747 ;
     RECT  29.415 89.083 29.697 107.747 ;
     RECT  34.815 89.083 35.097 107.747 ;
     RECT  40.215 89.083 40.497 107.747 ;
     RECT  45.615 89.083 45.897 107.747 ;
     RECT  51.015 89.083 51.297 107.747 ;
     RECT  56.415 89.083 56.697 107.747 ;
     RECT  61.815 89.083 62.097 107.747 ;
     RECT  67.215 89.083 67.497 107.747 ;
     RECT  72.615 89.083 72.897 107.747 ;
     RECT  78.015 89.083 78.297 107.747 ;
     RECT  83.415 89.083 83.697 107.747 ;
     RECT  88.815 89.083 89.097 107.747 ;
     RECT  94.215 89.083 94.497 107.747 ;
     RECT  99.615 89.083 99.897 107.747 ;
     RECT  105.015 89.083 105.297 107.747 ;
     RECT  110.415 89.083 110.697 107.747 ;
     RECT  115.815 89.083 116.097 107.747 ;
     RECT  121.215 89.083 121.497 107.747 ;
     RECT  126.615 89.083 126.897 107.747 ;
     RECT  132.015 89.083 132.297 107.747 ;
     RECT  137.415 89.083 137.697 107.747 ;
     RECT  142.815 89.083 143.097 107.747 ;
     RECT  148.215 89.083 148.497 107.747 ;
     RECT  153.615 46.265 153.897 107.747 ;
     RECT  159.015 2.413 159.297 107.747 ;
     RECT  164.415 2.413 164.697 107.747 ;
     RECT  169.815 2.413 170.097 107.747 ;
     RECT  2.415 107.747 2.505 108.017 ;
     RECT  7.815 107.747 7.905 108.017 ;
     RECT  13.215 107.747 13.305 108.017 ;
     RECT  18.615 107.747 18.705 108.017 ;
     RECT  24.015 107.747 24.105 108.017 ;
     RECT  29.415 107.747 29.505 108.017 ;
     RECT  34.815 107.747 34.905 108.017 ;
     RECT  40.215 107.747 40.305 108.017 ;
     RECT  45.615 107.747 45.705 108.017 ;
     RECT  51.015 107.747 51.105 108.017 ;
     RECT  56.415 107.747 56.505 108.017 ;
     RECT  61.815 107.747 61.905 108.017 ;
     RECT  67.215 107.747 67.305 108.017 ;
     RECT  72.615 107.747 72.705 108.017 ;
     RECT  78.015 107.747 78.105 108.017 ;
     RECT  83.415 107.747 83.505 108.017 ;
     RECT  88.815 107.747 88.905 108.017 ;
     RECT  94.215 107.747 94.305 108.017 ;
     RECT  99.615 107.747 99.705 108.017 ;
     RECT  105.015 107.747 105.105 108.017 ;
     RECT  110.415 107.747 110.505 108.017 ;
     RECT  115.815 107.747 115.905 108.017 ;
     RECT  121.215 107.747 121.305 108.017 ;
     RECT  126.615 107.747 126.705 108.017 ;
     RECT  132.015 107.747 132.105 108.017 ;
     RECT  137.415 107.747 137.505 108.017 ;
     RECT  142.815 107.747 142.905 108.017 ;
     RECT  148.215 107.747 148.305 108.017 ;
     RECT  153.615 107.747 153.705 108.017 ;
     RECT  159.015 107.747 159.105 108.017 ;
     RECT  164.415 107.747 164.505 108.017 ;
     RECT  169.815 107.747 169.905 108.017 ;
    LAYER M4 ;
     RECT  0.06 1.2 0.137 54.12 ;
     RECT  0.137 1.2 0.353 54.024 ;
     RECT  0.353 1.2 1.253 53.928 ;
     RECT  1.253 1.2 1.469 51.72 ;
     RECT  1.469 1.488 2.293 51.72 ;
     RECT  1.253 52.752 2.293 53.928 ;
     RECT  2.293 1.488 2.408 53.928 ;
     RECT  2.365 63.504 2.408 63.528 ;
     RECT  2.408 1.488 2.512 108.012 ;
     RECT  2.512 1.488 2.704 107.742 ;
     RECT  2.704 58.128 3.413 59.256 ;
     RECT  3.413 58.464 3.485 59.256 ;
     RECT  2.704 63.504 3.913 64.056 ;
     RECT  2.704 57.024 3.953 57.048 ;
     RECT  3.485 58.512 3.985 59.256 ;
     RECT  3.985 58.512 4.057 59.832 ;
     RECT  3.913 61.632 4.273 61.656 ;
     RECT  4.057 58.512 4.451 60.072 ;
     RECT  4.417 65.568 4.601 65.592 ;
     RECT  2.704 1.488 4.633 54.12 ;
     RECT  4.633 1.488 4.673 54.744 ;
     RECT  4.673 54.48 4.745 54.744 ;
     RECT  4.673 1.488 4.817 53.448 ;
     RECT  3.913 63.504 4.961 64.44 ;
     RECT  4.961 63.504 5.101 63.96 ;
     RECT  4.451 60 5.461 60.072 ;
     RECT  4.451 58.512 5.497 58.536 ;
     RECT  5.461 59.52 5.497 60.072 ;
     RECT  5.497 58.512 5.537 60.216 ;
     RECT  4.273 61.584 5.605 61.656 ;
     RECT  5.605 61.584 5.717 62.184 ;
     RECT  5.717 62.16 5.785 62.184 ;
     RECT  5.101 63.264 5.785 63.96 ;
     RECT  5.537 58.656 5.797 60.216 ;
     RECT  5.785 62.16 5.897 63.96 ;
     RECT  4.817 1.584 6.001 53.448 ;
     RECT  4.745 54.48 6.001 54.648 ;
     RECT  4.633 55.824 6.037 55.848 ;
     RECT  5.101 57.024 6.037 57.048 ;
     RECT  5.797 58.656 6.037 60.264 ;
     RECT  6.001 1.584 6.236 54.648 ;
     RECT  6.037 55.824 6.236 57.048 ;
     RECT  5.897 62.16 6.257 62.184 ;
     RECT  4.849 67.824 6.293 67.848 ;
     RECT  6.236 1.584 6.323 57.048 ;
     RECT  6.323 1.584 6.329 54.744 ;
     RECT  5.897 63.264 6.553 63.96 ;
     RECT  6.572 67.776 6.659 67.8 ;
     RECT  6.553 63.936 6.685 63.96 ;
     RECT  6.685 63.936 6.833 64.104 ;
     RECT  6.323 55.824 7.004 57.048 ;
     RECT  7.004 55.824 7.009 57.528 ;
     RECT  6.037 58.656 7.009 60.6 ;
     RECT  6.613 66.672 7.225 66.696 ;
     RECT  6.973 62.496 7.261 62.52 ;
     RECT  6.833 64.08 7.397 64.104 ;
     RECT  6.757 65.376 7.397 65.4 ;
     RECT  7.261 62.448 7.513 62.52 ;
     RECT  7.397 64.08 7.585 65.4 ;
     RECT  6.329 1.968 7.649 54.744 ;
     RECT  7.009 55.824 7.649 60.6 ;
     RECT  7.513 61.632 7.649 62.52 ;
     RECT  7.649 1.968 7.808 60.6 ;
     RECT  7.649 61.632 7.808 62.76 ;
     RECT  7.585 64.08 7.808 65.448 ;
     RECT  7.225 66.672 7.808 67.32 ;
     RECT  7.808 1.968 7.912 108.012 ;
     RECT  7.912 1.968 8.104 107.742 ;
     RECT  8.104 63.792 8.524 65.448 ;
     RECT  8.104 1.968 8.675 60.6 ;
     RECT  8.675 1.968 8.777 58.728 ;
     RECT  8.524 64.368 8.813 65.448 ;
     RECT  8.675 59.808 9.097 60.6 ;
     RECT  8.104 61.584 9.097 62.52 ;
     RECT  9.097 59.808 9.205 62.52 ;
     RECT  8.104 66.672 9.493 68.088 ;
     RECT  8.777 2.208 9.677 58.728 ;
     RECT  9.493 66.672 9.749 68.136 ;
     RECT  9.749 66.672 9.788 66.792 ;
     RECT  9.205 59.808 9.817 63.24 ;
     RECT  8.813 64.368 9.817 65.112 ;
     RECT  9.788 66.096 9.875 66.792 ;
     RECT  9.677 2.256 10.067 58.728 ;
     RECT  10.067 2.304 10.109 58.728 ;
     RECT  10.109 56.352 10.213 58.728 ;
     RECT  9.817 59.808 10.213 65.112 ;
     RECT  10.213 56.352 10.289 65.112 ;
     RECT  10.109 2.304 10.577 55.32 ;
     RECT  10.289 64.848 10.789 65.112 ;
     RECT  9.875 66.672 10.829 66.792 ;
     RECT  10.289 63.744 10.865 63.816 ;
     RECT  9.749 67.824 11.041 68.136 ;
     RECT  10.289 56.352 11.045 62.52 ;
     RECT  10.577 30.624 11.077 55.32 ;
     RECT  11.045 56.352 11.077 59.304 ;
     RECT  10.829 66.768 11.293 66.792 ;
     RECT  11.041 67.824 11.293 68.424 ;
     RECT  10.789 64.848 11.581 65.544 ;
     RECT  11.293 66.768 11.725 68.424 ;
     RECT  11.077 30.624 11.765 59.304 ;
     RECT  11.765 56.88 11.945 59.304 ;
     RECT  11.581 64.032 11.981 65.544 ;
     RECT  11.945 57.024 12.037 59.304 ;
     RECT  11.045 60.336 12.037 62.52 ;
     RECT  11.725 66.768 12.161 68.472 ;
     RECT  10.577 2.304 12.661 29.592 ;
     RECT  12.037 57.024 12.913 62.52 ;
     RECT  12.913 57.024 13.093 62.664 ;
     RECT  11.981 64.032 13.093 65.496 ;
     RECT  12.661 2.256 13.208 29.592 ;
     RECT  11.765 30.624 13.208 55.848 ;
     RECT  13.093 57.024 13.208 65.688 ;
     RECT  12.161 66.768 13.208 67.32 ;
     RECT  12.161 68.448 13.208 68.472 ;
     RECT  13.208 2.148 13.312 108.012 ;
     RECT  13.312 2.256 13.504 107.742 ;
     RECT  13.504 2.256 13.933 40.584 ;
     RECT  13.933 2.304 14.033 40.584 ;
     RECT  14.033 2.304 14.285 40.392 ;
     RECT  13.504 64.176 14.285 65.784 ;
     RECT  13.504 66.768 14.357 67.32 ;
     RECT  13.504 41.616 14.387 45.576 ;
     RECT  13.504 56.928 14.393 62.808 ;
     RECT  14.393 56.928 14.465 58.776 ;
     RECT  13.504 47.808 14.501 55.224 ;
     RECT  14.387 42.096 14.533 45.576 ;
     RECT  14.465 56.928 14.605 58.152 ;
     RECT  14.501 48.096 14.609 55.224 ;
     RECT  14.393 59.76 14.713 62.808 ;
     RECT  14.285 64.32 14.717 65.784 ;
     RECT  14.533 42.096 14.749 46.536 ;
     RECT  14.357 67.296 14.753 67.32 ;
     RECT  14.285 2.352 14.861 40.392 ;
     RECT  14.749 42.096 14.861 46.68 ;
     RECT  14.861 26.352 14.897 40.392 ;
     RECT  14.897 36.624 14.933 40.392 ;
     RECT  14.717 64.368 14.969 65.784 ;
     RECT  14.933 36.624 15.005 40.344 ;
     RECT  14.861 42.096 15.005 45.576 ;
     RECT  14.609 48.096 15.011 51.912 ;
     RECT  14.609 53.472 15.037 55.224 ;
     RECT  14.605 56.784 15.037 58.152 ;
     RECT  15.011 48.096 15.041 48.792 ;
     RECT  15.005 42.096 15.509 44.856 ;
     RECT  14.861 46.56 15.545 46.68 ;
     RECT  15.037 53.472 15.577 58.152 ;
     RECT  15.509 42.096 15.649 43.848 ;
     RECT  15.433 67.584 15.649 67.608 ;
     RECT  14.713 59.76 15.653 63.288 ;
     RECT  15.011 50.832 15.685 51.912 ;
     RECT  15.685 50.832 15.725 51.96 ;
     RECT  14.969 64.464 15.865 65.784 ;
     RECT  15.653 59.76 15.869 62.52 ;
     RECT  15.041 48.096 15.901 48.504 ;
     RECT  15.577 53.472 15.941 58.392 ;
     RECT  14.897 26.352 15.973 35.448 ;
     RECT  15.005 36.624 15.973 39.624 ;
     RECT  15.941 55.152 15.973 58.392 ;
     RECT  15.869 59.76 15.973 59.784 ;
     RECT  15.725 50.832 15.977 50.856 ;
     RECT  15.865 64.464 15.977 66.024 ;
     RECT  15.869 60.768 16.013 62.52 ;
     RECT  15.649 41.904 16.067 43.848 ;
     RECT  15.973 26.352 16.081 39.624 ;
     RECT  16.081 26.352 16.085 40.2 ;
     RECT  15.973 55.152 16.085 59.784 ;
     RECT  16.085 55.824 16.121 59.784 ;
     RECT  15.941 53.472 16.189 53.928 ;
     RECT  16.189 53.04 16.193 53.928 ;
     RECT  15.649 67.584 16.225 67.992 ;
     RECT  16.085 39.792 16.297 40.2 ;
     RECT  16.193 53.04 16.355 53.784 ;
     RECT  16.067 41.904 16.405 43.8 ;
     RECT  15.011 49.824 16.405 49.848 ;
     RECT  16.225 67.584 16.409 68.376 ;
     RECT  15.901 47.616 16.549 48.504 ;
     RECT  16.405 49.824 16.549 50.76 ;
     RECT  16.121 56.352 16.625 59.784 ;
     RECT  15.545 46.56 16.693 46.584 ;
     RECT  14.861 2.352 16.765 25.32 ;
     RECT  16.085 26.352 16.765 38.712 ;
     RECT  16.549 47.616 16.877 50.76 ;
     RECT  15.977 64.8 16.909 66.024 ;
     RECT  16.625 58.08 16.981 59.784 ;
     RECT  16.877 48.096 17.021 50.76 ;
     RECT  16.981 58.08 17.021 60.312 ;
     RECT  16.117 63.792 17.057 63.816 ;
     RECT  16.297 39.792 17.089 40.632 ;
     RECT  16.405 41.616 17.089 43.8 ;
     RECT  17.089 39.792 17.093 43.8 ;
     RECT  17.093 40.464 17.129 43.8 ;
     RECT  16.693 45.84 17.153 46.632 ;
     RECT  16.765 2.352 17.161 38.712 ;
     RECT  17.161 2.304 17.164 38.712 ;
     RECT  15.509 44.832 17.173 44.856 ;
     RECT  17.153 45.84 17.173 46.776 ;
     RECT  17.173 44.832 17.237 46.776 ;
     RECT  17.164 2.304 17.267 31.128 ;
     RECT  15.725 51.888 17.269 51.96 ;
     RECT  16.355 53.04 17.269 53.064 ;
     RECT  16.013 61.728 17.305 62.52 ;
     RECT  17.125 54.912 17.341 54.936 ;
     RECT  16.625 56.352 17.341 56.808 ;
     RECT  17.129 40.464 17.345 43.56 ;
     RECT  17.021 48.096 17.363 48.504 ;
     RECT  17.021 58.08 17.404 59.256 ;
     RECT  17.345 41.616 17.411 43.56 ;
     RECT  17.267 2.304 17.413 30.36 ;
     RECT  16.909 64.8 17.593 66.84 ;
     RECT  17.341 54.912 17.629 56.808 ;
     RECT  17.404 58.08 17.629 58.152 ;
     RECT  17.629 54.912 17.701 58.152 ;
     RECT  17.593 64.8 17.737 66.888 ;
     RECT  17.021 49.728 17.845 50.76 ;
     RECT  17.269 51.888 17.845 53.064 ;
     RECT  17.845 49.728 18.133 53.064 ;
     RECT  17.021 60.288 18.169 60.312 ;
     RECT  17.305 61.632 18.169 62.52 ;
     RECT  17.164 32.304 18.349 38.712 ;
     RECT  18.169 60.288 18.373 62.52 ;
     RECT  17.413 2.256 18.385 30.36 ;
     RECT  18.133 49.728 18.493 53.592 ;
     RECT  18.385 2.256 18.608 31.176 ;
     RECT  18.349 32.304 18.608 39.048 ;
     RECT  17.345 40.464 18.608 40.632 ;
     RECT  17.411 41.616 18.608 43.32 ;
     RECT  17.237 44.832 18.608 46.632 ;
     RECT  17.363 48.24 18.608 48.504 ;
     RECT  18.493 49.536 18.608 53.592 ;
     RECT  17.701 54.864 18.608 58.152 ;
     RECT  17.404 59.232 18.608 59.256 ;
     RECT  18.373 60.288 18.608 62.856 ;
     RECT  17.737 64.176 18.608 66.888 ;
     RECT  16.409 67.968 18.608 68.376 ;
     RECT  18.608 2.148 18.712 108.012 ;
     RECT  18.712 2.304 18.904 107.742 ;
     RECT  18.904 50.928 18.965 59.112 ;
     RECT  18.904 40.608 19.037 43.128 ;
     RECT  18.965 50.928 19.043 56.376 ;
     RECT  18.965 57.936 19.043 57.96 ;
     RECT  18.904 61.2 19.073 61.224 ;
     RECT  19.043 51.408 19.109 56.376 ;
     RECT  18.904 46.272 19.181 48.36 ;
     RECT  18.904 45.024 19.235 45.048 ;
     RECT  19.181 47.328 19.235 48.36 ;
     RECT  18.904 63.648 19.289 65.688 ;
     RECT  19.181 46.272 19.397 46.296 ;
     RECT  18.904 2.304 19.541 35.592 ;
     RECT  18.904 62.496 19.619 62.664 ;
     RECT  19.541 2.496 19.715 35.592 ;
     RECT  19.037 43.104 19.721 43.128 ;
     RECT  19.235 47.328 19.829 47.832 ;
     RECT  18.904 49.536 19.897 49.848 ;
     RECT  18.904 36.624 19.933 39.432 ;
     RECT  19.037 40.608 19.933 42.072 ;
     RECT  18.965 59.088 19.933 59.112 ;
     RECT  19.109 51.408 19.973 56.328 ;
     RECT  19.289 63.792 20.009 65.688 ;
     RECT  19.973 53.808 20.045 56.328 ;
     RECT  19.933 36.624 20.077 42.072 ;
     RECT  19.969 44.688 20.077 44.712 ;
     RECT  18.904 66.816 20.113 66.936 ;
     RECT  19.897 49.488 20.149 49.848 ;
     RECT  20.077 44.448 20.257 44.712 ;
     RECT  20.149 49.488 20.329 50.376 ;
     RECT  19.973 51.408 20.329 52.776 ;
     RECT  19.933 59.088 20.329 59.832 ;
     RECT  20.077 36.624 20.333 42.888 ;
     RECT  20.149 57.648 20.401 57.672 ;
     RECT  20.329 59.088 20.401 60.072 ;
     RECT  20.333 36.624 20.441 42.792 ;
     RECT  20.329 49.488 20.441 52.776 ;
     RECT  20.113 66.816 20.483 67.848 ;
     RECT  20.401 57.648 20.513 60.408 ;
     RECT  20.441 49.488 20.531 51.96 ;
     RECT  20.045 54.624 20.545 56.328 ;
     RECT  19.715 2.496 20.621 30.072 ;
     RECT  20.483 66.912 20.657 67.848 ;
     RECT  19.829 47.808 20.693 47.832 ;
     RECT  20.009 64.848 20.765 65.688 ;
     RECT  20.257 43.92 20.771 44.808 ;
     RECT  20.441 36.624 20.801 42.312 ;
     RECT  20.531 51.888 20.801 51.96 ;
     RECT  20.009 63.792 20.837 63.816 ;
     RECT  20.473 46.272 20.869 46.296 ;
     RECT  20.869 46.272 20.953 46.776 ;
     RECT  20.657 66.912 20.981 66.936 ;
     RECT  19.715 31.152 21.013 35.592 ;
     RECT  20.801 36.624 21.013 42.168 ;
     RECT  20.545 54.624 21.013 56.52 ;
     RECT  20.621 6.96 21.049 30.072 ;
     RECT  21.013 31.152 21.049 42.168 ;
     RECT  21.013 54.144 21.061 56.52 ;
     RECT  21.061 53.28 21.107 56.52 ;
     RECT  21.049 6.96 21.161 42.168 ;
     RECT  19.619 62.64 21.197 62.664 ;
     RECT  20.771 44.784 21.229 44.808 ;
     RECT  21.107 54.624 21.229 56.52 ;
     RECT  20.513 57.648 21.229 58.008 ;
     RECT  21.229 44.784 21.233 45.048 ;
     RECT  21.085 63.936 21.233 63.96 ;
     RECT  21.233 45.024 21.313 45.048 ;
     RECT  20.953 46.272 21.337 46.728 ;
     RECT  21.337 45.696 21.341 46.728 ;
     RECT  20.531 49.488 21.397 50.856 ;
     RECT  21.229 54.624 21.443 58.008 ;
     RECT  21.341 45.696 21.449 46.344 ;
     RECT  21.397 49.056 21.539 50.856 ;
     RECT  20.513 59.088 21.548 60.408 ;
     RECT  21.265 61.632 21.548 61.656 ;
     RECT  20.621 2.496 21.553 5.88 ;
     RECT  20.801 51.936 21.553 51.96 ;
     RECT  20.765 65.232 21.557 65.688 ;
     RECT  21.449 45.696 21.593 46.056 ;
     RECT  21.443 54.624 21.593 56.52 ;
     RECT  21.548 59.088 21.593 61.656 ;
     RECT  21.593 55.968 21.629 56.52 ;
     RECT  21.593 59.28 21.635 61.656 ;
     RECT  21.593 45.696 21.665 45.72 ;
     RECT  21.553 51.936 21.665 52.248 ;
     RECT  21.443 57.792 21.665 58.008 ;
     RECT  21.557 65.472 21.665 65.688 ;
     RECT  21.635 61.632 21.697 61.656 ;
     RECT  21.665 57.984 21.701 58.008 ;
     RECT  21.539 49.056 21.733 50.616 ;
     RECT  21.593 54.624 21.737 54.648 ;
     RECT  21.733 48.576 21.769 50.616 ;
     RECT  21.665 65.664 21.773 65.688 ;
     RECT  21.107 53.28 21.779 53.304 ;
     RECT  21.161 26.208 21.817 42.168 ;
     RECT  21.553 2.304 21.877 5.88 ;
     RECT  21.161 6.96 21.877 25.176 ;
     RECT  21.769 48.432 21.877 50.616 ;
     RECT  21.817 26.208 21.881 42.072 ;
     RECT  21.665 52.224 21.881 52.248 ;
     RECT  21.877 48.336 21.953 50.616 ;
     RECT  21.697 61.632 21.953 62.136 ;
     RECT  21.953 48.336 21.971 49.56 ;
     RECT  21.635 59.28 22.019 60.552 ;
     RECT  21.953 50.592 22.025 50.616 ;
     RECT  21.971 48.432 22.061 49.56 ;
     RECT  22.019 59.28 22.067 60.408 ;
     RECT  21.685 88.752 22.117 88.776 ;
     RECT  21.881 26.208 22.163 41.4 ;
     RECT  22.067 60.384 22.163 60.408 ;
     RECT  21.953 62.112 22.241 62.136 ;
     RECT  22.163 41.376 22.355 41.4 ;
     RECT  22.163 26.208 22.396 40.008 ;
     RECT  21.877 2.304 22.489 25.176 ;
     RECT  22.396 26.208 22.489 39.288 ;
     RECT  22.061 48.432 22.595 48.648 ;
     RECT  22.595 48.432 22.643 48.6 ;
     RECT  22.489 2.304 22.673 39.288 ;
     RECT  22.643 48.576 22.691 48.6 ;
     RECT  21.629 55.968 23.027 56.184 ;
     RECT  22.067 59.28 23.171 59.304 ;
     RECT  22.673 2.544 23.315 39.288 ;
     RECT  23.315 2.544 24.008 38.712 ;
     RECT  22.117 88.752 24.008 88.92 ;
     RECT  24.008 2.148 24.112 38.712 ;
     RECT  24.008 88.752 24.112 108.012 ;
     RECT  24.112 88.752 24.304 107.742 ;
     RECT  24.112 2.418 24.419 38.712 ;
     RECT  24.419 2.418 24.515 38.184 ;
     RECT  24.515 2.418 25.081 37.896 ;
     RECT  25.081 2.304 25.56 37.896 ;
     RECT  23.027 55.968 25.56 55.992 ;
     RECT  25.56 2.304 26.273 86.67 ;
     RECT  26.273 2.304 26.597 6.936 ;
     RECT  26.273 7.92 27.241 86.67 ;
     RECT  26.597 2.304 27.565 6.312 ;
     RECT  27.241 7.872 27.565 86.67 ;
     RECT  27.565 2.304 28.037 86.67 ;
     RECT  28.037 7.056 28.073 86.67 ;
     RECT  28.037 2.304 28.433 5.16 ;
     RECT  28.433 2.304 29.408 5.064 ;
     RECT  28.073 7.92 29.408 86.67 ;
     RECT  24.304 88.752 29.408 88.92 ;
     RECT  29.408 2.148 29.512 86.67 ;
     RECT  29.408 88.752 29.512 108.012 ;
     RECT  29.512 2.418 29.704 86.67 ;
     RECT  29.512 88.752 29.704 107.742 ;
     RECT  29.704 7.92 30.485 86.67 ;
     RECT  29.704 2.592 30.697 5.064 ;
     RECT  30.697 2.592 30.805 5.688 ;
     RECT  30.805 2.592 31.925 6.072 ;
     RECT  31.925 2.592 32.105 5.784 ;
     RECT  30.805 7.2 32.749 7.224 ;
     RECT  32.749 7.2 32.789 7.752 ;
     RECT  32.789 7.728 33.577 7.752 ;
     RECT  30.485 8.736 33.577 86.67 ;
     RECT  32.105 2.592 33.685 5.064 ;
     RECT  33.577 7.728 34.009 86.67 ;
     RECT  33.685 2.592 34.357 5.112 ;
     RECT  34.357 2.256 34.808 5.112 ;
     RECT  33.901 6.24 34.808 6.264 ;
     RECT  34.009 7.392 34.808 86.67 ;
     RECT  29.704 88.752 34.808 88.92 ;
     RECT  34.808 2.148 34.912 86.67 ;
     RECT  34.808 88.752 34.912 108.012 ;
     RECT  34.912 88.752 35.104 107.742 ;
     RECT  34.912 2.256 35.5 86.67 ;
     RECT  35.5 2.784 36.029 86.67 ;
     RECT  36.029 2.784 36.505 5.16 ;
     RECT  36.029 6.24 37.571 86.67 ;
     RECT  37.571 6.816 37.865 86.67 ;
     RECT  36.505 2.784 40.208 5.064 ;
     RECT  37.865 7.152 40.208 86.67 ;
     RECT  35.104 88.752 40.208 88.92 ;
     RECT  40.208 2.148 40.312 86.67 ;
     RECT  40.208 88.752 40.312 108.012 ;
     RECT  40.312 2.418 40.504 86.67 ;
     RECT  40.312 88.752 40.504 107.742 ;
     RECT  40.504 2.784 40.601 5.064 ;
     RECT  40.601 3.312 43.261 5.064 ;
     RECT  43.261 3.312 43.441 5.112 ;
     RECT  43.441 3.312 43.877 5.208 ;
     RECT  43.877 3.888 45.457 5.208 ;
     RECT  45.457 3.888 45.608 5.304 ;
     RECT  40.504 7.152 45.608 86.67 ;
     RECT  40.504 88.752 45.608 88.92 ;
     RECT  45.608 2.148 45.712 86.67 ;
     RECT  45.608 88.752 45.712 108.012 ;
     RECT  45.712 2.418 45.904 86.67 ;
     RECT  45.712 88.752 45.904 107.742 ;
     RECT  45.904 6.336 46.253 86.67 ;
     RECT  45.904 4.128 46.469 5.304 ;
     RECT  46.469 4.128 46.793 5.064 ;
     RECT  46.253 6.336 46.901 9.576 ;
     RECT  46.793 4.128 47.833 4.968 ;
     RECT  46.901 6.336 47.833 9.48 ;
     RECT  47.833 4.128 47.905 9.48 ;
     RECT  46.253 10.608 47.945 86.67 ;
     RECT  47.905 3.936 48.083 9.48 ;
     RECT  48.083 4.608 48.089 9.48 ;
     RECT  48.089 4.656 48.265 9.48 ;
     RECT  48.265 4.656 49.025 9.72 ;
     RECT  49.025 4.752 49.385 9.72 ;
     RECT  49.385 4.944 49.523 9.72 ;
     RECT  47.945 10.8 50.101 86.67 ;
     RECT  50.101 10.752 50.389 86.67 ;
     RECT  49.523 5.04 51.008 9.72 ;
     RECT  50.389 10.704 51.008 86.67 ;
     RECT  45.904 88.752 51.008 88.92 ;
     RECT  51.008 2.148 51.112 86.67 ;
     RECT  51.008 88.752 51.112 108.012 ;
     RECT  51.112 2.418 51.304 86.67 ;
     RECT  51.112 88.752 51.304 107.742 ;
     RECT  51.304 5.04 52.801 9.624 ;
     RECT  51.304 10.896 52.801 86.67 ;
     RECT  52.801 5.04 53.273 86.67 ;
     RECT  53.273 10.464 54.029 86.67 ;
     RECT  53.273 5.04 54.673 9.384 ;
     RECT  54.029 11.28 54.677 86.67 ;
     RECT  54.673 5.04 56.408 10.056 ;
     RECT  54.677 11.904 56.408 86.67 ;
     RECT  51.304 88.752 56.408 88.92 ;
     RECT  56.408 2.148 56.512 86.67 ;
     RECT  56.408 88.752 56.512 108.012 ;
     RECT  56.512 2.418 56.704 86.67 ;
     RECT  56.512 88.752 56.704 107.742 ;
     RECT  56.704 5.04 56.909 10.488 ;
     RECT  56.704 12.192 57.805 86.67 ;
     RECT  56.909 5.04 57.877 9.384 ;
     RECT  56.909 10.464 57.877 10.488 ;
     RECT  57.877 5.04 58.021 10.488 ;
     RECT  57.805 11.952 58.349 86.67 ;
     RECT  58.349 12.048 58.457 86.67 ;
     RECT  58.021 5.04 58.961 10.728 ;
     RECT  58.961 9.072 59.029 10.728 ;
     RECT  59.029 9.072 59.641 10.872 ;
     RECT  59.641 9.072 60.145 11.208 ;
     RECT  58.457 12.192 60.145 86.67 ;
     RECT  60.145 9.072 60.371 86.67 ;
     RECT  58.961 5.04 61.808 7.896 ;
     RECT  60.371 9.36 61.808 86.67 ;
     RECT  56.704 88.752 61.808 88.92 ;
     RECT  61.808 2.148 61.912 86.67 ;
     RECT  61.808 88.752 61.912 108.012 ;
     RECT  61.912 2.418 62.104 86.67 ;
     RECT  61.912 88.752 62.104 107.742 ;
     RECT  62.104 5.04 67.208 7.896 ;
     RECT  62.104 9.36 67.208 10.344 ;
     RECT  62.104 13.008 67.208 86.67 ;
     RECT  62.104 88.752 67.208 88.92 ;
     RECT  67.208 2.148 67.312 86.67 ;
     RECT  67.208 88.752 67.312 108.012 ;
     RECT  67.312 2.418 67.504 86.67 ;
     RECT  67.312 88.752 67.504 107.742 ;
     RECT  67.504 13.44 68.924 86.67 ;
     RECT  68.924 13.008 69.011 86.67 ;
     RECT  67.504 5.04 72.608 7.896 ;
     RECT  67.504 9.36 72.608 10.344 ;
     RECT  69.011 13.44 72.608 86.67 ;
     RECT  67.504 88.752 72.608 88.92 ;
     RECT  72.608 2.148 72.712 86.67 ;
     RECT  72.608 88.752 72.712 108.012 ;
     RECT  72.712 2.418 72.904 86.67 ;
     RECT  72.712 88.752 72.904 107.742 ;
     RECT  72.904 9.36 73.217 10.344 ;
     RECT  72.904 13.44 76.529 86.67 ;
     RECT  76.529 13.44 77.533 17.784 ;
     RECT  76.529 18.768 77.533 86.67 ;
     RECT  72.904 6 78.008 7.896 ;
     RECT  73.217 9.36 78.008 9.384 ;
     RECT  77.533 13.44 78.008 86.67 ;
     RECT  72.904 88.752 78.008 88.92 ;
     RECT  78.008 2.148 78.112 86.67 ;
     RECT  78.008 88.752 78.112 108.012 ;
     RECT  78.112 2.418 78.304 86.67 ;
     RECT  78.112 88.752 78.304 107.742 ;
     RECT  78.304 13.44 80.741 86.67 ;
     RECT  78.304 6 83.408 7.896 ;
     RECT  78.304 9.36 83.408 9.384 ;
     RECT  80.741 13.44 83.408 17.64 ;
     RECT  80.741 18.768 83.408 86.67 ;
     RECT  78.304 88.752 83.408 88.92 ;
     RECT  83.408 2.148 83.512 86.67 ;
     RECT  83.408 88.752 83.512 108.012 ;
     RECT  83.512 2.418 83.704 86.67 ;
     RECT  83.512 88.752 83.704 107.742 ;
     RECT  83.704 6 88.808 7.896 ;
     RECT  83.704 9.36 88.808 9.384 ;
     RECT  83.704 13.44 88.808 17.64 ;
     RECT  83.704 18.768 88.808 86.67 ;
     RECT  83.704 88.752 88.808 88.92 ;
     RECT  88.808 2.148 88.912 86.67 ;
     RECT  88.808 88.752 88.912 108.012 ;
     RECT  88.912 2.418 89.104 86.67 ;
     RECT  88.912 88.752 89.104 107.742 ;
     RECT  89.104 6 94.208 7.896 ;
     RECT  89.104 9.36 94.208 9.384 ;
     RECT  89.104 13.44 94.208 17.64 ;
     RECT  89.104 18.768 94.208 86.67 ;
     RECT  89.104 88.752 94.208 88.92 ;
     RECT  94.208 2.148 94.312 86.67 ;
     RECT  94.208 88.752 94.312 108.012 ;
     RECT  94.312 2.418 94.504 86.67 ;
     RECT  94.312 88.752 94.504 107.742 ;
     RECT  94.504 6 99.608 7.896 ;
     RECT  94.504 9.36 99.608 9.384 ;
     RECT  94.504 13.44 99.608 17.64 ;
     RECT  94.504 18.768 99.608 86.67 ;
     RECT  94.504 88.752 99.608 88.92 ;
     RECT  99.608 2.148 99.712 86.67 ;
     RECT  99.608 88.752 99.712 108.012 ;
     RECT  99.712 2.418 99.904 86.67 ;
     RECT  99.712 88.752 99.904 107.742 ;
     RECT  99.904 13.44 102.481 17.496 ;
     RECT  99.904 18.768 102.481 86.67 ;
     RECT  102.481 13.44 102.593 86.67 ;
     RECT  102.593 18.768 103.777 86.67 ;
     RECT  102.593 13.44 104.533 17.496 ;
     RECT  103.777 18.672 104.533 86.67 ;
     RECT  99.904 6 105.008 7.896 ;
     RECT  99.904 9.36 105.008 9.384 ;
     RECT  104.533 13.44 105.008 86.67 ;
     RECT  99.904 88.752 105.008 88.92 ;
     RECT  105.008 2.148 105.112 86.67 ;
     RECT  105.008 88.752 105.112 108.012 ;
     RECT  105.112 2.418 105.304 86.67 ;
     RECT  105.112 88.752 105.304 107.742 ;
     RECT  105.304 6 110.408 7.896 ;
     RECT  105.304 9.36 110.408 9.384 ;
     RECT  105.304 13.44 110.408 86.67 ;
     RECT  105.304 88.752 110.408 88.92 ;
     RECT  110.408 2.148 110.512 86.67 ;
     RECT  110.408 88.752 110.512 108.012 ;
     RECT  110.512 2.418 110.704 86.67 ;
     RECT  110.512 88.752 110.704 107.742 ;
     RECT  110.704 6 115.808 7.896 ;
     RECT  110.704 9.36 115.808 9.384 ;
     RECT  110.704 13.44 115.808 86.67 ;
     RECT  110.704 88.752 115.808 88.92 ;
     RECT  115.808 2.148 115.912 86.67 ;
     RECT  115.808 88.752 115.912 108.012 ;
     RECT  115.912 2.418 116.104 86.67 ;
     RECT  115.912 88.752 116.104 107.742 ;
     RECT  116.104 13.44 117.893 86.67 ;
     RECT  117.893 13.44 118.901 17.496 ;
     RECT  116.104 6 121.208 7.896 ;
     RECT  116.104 9.36 121.208 9.384 ;
     RECT  118.901 13.44 121.208 16.536 ;
     RECT  117.893 18.768 121.208 86.67 ;
     RECT  116.104 88.752 121.208 88.92 ;
     RECT  121.208 2.148 121.312 86.67 ;
     RECT  121.208 88.752 121.312 108.012 ;
     RECT  121.312 2.418 121.504 86.67 ;
     RECT  121.312 88.752 121.504 107.742 ;
     RECT  121.504 18.768 123.329 86.67 ;
     RECT  121.504 88.752 123.829 88.92 ;
     RECT  121.504 6 126.608 7.896 ;
     RECT  121.504 9.36 126.608 9.384 ;
     RECT  121.504 13.44 126.608 16.344 ;
     RECT  123.329 19.056 126.608 86.67 ;
     RECT  123.829 88.704 126.608 88.92 ;
     RECT  126.608 2.148 126.712 86.67 ;
     RECT  126.608 88.704 126.712 108.012 ;
     RECT  126.712 2.418 126.904 86.67 ;
     RECT  126.712 88.704 126.904 107.742 ;
     RECT  126.904 13.44 128.297 14.712 ;
     RECT  126.904 88.704 128.513 88.92 ;
     RECT  126.904 6 132.008 7.896 ;
     RECT  126.904 9.36 132.008 9.384 ;
     RECT  128.297 13.44 132.008 13.992 ;
     RECT  126.904 15.696 132.008 16.344 ;
     RECT  126.904 19.056 132.008 86.67 ;
     RECT  128.513 88.704 132.008 88.776 ;
     RECT  132.008 2.148 132.112 86.67 ;
     RECT  132.008 88.704 132.112 108.012 ;
     RECT  132.112 2.418 132.304 86.67 ;
     RECT  132.112 88.704 132.304 107.742 ;
     RECT  132.304 6 134.521 7.896 ;
     RECT  134.521 6 135.749 7.992 ;
     RECT  135.749 6 137.408 6.552 ;
     RECT  135.749 7.968 137.408 7.992 ;
     RECT  132.304 9.36 137.408 9.384 ;
     RECT  132.304 13.44 137.408 13.992 ;
     RECT  132.304 15.696 137.408 16.344 ;
     RECT  132.304 19.056 137.408 86.67 ;
     RECT  132.304 88.704 137.408 88.776 ;
     RECT  137.408 2.148 137.512 86.67 ;
     RECT  137.408 88.704 137.512 108.012 ;
     RECT  137.512 2.418 137.704 86.67 ;
     RECT  137.512 88.704 137.704 107.742 ;
     RECT  137.704 7.92 138.341 7.992 ;
     RECT  137.704 13.44 139.673 13.992 ;
     RECT  137.704 6 142.513 6.552 ;
     RECT  139.673 13.536 142.513 13.992 ;
     RECT  142.513 6 142.808 6.648 ;
     RECT  138.341 7.92 142.808 7.944 ;
     RECT  137.704 9.36 142.808 9.384 ;
     RECT  142.513 13.536 142.808 14.136 ;
     RECT  137.704 15.696 142.808 16.344 ;
     RECT  137.704 19.056 142.808 86.67 ;
     RECT  137.704 88.704 142.808 88.776 ;
     RECT  142.808 2.148 142.912 86.67 ;
     RECT  142.808 88.704 142.912 108.012 ;
     RECT  142.912 2.418 143.104 86.67 ;
     RECT  142.912 88.704 143.104 107.742 ;
     RECT  143.104 6 143.453 6.648 ;
     RECT  143.453 6.048 144.281 6.648 ;
     RECT  143.104 19.056 147.24 86.67 ;
     RECT  147.24 19.056 147.397 39.24 ;
     RECT  143.104 88.704 147.491 88.776 ;
     RECT  144.281 6.048 148.208 6.6 ;
     RECT  143.104 7.92 148.208 7.944 ;
     RECT  143.104 9.36 148.208 9.384 ;
     RECT  143.104 13.584 148.208 14.136 ;
     RECT  143.104 15.696 148.208 15.72 ;
     RECT  147.397 18.816 148.208 39.24 ;
     RECT  148.208 2.148 148.312 39.24 ;
     RECT  148.208 88.818 148.312 108.012 ;
     RECT  148.312 2.418 148.504 39.24 ;
     RECT  148.312 88.818 148.504 107.742 ;
     RECT  148.504 20.64 148.817 39.24 ;
     RECT  148.504 6.576 149.075 6.6 ;
     RECT  148.504 14.112 149.123 14.136 ;
     RECT  148.817 20.88 149.171 39.24 ;
     RECT  149.171 21.168 149.219 39.24 ;
     RECT  149.219 21.648 149.315 39.24 ;
     RECT  147.24 44.304 149.497 44.328 ;
     RECT  149.497 44.304 149.581 44.472 ;
     RECT  147.24 46.224 149.753 46.776 ;
     RECT  149.581 44.304 149.825 44.328 ;
     RECT  148.504 9.36 150.179 9.384 ;
     RECT  148.504 19.056 150.467 19.272 ;
     RECT  150.467 19.056 150.469 19.08 ;
     RECT  147.24 56.736 150.545 56.76 ;
     RECT  150.469 18.816 150.833 19.08 ;
     RECT  149.315 21.888 150.844 39.24 ;
     RECT  150.844 25.392 150.869 39.24 ;
     RECT  149.509 51.312 150.869 51.336 ;
     RECT  147.24 52.992 151.013 53.016 ;
     RECT  150.869 25.392 151.049 36.552 ;
     RECT  150.869 37.584 151.085 39.24 ;
     RECT  150.844 21.888 151.427 24.312 ;
     RECT  151.427 21.888 151.517 23.304 ;
     RECT  151.517 21.984 151.523 22.776 ;
     RECT  150.833 19.056 151.715 19.08 ;
     RECT  151.427 24.288 151.733 24.312 ;
     RECT  151.049 25.632 151.769 36.552 ;
     RECT  151.769 26.208 151.811 36.552 ;
     RECT  151.811 26.448 151.949 36.552 ;
     RECT  151.085 38.448 151.985 39.24 ;
     RECT  151.949 33.312 152.273 36.552 ;
     RECT  151.949 26.448 152.309 31.896 ;
     RECT  152.309 27.264 153.025 31.896 ;
     RECT  151.523 21.984 153.608 22.008 ;
     RECT  153.025 27.264 153.608 31.944 ;
     RECT  152.273 33.312 153.608 35.88 ;
     RECT  151.985 38.448 153.608 38.472 ;
     RECT  147.24 41.088 153.608 41.112 ;
     RECT  149.753 46.224 153.608 46.248 ;
     RECT  153.608 2.148 153.712 108.012 ;
     RECT  153.712 2.418 153.904 107.742 ;
     RECT  153.904 33.312 153.965 35.832 ;
     RECT  153.904 28.272 154.073 28.824 ;
     RECT  153.904 21.984 154.109 22.008 ;
     RECT  153.965 33.312 154.109 35.736 ;
     RECT  154.073 28.8 154.253 28.824 ;
     RECT  154.109 33.312 154.433 35.016 ;
     RECT  154.433 33.888 154.757 35.016 ;
     RECT  154.757 33.888 155.153 34.92 ;
     RECT  155.153 34.704 155.693 34.92 ;
     RECT  155.693 34.704 155.837 34.728 ;
     RECT  153.904 38.448 159.008 38.472 ;
     RECT  153.904 41.088 159.008 41.112 ;
     RECT  159.008 2.148 159.112 108.012 ;
     RECT  159.112 2.418 159.304 107.742 ;
     RECT  159.304 38.448 164.408 38.472 ;
     RECT  164.408 2.148 164.512 108.012 ;
     RECT  164.512 2.418 164.704 107.742 ;
     RECT  164.704 38.448 169.808 38.472 ;
     RECT  169.808 2.148 169.912 108.012 ;
     RECT  169.912 2.418 170.104 107.742 ;
    LAYER M5 ;
     RECT  2.4 2.137 2.52 2.151 ;
     RECT  7.8 2.137 7.92 2.151 ;
     RECT  13.2 2.137 13.32 2.151 ;
     RECT  18.6 2.137 18.72 2.151 ;
     RECT  24 2.137 24.12 2.151 ;
     RECT  29.4 2.137 29.52 2.151 ;
     RECT  34.8 2.137 34.92 2.151 ;
     RECT  40.2 2.137 40.32 2.151 ;
     RECT  45.6 2.137 45.72 2.151 ;
     RECT  51 2.137 51.12 2.151 ;
     RECT  56.4 2.137 56.52 2.151 ;
     RECT  61.8 2.137 61.92 2.151 ;
     RECT  67.2 2.137 67.32 2.151 ;
     RECT  72.6 2.137 72.72 2.151 ;
     RECT  78 2.137 78.12 2.151 ;
     RECT  83.4 2.137 83.52 2.151 ;
     RECT  88.8 2.137 88.92 2.151 ;
     RECT  94.2 2.137 94.32 2.151 ;
     RECT  99.6 2.137 99.72 2.151 ;
     RECT  105 2.137 105.12 2.151 ;
     RECT  110.4 2.137 110.52 2.151 ;
     RECT  115.8 2.137 115.92 2.151 ;
     RECT  121.2 2.137 121.32 2.151 ;
     RECT  126.6 2.137 126.72 2.151 ;
     RECT  132 2.137 132.12 2.151 ;
     RECT  137.4 2.137 137.52 2.151 ;
     RECT  142.8 2.137 142.92 2.151 ;
     RECT  148.2 2.137 148.32 2.151 ;
     RECT  153.6 2.137 153.72 2.151 ;
     RECT  159 2.137 159.12 2.151 ;
     RECT  164.4 2.137 164.52 2.151 ;
     RECT  169.8 2.137 169.92 2.151 ;
     RECT  0.288 1.957 0.312 2.245 ;
     RECT  7.8 2.151 8.112 2.245 ;
     RECT  9.168 2.197 9.192 2.245 ;
     RECT  13.2 2.151 13.512 2.245 ;
     RECT  18.6 2.151 18.912 2.245 ;
     RECT  34.8 2.151 35.112 2.245 ;
     RECT  11.328 2.389 11.352 2.485 ;
     RECT  3.936 2.581 3.96 2.629 ;
     RECT  0.288 2.245 0.552 2.771 ;
     RECT  7.056 2.245 10.056 2.773 ;
     RECT  18.432 2.245 18.912 2.773 ;
     RECT  34.368 2.245 35.448 2.819 ;
     RECT  13.2 2.245 13.896 2.821 ;
     RECT  24 2.151 24.312 2.821 ;
     RECT  0.288 2.771 0.312 2.869 ;
     RECT  6.192 2.773 10.056 2.965 ;
     RECT  0.144 2.869 0.312 3.059 ;
     RECT  3.936 2.629 4.152 3.059 ;
     RECT  2.4 2.151 2.712 3.157 ;
     RECT  3.936 3.059 4.104 3.157 ;
     RECT  34.368 2.819 35.112 3.205 ;
     RECT  13.104 2.821 13.896 3.301 ;
     RECT  40.2 2.151 40.512 3.349 ;
     RECT  13.104 3.301 14.616 3.397 ;
     RECT  23.28 2.821 24.312 3.539 ;
     RECT  0.192 3.059 0.216 3.587 ;
     RECT  5.28 2.965 10.056 3.685 ;
     RECT  19.92 2.581 19.944 3.685 ;
     RECT  11.328 2.485 11.64 3.829 ;
     RECT  13.056 3.397 14.616 3.829 ;
     RECT  5.28 3.685 10.248 3.925 ;
     RECT  11.328 3.829 14.616 3.925 ;
     RECT  18.192 2.773 18.912 4.019 ;
     RECT  19.92 3.685 20.664 4.019 ;
     RECT  2.4 3.157 4.104 4.211 ;
     RECT  5.28 3.925 15.384 4.261 ;
     RECT  37.008 2.773 37.032 4.355 ;
     RECT  20.64 4.019 20.664 4.403 ;
     RECT  40.2 3.349 40.632 4.451 ;
     RECT  31.488 2.821 31.512 4.643 ;
     RECT  34.224 3.205 35.112 4.643 ;
     RECT  16.8 3.829 16.824 4.789 ;
     RECT  23.328 3.539 24.312 4.933 ;
     RECT  23.28 4.933 24.312 5.029 ;
     RECT  49.488 4.933 49.512 5.075 ;
     RECT  28.368 3.925 28.392 5.171 ;
     RECT  36.432 4.405 36.456 5.171 ;
     RECT  0.336 4.837 0.36 5.173 ;
     RECT  2.4 4.211 3.144 5.173 ;
     RECT  44.016 4.117 44.04 5.219 ;
     RECT  18.6 4.019 18.912 5.269 ;
     RECT  16.608 4.789 16.824 5.365 ;
     RECT  0.336 5.173 1.176 5.555 ;
     RECT  49.392 5.317 49.416 5.605 ;
     RECT  2.4 5.173 3.336 5.653 ;
     RECT  0.336 5.555 0.408 5.797 ;
     RECT  48.048 3.925 48.072 5.845 ;
     RECT  49.104 5.605 49.416 5.845 ;
     RECT  148.2 2.151 148.512 6.037 ;
     RECT  4.992 4.261 15.384 6.229 ;
     RECT  0.192 5.797 0.408 6.277 ;
     RECT  4.464 6.229 15.384 6.323 ;
     RECT  4.464 6.323 14.088 6.325 ;
     RECT  2.304 5.653 3.336 6.419 ;
     RECT  0.144 6.277 0.408 6.517 ;
     RECT  147.984 6.037 148.512 6.565 ;
     RECT  15.216 6.323 15.384 6.709 ;
     RECT  16.608 5.365 16.872 6.709 ;
     RECT  15.216 6.709 16.872 6.899 ;
     RECT  48.048 5.845 49.416 7.189 ;
     RECT  37.536 6.229 37.56 7.237 ;
     RECT  15.264 6.899 16.872 7.379 ;
     RECT  45.6 2.151 45.912 7.381 ;
     RECT  2.4 6.419 3.336 7.475 ;
     RECT  18.144 5.269 18.912 7.571 ;
     RECT  18.48 7.571 18.912 7.619 ;
     RECT  19.968 7.189 19.992 7.621 ;
     RECT  19.968 7.621 20.136 7.763 ;
     RECT  45.6 7.381 46.008 7.763 ;
     RECT  0.144 6.517 0.504 7.907 ;
     RECT  37.536 7.237 37.896 7.907 ;
     RECT  4.368 6.325 14.088 7.957 ;
     RECT  19.968 7.763 19.992 8.003 ;
     RECT  37.536 7.907 37.56 8.003 ;
     RECT  3.936 7.957 14.088 8.051 ;
     RECT  2.4 7.475 2.856 8.195 ;
     RECT  15.264 7.379 15.576 8.437 ;
     RECT  0.24 7.907 0.504 8.533 ;
     RECT  47.28 7.189 49.416 8.579 ;
     RECT  22.08 7.621 22.104 8.677 ;
     RECT  23.184 5.029 24.312 8.677 ;
     RECT  43.488 7.957 43.512 8.723 ;
     RECT  22.08 8.677 24.312 8.819 ;
     RECT  0.24 8.533 1.176 8.821 ;
     RECT  3.936 8.051 13.608 8.963 ;
     RECT  0.24 8.821 1.272 9.059 ;
     RECT  6.144 8.963 13.608 9.061 ;
     RECT  14.976 8.437 15.576 9.061 ;
     RECT  6.144 9.061 15.576 9.203 ;
     RECT  34.704 4.643 35.112 9.203 ;
     RECT  29.4 2.151 29.712 9.301 ;
     RECT  1.248 9.059 1.272 9.587 ;
     RECT  41.568 9.109 41.592 9.587 ;
     RECT  26.208 8.869 26.232 9.637 ;
     RECT  29.28 9.301 29.712 9.637 ;
     RECT  6.144 9.203 15 9.731 ;
     RECT  16.848 7.379 16.872 9.731 ;
     RECT  23.184 8.819 24.312 9.781 ;
     RECT  32.016 9.637 32.04 9.925 ;
     RECT  28.944 9.637 29.712 9.971 ;
     RECT  31.536 9.925 32.04 9.971 ;
     RECT  25.776 9.637 26.232 10.067 ;
     RECT  61.8 2.151 62.112 10.213 ;
     RECT  27.84 9.925 27.864 10.307 ;
     RECT  33.12 9.637 33.144 10.307 ;
     RECT  31.536 9.971 31.56 10.355 ;
     RECT  60.336 9.061 60.36 10.355 ;
     RECT  2.4 8.195 2.712 10.645 ;
     RECT  2.4 10.645 2.808 10.741 ;
     RECT  3.936 8.963 5.064 10.741 ;
     RECT  27.36 10.597 27.384 10.787 ;
     RECT  6.144 9.731 14.232 10.789 ;
     RECT  25.776 10.067 25.8 10.883 ;
     RECT  2.4 10.741 5.064 10.933 ;
     RECT  0.144 10.693 0.168 10.981 ;
     RECT  6.144 10.789 14.52 11.075 ;
     RECT  6.24 11.075 14.52 11.125 ;
     RECT  51 2.151 51.312 11.125 ;
     RECT  47.28 8.579 47.304 11.171 ;
     RECT  23.184 9.781 24.408 11.365 ;
     RECT  0.144 10.981 0.264 11.413 ;
     RECT  37.008 10.933 37.032 11.459 ;
     RECT  30.816 11.413 30.84 11.509 ;
     RECT  23.184 11.365 24.936 11.555 ;
     RECT  26.304 11.221 26.328 11.555 ;
     RECT  2.4 10.933 5.112 11.603 ;
     RECT  0.144 11.413 1.176 11.651 ;
     RECT  1.152 11.651 1.176 11.653 ;
     RECT  20.304 10.885 20.328 11.701 ;
     RECT  1.152 11.653 1.272 11.795 ;
     RECT  20.304 11.701 20.424 11.797 ;
     RECT  51 11.125 51.576 11.845 ;
     RECT  18.6 7.619 18.912 11.941 ;
     RECT  20.016 11.797 20.424 11.941 ;
     RECT  30.816 11.509 31.224 11.941 ;
     RECT  45.6 7.763 45.912 11.941 ;
     RECT  18.6 11.941 20.424 12.133 ;
     RECT  4.32 11.603 5.112 12.275 ;
     RECT  30.816 11.941 31.32 12.277 ;
     RECT  29.28 9.971 29.712 12.515 ;
     RECT  44.64 11.941 45.912 12.515 ;
     RECT  22.08 8.819 22.104 12.517 ;
     RECT  23.52 11.555 24.936 12.517 ;
     RECT  26.352 12.469 26.376 12.517 ;
     RECT  29.4 12.515 29.712 12.517 ;
     RECT  30.816 12.277 31.848 12.517 ;
     RECT  47.52 11.173 47.544 12.563 ;
     RECT  50.88 11.845 51.576 12.563 ;
     RECT  53.568 10.453 53.592 12.563 ;
     RECT  6.24 11.125 15.384 12.611 ;
     RECT  48.528 8.579 49.416 12.661 ;
     RECT  18.6 12.133 20.856 12.709 ;
     RECT  22.08 12.517 26.376 12.709 ;
     RECT  43.344 11.125 43.368 12.709 ;
     RECT  48.528 12.661 49.848 12.803 ;
     RECT  18.6 12.709 26.376 12.805 ;
     RECT  34.8 9.203 35.112 12.805 ;
     RECT  43.344 12.709 43.464 12.851 ;
     RECT  4.416 12.275 5.112 12.853 ;
     RECT  6.24 12.611 9.672 12.853 ;
     RECT  48.528 12.803 49.416 12.853 ;
     RECT  17.616 12.805 26.376 12.995 ;
     RECT  56.4 2.151 56.712 13.045 ;
     RECT  61.68 10.213 62.112 13.045 ;
     RECT  1.248 12.805 1.272 13.091 ;
     RECT  34.8 12.805 35.352 13.091 ;
     RECT  29.4 12.517 31.848 13.235 ;
     RECT  10.8 12.611 15.336 13.283 ;
     RECT  40.2 4.451 40.512 13.333 ;
     RECT  0.144 12.613 0.168 13.381 ;
     RECT  48.24 12.853 49.416 13.427 ;
     RECT  16.416 13.045 16.44 13.525 ;
     RECT  17.472 13.477 17.592 13.525 ;
     RECT  4.416 12.853 9.672 13.571 ;
     RECT  147.984 6.565 149.064 13.573 ;
     RECT  16.416 13.525 17.592 13.619 ;
     RECT  33.072 13.381 33.096 13.619 ;
     RECT  36.384 13.333 36.408 13.667 ;
     RECT  56.4 13.045 56.808 13.669 ;
     RECT  61.392 13.045 62.112 13.669 ;
     RECT  2.4 11.603 2.856 13.715 ;
     RECT  55.776 13.669 56.808 13.715 ;
     RECT  18.6 12.995 26.376 13.763 ;
     RECT  29.4 13.235 31.656 13.763 ;
     RECT  0.144 13.381 0.264 13.859 ;
     RECT  55.776 13.715 56.712 13.859 ;
     RECT  57.84 13.669 57.864 13.859 ;
     RECT  16.512 13.619 17.592 13.907 ;
     RECT  48.24 13.427 48.552 13.907 ;
     RECT  61.392 13.669 62.424 13.907 ;
     RECT  5.088 13.571 9.672 14.005 ;
     RECT  147.744 13.573 149.064 14.101 ;
     RECT  29.4 13.763 30.6 14.149 ;
     RECT  31.632 13.763 31.656 14.195 ;
     RECT  28.512 14.149 30.6 14.243 ;
     RECT  16.512 13.907 16.536 14.291 ;
     RECT  44.832 12.515 45.912 14.291 ;
     RECT  3.888 14.197 3.912 14.389 ;
     RECT  5.088 14.005 10.296 14.485 ;
     RECT  11.28 13.283 15.336 14.485 ;
     RECT  0.192 13.859 0.264 14.677 ;
     RECT  3.84 14.389 3.912 14.725 ;
     RECT  0.192 14.677 0.312 14.771 ;
     RECT  3.84 14.725 3.96 14.867 ;
     RECT  43.344 12.851 43.368 14.867 ;
     RECT  61.392 13.907 62.112 14.867 ;
     RECT  5.088 14.485 15.336 14.915 ;
     RECT  28.512 14.243 29.712 14.915 ;
     RECT  18.6 13.763 25.896 14.917 ;
     RECT  34.8 13.091 35.112 14.917 ;
     RECT  52.896 14.773 52.92 14.963 ;
     RECT  3.888 14.867 3.96 15.061 ;
     RECT  5.088 14.915 14.568 15.061 ;
     RECT  3.888 15.061 14.568 15.203 ;
     RECT  3.936 15.203 14.568 15.347 ;
     RECT  17.568 13.907 17.592 15.349 ;
     RECT  18.6 14.917 26.184 15.349 ;
     RECT  28.608 14.915 29.712 15.395 ;
     RECT  32.448 14.773 32.472 15.491 ;
     RECT  40.2 13.333 40.632 15.493 ;
     RECT  34.704 14.917 35.112 15.541 ;
     RECT  40.2 15.493 41.592 15.589 ;
     RECT  0.24 14.771 0.312 15.637 ;
     RECT  147.744 14.101 149.112 15.685 ;
     RECT  0.24 15.637 0.36 15.829 ;
     RECT  45.6 14.291 45.912 15.829 ;
     RECT  0.24 15.829 1.176 15.971 ;
     RECT  40.2 15.589 41.784 15.973 ;
     RECT  0.24 15.971 0.264 16.019 ;
     RECT  5.088 15.347 14.568 16.019 ;
     RECT  34.704 15.541 35.352 16.019 ;
     RECT  5.808 16.019 14.568 16.067 ;
     RECT  16.32 15.829 16.344 16.069 ;
     RECT  17.568 15.349 26.184 16.069 ;
     RECT  36.384 14.917 36.408 16.259 ;
     RECT  51 12.563 51.576 16.259 ;
     RECT  59.136 15.349 59.16 16.261 ;
     RECT  58.8 16.261 59.16 16.307 ;
     RECT  48.24 13.907 48.264 16.309 ;
     RECT  16.32 16.069 26.184 16.499 ;
     RECT  34.8 16.019 35.208 16.547 ;
     RECT  29.04 15.395 29.712 16.597 ;
     RECT  39.936 15.973 41.784 16.643 ;
     RECT  16.32 16.499 25.704 16.691 ;
     RECT  16.32 16.691 25.656 16.741 ;
     RECT  48.24 16.309 48.504 16.741 ;
     RECT  45.6 15.829 46.056 16.789 ;
     RECT  48.24 16.741 48.936 16.837 ;
     RECT  31.632 16.549 31.656 16.883 ;
     RECT  33.072 16.597 33.096 16.931 ;
     RECT  45.024 16.789 46.056 16.931 ;
     RECT  28.944 16.597 29.712 17.029 ;
     RECT  28.944 17.029 31.128 17.075 ;
     RECT  37.44 13.381 37.464 17.077 ;
     RECT  67.2 2.151 67.512 17.077 ;
     RECT  29.04 17.075 31.128 17.123 ;
     RECT  45.12 16.931 46.056 17.123 ;
     RECT  48.24 16.837 49.128 17.123 ;
     RECT  29.232 17.123 31.128 17.219 ;
     RECT  36.912 17.077 37.464 17.219 ;
     RECT  48.24 17.123 49.032 17.267 ;
     RECT  68.976 12.997 69 17.365 ;
     RECT  68.784 17.365 69 17.461 ;
     RECT  66.288 17.077 67.512 17.507 ;
     RECT  43.584 17.461 43.608 17.603 ;
     RECT  6.48 16.067 14.568 17.605 ;
     RECT  37.056 17.219 37.464 17.651 ;
     RECT  40.2 16.643 41.784 17.651 ;
     RECT  31.104 17.219 31.128 17.699 ;
     RECT  5.568 17.605 14.568 17.747 ;
     RECT  5.568 17.747 5.592 17.845 ;
     RECT  15.984 16.741 25.656 17.891 ;
     RECT  41.76 17.651 41.784 17.891 ;
     RECT  0.144 16.021 0.168 18.131 ;
     RECT  16.32 17.891 25.656 18.179 ;
     RECT  3.936 15.347 3.96 18.181 ;
     RECT  34.8 16.547 35.112 18.181 ;
     RECT  105 2.151 105.312 18.181 ;
     RECT  48.24 17.267 48.936 18.229 ;
     RECT  51 16.259 51.312 18.229 ;
     RECT  52.416 18.133 52.44 18.229 ;
     RECT  3.936 18.181 4.104 18.275 ;
     RECT  16.32 18.179 17.496 18.275 ;
     RECT  74.736 16.405 74.76 18.275 ;
     RECT  75.84 17.605 75.864 18.275 ;
     RECT  29.232 17.219 29.712 18.373 ;
     RECT  80.496 17.605 80.52 18.419 ;
     RECT  48.24 18.229 49.128 18.515 ;
     RECT  37.44 17.651 37.464 18.517 ;
     RECT  51 18.229 52.44 18.563 ;
     RECT  37.44 18.517 37.512 18.565 ;
     RECT  18.48 18.179 25.656 18.613 ;
     RECT  26.784 16.885 26.808 18.613 ;
     RECT  37.44 18.565 37.608 18.613 ;
     RECT  40.2 17.651 40.632 18.707 ;
     RECT  68.688 17.461 69 18.707 ;
     RECT  5.136 17.845 5.592 18.709 ;
     RECT  18.48 18.613 26.808 18.803 ;
     RECT  58.8 16.307 58.824 18.805 ;
     RECT  52.416 18.563 52.44 18.851 ;
     RECT  147.408 15.685 149.112 18.851 ;
     RECT  57.792 17.605 57.816 18.853 ;
     RECT  58.8 18.805 58.872 18.853 ;
     RECT  18.48 18.803 26.328 18.947 ;
     RECT  57.792 18.853 58.872 18.947 ;
     RECT  57.792 18.947 58.824 18.995 ;
     RECT  37.44 18.613 38.136 19.045 ;
     RECT  34.8 18.181 35.592 19.141 ;
     RECT  5.088 18.709 5.592 19.189 ;
     RECT  61.8 14.867 62.112 19.237 ;
     RECT  150.144 9.349 150.168 19.237 ;
     RECT  28.032 19.093 28.056 19.283 ;
     RECT  37.056 19.045 38.136 19.283 ;
     RECT  5.088 19.189 5.688 19.285 ;
     RECT  6.72 17.747 14.568 19.285 ;
     RECT  0.192 19.045 0.216 19.331 ;
     RECT  2.4 13.715 2.712 19.333 ;
     RECT  4.08 18.275 4.104 19.333 ;
     RECT  99.6 2.151 99.912 19.333 ;
     RECT  29.184 18.373 29.712 19.381 ;
     RECT  5.088 19.285 14.568 19.427 ;
     RECT  37.056 19.283 37.608 19.427 ;
     RECT  98.064 17.605 98.088 19.427 ;
     RECT  29.088 19.381 29.712 19.525 ;
     RECT  37.056 19.427 37.512 19.571 ;
     RECT  51 18.563 51.312 19.621 ;
     RECT  44.304 18.757 44.328 19.717 ;
     RECT  40.2 18.707 40.512 19.765 ;
     RECT  57.792 18.995 57.816 19.811 ;
     RECT  78 2.151 78.312 19.813 ;
     RECT  17.184 18.275 17.496 19.861 ;
     RECT  18.48 18.947 25.368 19.861 ;
     RECT  34.8 19.141 36.024 19.861 ;
     RECT  37.056 19.571 37.464 19.861 ;
     RECT  29.088 19.525 29.928 19.907 ;
     RECT  2.4 19.333 4.104 19.909 ;
     RECT  77.808 19.813 78.312 19.909 ;
     RECT  17.184 19.861 25.368 19.957 ;
     RECT  51 19.621 51.432 19.957 ;
     RECT  15.552 19.237 15.576 20.003 ;
     RECT  34.8 19.861 37.464 20.003 ;
     RECT  5.568 19.427 14.568 20.051 ;
     RECT  43.872 19.717 44.328 20.053 ;
     RECT  45.6 17.123 46.056 20.053 ;
     RECT  77.28 19.909 78.312 20.053 ;
     RECT  79.344 18.709 79.368 20.053 ;
     RECT  43.872 20.053 46.056 20.101 ;
     RECT  47.04 20.053 47.064 20.101 ;
     RECT  88.8 2.151 89.112 20.101 ;
     RECT  90.096 19.765 90.12 20.101 ;
     RECT  61.8 19.237 62.952 20.149 ;
     RECT  61.8 20.149 63.24 20.195 ;
     RECT  43.872 20.101 47.064 20.245 ;
     RECT  48.24 18.515 48.984 20.245 ;
     RECT  50.736 19.957 51.432 20.339 ;
     RECT  135.408 7.237 135.432 20.339 ;
     RECT  43.872 20.245 48.984 20.387 ;
     RECT  88.8 20.101 90.12 20.387 ;
     RECT  40.2 19.765 41.064 20.389 ;
     RECT  56.4 13.859 56.712 20.389 ;
     RECT  31.536 19.669 31.56 20.435 ;
     RECT  17.184 19.957 26.136 20.579 ;
     RECT  33.744 18.661 33.768 20.579 ;
     RECT  43.872 20.387 46.248 20.579 ;
     RECT  47.856 20.387 48.984 20.579 ;
     RECT  56.304 20.389 56.808 20.579 ;
     RECT  86.064 19.813 86.088 20.579 ;
     RECT  104.544 18.181 105.312 20.579 ;
     RECT  56.4 20.579 56.808 20.629 ;
     RECT  58.8 18.995 58.824 20.677 ;
     RECT  40.2 20.389 41.304 20.771 ;
     RECT  75.408 20.629 75.432 20.771 ;
     RECT  2.4 19.909 4.536 20.819 ;
     RECT  77.28 20.053 79.368 20.821 ;
     RECT  147.6 18.851 149.112 20.821 ;
     RECT  147.36 20.821 149.112 20.869 ;
     RECT  47.856 20.579 47.928 20.915 ;
     RECT  61.8 20.195 62.232 20.915 ;
     RECT  77.28 20.821 79.704 20.915 ;
     RECT  88.8 20.387 89.976 20.915 ;
     RECT  29.184 19.907 29.928 20.917 ;
     RECT  32.784 20.821 32.808 20.917 ;
     RECT  67.2 17.507 67.512 20.917 ;
     RECT  94.2 2.151 94.512 20.965 ;
     RECT  47.904 20.915 47.928 21.011 ;
     RECT  58.752 20.677 58.824 21.011 ;
     RECT  78 20.915 79.704 21.011 ;
     RECT  5.664 20.051 14.568 21.013 ;
     RECT  27.456 20.917 27.48 21.059 ;
     RECT  28.752 20.917 29.928 21.059 ;
     RECT  32.688 20.917 32.808 21.059 ;
     RECT  34.8 20.003 36.792 21.059 ;
     RECT  67.2 20.917 67.8 21.059 ;
     RECT  53.04 20.149 53.064 21.107 ;
     RECT  110.4 2.151 110.712 21.109 ;
     RECT  132 2.151 132.312 21.109 ;
     RECT  56.4 20.629 57.048 21.155 ;
     RECT  58.8 21.011 58.824 21.155 ;
     RECT  60.192 19.957 60.216 21.155 ;
     RECT  63.216 20.195 63.24 21.155 ;
     RECT  68.976 18.707 69 21.155 ;
     RECT  99.6 19.333 100.344 21.155 ;
     RECT  147.36 20.869 149.16 21.157 ;
     RECT  150.144 19.237 150.456 21.157 ;
     RECT  31.296 20.485 31.512 21.299 ;
     RECT  44.88 20.579 46.248 21.349 ;
     RECT  38.784 21.109 38.808 21.395 ;
     RECT  54.24 20.197 54.264 21.443 ;
     RECT  44.88 21.349 46.296 21.445 ;
     RECT  51 20.339 51.432 21.493 ;
     RECT  105 20.579 105.312 21.541 ;
     RECT  110.4 21.109 111.192 21.541 ;
     RECT  115.8 2.151 116.112 21.541 ;
     RECT  34.8 21.059 36.552 21.587 ;
     RECT  50.064 21.493 51.432 21.635 ;
     RECT  17.184 20.579 25.752 21.637 ;
     RECT  105 21.541 105.48 21.637 ;
     RECT  107.184 21.397 107.208 21.637 ;
     RECT  17.184 21.637 25.8 21.779 ;
     RECT  31.296 21.299 31.368 21.779 ;
     RECT  5.136 21.013 14.568 21.781 ;
     RECT  139.392 13.621 139.416 21.923 ;
     RECT  29.4 21.059 29.928 21.925 ;
     RECT  110.4 21.541 111.336 22.067 ;
     RECT  110.4 22.067 111.192 22.115 ;
     RECT  115.056 21.541 116.112 22.115 ;
     RECT  2.4 20.819 4.104 22.117 ;
     RECT  2.304 22.117 4.104 22.163 ;
     RECT  67.2 21.059 67.608 22.163 ;
     RECT  104.832 21.637 105.48 22.163 ;
     RECT  106.56 21.637 107.208 22.211 ;
     RECT  2.304 22.163 2.808 22.307 ;
     RECT  17.184 21.779 25.656 22.309 ;
     RECT  31.344 21.779 31.368 22.403 ;
     RECT  17.088 22.309 25.656 22.451 ;
     RECT  44.88 21.445 46.344 22.451 ;
     RECT  132 21.109 132.408 22.499 ;
     RECT  3.888 22.163 4.104 22.597 ;
     RECT  5.088 21.781 14.568 22.597 ;
     RECT  107.184 22.211 107.208 22.643 ;
     RECT  105 22.163 105.48 22.691 ;
     RECT  151.68 19.045 151.704 22.741 ;
     RECT  65.568 19.141 65.592 22.787 ;
     RECT  78 21.011 79.32 22.835 ;
     RECT  3.888 22.597 14.568 22.931 ;
     RECT  40.2 20.771 40.632 23.075 ;
     RECT  34.8 21.587 35.832 23.123 ;
     RECT  79.296 22.835 79.32 23.123 ;
     RECT  44.88 22.451 45.912 23.171 ;
     RECT  51 21.635 51.432 23.219 ;
     RECT  93.504 20.965 94.512 23.315 ;
     RECT  147.36 21.157 150.456 23.317 ;
     RECT  151.488 22.741 151.704 23.317 ;
     RECT  29.4 21.925 30.216 23.411 ;
     RECT  31.872 22.741 31.896 23.411 ;
     RECT  27.936 22.069 27.96 23.507 ;
     RECT  2.4 22.307 2.808 23.509 ;
     RECT  0.144 23.365 0.168 23.651 ;
     RECT  2.4 23.509 2.856 23.651 ;
     RECT  3.936 22.931 14.568 23.651 ;
     RECT  17.184 22.451 25.656 23.651 ;
     RECT  2.4 23.651 2.808 24.131 ;
     RECT  17.184 23.651 25.416 24.421 ;
     RECT  16.224 24.421 25.416 24.563 ;
     RECT  4.8 23.651 14.568 24.611 ;
     RECT  16.224 24.563 25.368 24.755 ;
     RECT  2.4 24.131 2.712 24.997 ;
     RECT  4.8 24.611 11.976 25.045 ;
     RECT  3.888 25.045 11.976 25.139 ;
     RECT  5.088 25.139 11.976 25.235 ;
     RECT  7.344 25.235 11.976 25.475 ;
     RECT  3.888 25.139 3.912 25.571 ;
     RECT  2.304 24.997 2.712 25.763 ;
     RECT  5.088 25.235 6.312 26.099 ;
     RECT  147.36 23.317 151.704 26.197 ;
     RECT  0.144 24.901 0.168 26.293 ;
     RECT  147.36 26.197 151.8 26.483 ;
     RECT  16.224 24.755 25.272 26.723 ;
     RECT  7.392 25.475 11.976 26.725 ;
     RECT  13.104 24.611 14.568 26.725 ;
     RECT  0.144 26.293 0.552 26.773 ;
     RECT  5.664 26.099 6.312 26.819 ;
     RECT  0.144 26.773 1.176 26.869 ;
     RECT  4.56 26.773 4.632 27.013 ;
     RECT  5.76 26.819 6.312 27.061 ;
     RECT  0.144 26.869 1.272 27.155 ;
     RECT  0.144 27.155 1.176 27.203 ;
     RECT  5.76 27.061 6.36 27.301 ;
     RECT  7.392 26.725 14.568 27.301 ;
     RECT  0.144 27.203 0.552 27.635 ;
     RECT  4.416 27.013 4.632 27.877 ;
     RECT  5.76 27.301 14.568 27.877 ;
     RECT  4.416 27.877 14.568 27.971 ;
     RECT  0.144 27.635 0.312 28.163 ;
     RECT  147.36 26.483 150.168 29.123 ;
     RECT  4.56 27.971 14.568 29.171 ;
     RECT  4.56 29.171 5.208 29.221 ;
     RECT  0.288 28.163 0.312 29.317 ;
     RECT  16.224 26.723 24.984 29.365 ;
     RECT  4.512 29.221 5.208 29.509 ;
     RECT  16.224 29.365 25.032 29.555 ;
     RECT  4.464 29.509 5.208 29.651 ;
     RECT  0.288 29.317 0.552 29.797 ;
     RECT  0.144 29.797 0.552 29.939 ;
     RECT  4.464 29.651 5.112 30.229 ;
     RECT  4.416 30.229 5.112 30.275 ;
     RECT  2.4 25.763 2.712 30.469 ;
     RECT  6.288 29.171 14.568 30.757 ;
     RECT  151.392 26.483 151.8 30.757 ;
     RECT  150.384 30.757 151.8 30.947 ;
     RECT  150.48 30.947 151.8 31.043 ;
     RECT  4.416 30.275 5.064 31.237 ;
     RECT  6.24 30.757 14.568 31.237 ;
     RECT  2.4 30.469 3.432 31.379 ;
     RECT  151.392 31.043 151.8 31.379 ;
     RECT  4.416 31.237 14.568 31.427 ;
     RECT  0.144 29.939 0.168 31.523 ;
     RECT  4.464 31.427 14.568 31.907 ;
     RECT  147.36 29.123 149.304 31.907 ;
     RECT  4.464 31.907 6.12 32.531 ;
     RECT  151.488 31.379 151.8 32.531 ;
     RECT  6.096 32.531 6.12 32.579 ;
     RECT  7.152 31.907 14.568 32.965 ;
     RECT  4.464 32.531 4.968 33.157 ;
     RECT  16.224 29.555 24.984 33.299 ;
     RECT  7.152 32.965 14.808 33.443 ;
     RECT  3.936 33.157 4.968 33.491 ;
     RECT  4.944 33.491 4.968 33.683 ;
     RECT  16.224 33.299 24.888 33.683 ;
     RECT  2.4 31.379 2.712 33.781 ;
     RECT  17.184 33.683 19.608 33.827 ;
     RECT  147.36 31.907 149.208 33.923 ;
     RECT  20.688 33.683 24.888 33.971 ;
     RECT  153.6 2.151 153.912 34.117 ;
     RECT  7.152 33.443 14.568 34.357 ;
     RECT  147.36 33.923 149.16 34.643 ;
     RECT  6.528 34.357 14.568 34.645 ;
     RECT  0.144 34.405 0.168 34.691 ;
     RECT  3.936 33.491 3.96 34.741 ;
     RECT  6.528 34.645 14.856 34.787 ;
     RECT  3.936 34.741 4.536 34.789 ;
     RECT  2.4 33.781 2.808 34.837 ;
     RECT  3.936 34.789 4.968 34.837 ;
     RECT  16.176 33.781 16.2 34.931 ;
     RECT  153.024 34.117 153.912 35.027 ;
     RECT  147.36 34.643 148.68 35.075 ;
     RECT  2.4 34.837 4.968 35.171 ;
     RECT  1.248 34.933 1.272 35.315 ;
     RECT  20.784 33.971 24.888 35.317 ;
     RECT  20.592 35.317 24.888 35.603 ;
     RECT  2.4 35.171 4.536 35.843 ;
     RECT  151.488 32.531 151.704 35.939 ;
     RECT  16.08 36.373 16.104 36.469 ;
     RECT  2.4 35.843 3.96 36.515 ;
     RECT  6.528 34.787 14.568 36.515 ;
     RECT  151.68 35.939 151.704 36.515 ;
     RECT  6.528 36.515 12.072 36.563 ;
     RECT  6.528 36.563 11.88 36.659 ;
     RECT  20.592 35.603 24.84 36.709 ;
     RECT  3.936 36.515 3.96 36.853 ;
     RECT  20.592 36.709 25.416 36.899 ;
     RECT  2.4 36.515 2.808 36.995 ;
     RECT  3.936 36.853 4.248 37.043 ;
     RECT  6.672 36.659 11.88 37.091 ;
     RECT  6.672 37.091 9.96 37.283 ;
     RECT  3.936 37.043 3.96 37.475 ;
     RECT  16.032 36.469 16.104 37.475 ;
     RECT  17.376 33.827 19.608 37.571 ;
     RECT  11.856 37.091 11.88 37.667 ;
     RECT  147.408 35.075 148.68 37.667 ;
     RECT  0.192 37.957 0.216 38.147 ;
     RECT  18.6 37.571 19.608 38.149 ;
     RECT  20.592 36.899 24.84 38.149 ;
     RECT  147.456 37.667 148.68 38.291 ;
     RECT  16.032 37.475 16.056 38.819 ;
     RECT  0.144 38.869 0.168 39.059 ;
     RECT  13.2 36.515 14.568 39.109 ;
     RECT  1.248 39.205 1.272 39.347 ;
     RECT  6.672 37.283 9.528 39.539 ;
     RECT  12.96 39.109 14.568 39.779 ;
     RECT  7.248 39.539 9.528 39.829 ;
     RECT  0.144 40.069 0.168 40.259 ;
     RECT  11.952 40.261 11.976 40.405 ;
     RECT  12.96 39.779 14.28 40.405 ;
     RECT  0.192 40.501 0.216 40.597 ;
     RECT  0.192 40.597 1.176 40.691 ;
     RECT  1.152 40.691 1.176 40.883 ;
     RECT  2.4 36.995 2.712 40.885 ;
     RECT  3.696 40.837 3.72 40.885 ;
     RECT  2.4 40.885 3.72 41.027 ;
     RECT  11.952 40.405 14.28 41.075 ;
     RECT  7.248 39.829 10.152 41.509 ;
     RECT  12.96 41.075 14.28 41.605 ;
     RECT  7.056 41.509 10.152 42.181 ;
     RECT  7.056 42.181 10.296 42.227 ;
     RECT  5.28 40.981 5.304 42.323 ;
     RECT  11.952 41.075 11.976 42.661 ;
     RECT  12.96 41.605 14.376 42.661 ;
     RECT  4.896 42.517 5.16 42.707 ;
     RECT  2.4 41.027 3.432 42.803 ;
     RECT  7.2 42.227 10.296 42.803 ;
     RECT  5.136 42.707 5.16 42.947 ;
     RECT  10.272 42.803 10.296 42.995 ;
     RECT  17.376 37.571 17.4 43.285 ;
     RECT  7.2 42.803 9.096 43.379 ;
     RECT  16.512 43.285 17.4 43.571 ;
     RECT  16.512 43.571 16.536 43.811 ;
     RECT  147.456 38.291 148.512 44.339 ;
     RECT  3.936 42.949 3.96 44.341 ;
     RECT  7.392 43.379 9.096 44.581 ;
     RECT  10.224 44.341 10.248 44.677 ;
     RECT  11.952 42.661 14.376 44.677 ;
     RECT  16.032 43.813 16.056 44.867 ;
     RECT  2.4 42.803 2.712 44.917 ;
     RECT  5.904 44.917 5.928 44.965 ;
     RECT  7.2 44.581 9.096 44.965 ;
     RECT  3.936 44.341 4.776 45.059 ;
     RECT  10.224 44.677 14.376 45.251 ;
     RECT  5.904 44.965 9.096 45.397 ;
     RECT  10.224 45.251 12.024 45.397 ;
     RECT  0.192 45.109 0.216 45.587 ;
     RECT  5.904 45.397 12.024 45.635 ;
     RECT  2.4 44.917 2.856 46.165 ;
     RECT  147.888 44.339 148.512 46.259 ;
     RECT  4.752 45.059 4.776 46.403 ;
     RECT  2.4 46.165 2.904 46.643 ;
     RECT  17.184 45.301 17.208 46.787 ;
     RECT  147.936 46.259 148.512 46.787 ;
     RECT  5.904 45.635 9.384 46.933 ;
     RECT  10.992 45.635 12.024 47.363 ;
     RECT  11.76 47.363 12.024 47.459 ;
     RECT  11.76 47.459 11.784 47.747 ;
     RECT  0.192 47.701 0.216 47.891 ;
     RECT  2.4 46.643 2.856 48.133 ;
     RECT  2.4 48.133 2.904 48.371 ;
     RECT  5.904 46.933 9.912 48.373 ;
     RECT  5.28 48.373 9.912 48.469 ;
     RECT  17.328 48.085 17.352 48.469 ;
     RECT  13.2 45.251 14.376 48.901 ;
     RECT  11.184 48.421 11.208 48.949 ;
     RECT  13.2 48.901 14.664 48.949 ;
     RECT  13.2 48.949 15 49.045 ;
     RECT  5.088 48.469 9.912 49.091 ;
     RECT  0.288 48.997 0.312 49.139 ;
     RECT  13.104 49.045 15 49.283 ;
     RECT  6.768 49.091 9.912 49.477 ;
     RECT  6.768 49.477 9.96 49.525 ;
     RECT  11.184 48.949 11.928 49.525 ;
     RECT  5.088 49.091 5.112 49.619 ;
     RECT  2.4 48.371 2.712 49.957 ;
     RECT  16.944 48.469 17.352 50.003 ;
     RECT  1.968 49.957 2.712 50.147 ;
     RECT  13.2 49.283 15 50.389 ;
     RECT  6.768 49.525 11.928 50.963 ;
     RECT  13.056 50.389 15 51.107 ;
     RECT  6.816 50.963 11.928 51.253 ;
     RECT  13.056 51.107 13.8 51.253 ;
     RECT  149.52 44.437 149.544 51.347 ;
     RECT  6.816 51.253 13.8 51.875 ;
     RECT  14.976 51.107 15 51.875 ;
     RECT  17.328 50.003 17.352 51.877 ;
     RECT  6.816 51.875 13.704 52.691 ;
     RECT  17.328 51.877 17.496 52.741 ;
     RECT  17.28 52.741 17.496 52.789 ;
     RECT  18.6 38.149 24.84 52.789 ;
     RECT  6.912 52.691 13.704 52.885 ;
     RECT  0.144 52.741 0.168 52.931 ;
     RECT  148.2 46.787 148.512 52.981 ;
     RECT  17.28 52.789 24.84 53.029 ;
     RECT  16.32 53.029 24.84 53.075 ;
     RECT  6.912 52.885 14.472 53.507 ;
     RECT  17.376 53.075 24.84 53.603 ;
     RECT  16.32 53.075 16.344 53.795 ;
     RECT  6.912 53.507 13.704 54.085 ;
     RECT  6.48 54.085 13.704 55.045 ;
     RECT  6.288 55.045 13.704 55.331 ;
     RECT  6.288 55.331 9.912 55.859 ;
     RECT  17.376 53.603 17.4 55.907 ;
     RECT  18.6 53.603 24.84 56.003 ;
     RECT  10.896 55.331 13.704 56.099 ;
     RECT  18.6 56.003 24.312 56.195 ;
     RECT  6.48 55.859 9.912 56.483 ;
     RECT  6.48 56.483 9.816 57.059 ;
     RECT  10.896 56.099 11.4 57.059 ;
     RECT  12.384 56.099 13.704 57.301 ;
     RECT  18.6 56.195 22.056 57.683 ;
     RECT  21.456 57.683 22.056 57.827 ;
     RECT  16.176 56.341 16.2 57.923 ;
     RECT  2.4 50.147 2.712 58.117 ;
     RECT  10.896 57.059 11.208 58.117 ;
     RECT  12.384 57.301 13.8 58.163 ;
     RECT  10.704 58.117 11.208 58.645 ;
     RECT  6.48 57.059 9.48 59.221 ;
     RECT  10.704 58.645 11.4 59.221 ;
     RECT  2.4 58.117 2.904 59.267 ;
     RECT  4.416 58.501 4.44 59.267 ;
     RECT  17.328 58.645 17.352 59.267 ;
     RECT  6.48 59.221 11.4 59.315 ;
     RECT  23.136 56.195 24.312 59.315 ;
     RECT  6.48 59.315 10.728 59.605 ;
     RECT  12.384 58.163 13.608 59.605 ;
     RECT  15.984 59.221 16.008 59.795 ;
     RECT  5.808 59.605 10.728 60.275 ;
     RECT  21.6 57.827 22.056 60.373 ;
     RECT  18.6 57.683 20.472 60.949 ;
     RECT  6.48 60.275 10.728 61.091 ;
     RECT  21.6 60.373 22.152 61.091 ;
     RECT  10.224 61.091 10.728 61.619 ;
     RECT  12.048 59.605 13.608 61.667 ;
     RECT  18.24 60.949 20.472 61.667 ;
     RECT  6.48 61.091 9.048 62.195 ;
     RECT  12.384 61.667 13.608 62.195 ;
     RECT  6.48 62.195 8.28 62.483 ;
     RECT  18.6 61.667 20.472 62.531 ;
     RECT  18.6 62.531 18.912 62.821 ;
     RECT  6.48 62.483 8.112 63.299 ;
     RECT  2.4 59.267 2.712 63.493 ;
     RECT  7.44 63.299 8.112 63.781 ;
     RECT  2.4 63.493 3.048 64.067 ;
     RECT  13.008 62.195 13.608 64.211 ;
     RECT  18.384 62.821 18.912 64.211 ;
     RECT  7.44 63.781 8.472 64.451 ;
     RECT  13.2 64.211 13.608 64.597 ;
     RECT  7.8 64.451 8.472 65.027 ;
     RECT  10.656 63.781 10.68 65.123 ;
     RECT  9.84 66.085 9.864 66.707 ;
     RECT  13.2 64.597 13.896 66.803 ;
     RECT  20.448 62.531 20.472 66.851 ;
     RECT  13.2 66.803 13.608 67.331 ;
     RECT  6.624 66.661 6.648 67.811 ;
     RECT  21.696 61.091 22.152 88.787 ;
     RECT  147.36 52.981 148.512 88.787 ;
     RECT  22.128 88.787 22.152 88.931 ;
     RECT  2.4 64.067 2.712 108.009 ;
     RECT  7.8 65.027 8.112 108.009 ;
     RECT  13.2 67.331 13.512 108.009 ;
     RECT  18.6 64.211 18.912 108.009 ;
     RECT  24 59.315 24.312 108.009 ;
     RECT  29.4 23.411 29.712 108.009 ;
     RECT  34.8 23.123 35.112 108.009 ;
     RECT  40.2 23.075 40.512 108.009 ;
     RECT  45.6 23.171 45.912 108.009 ;
     RECT  51 23.219 51.312 108.009 ;
     RECT  56.4 21.155 56.712 108.009 ;
     RECT  61.8 20.915 62.112 108.009 ;
     RECT  67.2 22.163 67.512 108.009 ;
     RECT  72.6 2.151 72.912 108.009 ;
     RECT  78 22.835 78.312 108.009 ;
     RECT  83.4 2.151 83.712 108.009 ;
     RECT  88.8 20.915 89.112 108.009 ;
     RECT  94.2 23.315 94.512 108.009 ;
     RECT  99.6 21.155 99.912 108.009 ;
     RECT  105 22.691 105.312 108.009 ;
     RECT  110.4 22.115 110.712 108.009 ;
     RECT  115.8 22.115 116.112 108.009 ;
     RECT  121.2 2.151 121.512 108.009 ;
     RECT  126.6 2.151 126.912 108.009 ;
     RECT  132 22.499 132.312 108.009 ;
     RECT  137.4 2.151 137.712 108.009 ;
     RECT  142.8 2.151 143.112 108.009 ;
     RECT  148.2 88.787 148.512 108.009 ;
     RECT  153.6 35.027 153.912 108.009 ;
     RECT  159 2.151 159.312 108.009 ;
     RECT  164.4 2.151 164.712 108.009 ;
     RECT  169.8 2.151 170.112 108.009 ;
     RECT  2.4 108.009 2.52 108.023 ;
     RECT  7.8 108.009 7.92 108.023 ;
     RECT  13.2 108.009 13.32 108.023 ;
     RECT  18.6 108.009 18.72 108.023 ;
     RECT  24 108.009 24.12 108.023 ;
     RECT  29.4 108.009 29.52 108.023 ;
     RECT  34.8 108.009 34.92 108.023 ;
     RECT  40.2 108.009 40.32 108.023 ;
     RECT  45.6 108.009 45.72 108.023 ;
     RECT  51 108.009 51.12 108.023 ;
     RECT  56.4 108.009 56.52 108.023 ;
     RECT  61.8 108.009 61.92 108.023 ;
     RECT  67.2 108.009 67.32 108.023 ;
     RECT  72.6 108.009 72.72 108.023 ;
     RECT  78 108.009 78.12 108.023 ;
     RECT  83.4 108.009 83.52 108.023 ;
     RECT  88.8 108.009 88.92 108.023 ;
     RECT  94.2 108.009 94.32 108.023 ;
     RECT  99.6 108.009 99.72 108.023 ;
     RECT  105 108.009 105.12 108.023 ;
     RECT  110.4 108.009 110.52 108.023 ;
     RECT  115.8 108.009 115.92 108.023 ;
     RECT  121.2 108.009 121.32 108.023 ;
     RECT  126.6 108.009 126.72 108.023 ;
     RECT  132 108.009 132.12 108.023 ;
     RECT  137.4 108.009 137.52 108.023 ;
     RECT  142.8 108.009 142.92 108.023 ;
     RECT  148.2 108.009 148.32 108.023 ;
     RECT  153.6 108.009 153.72 108.023 ;
     RECT  159 108.009 159.12 108.023 ;
     RECT  164.4 108.009 164.52 108.023 ;
     RECT  169.8 108.009 169.92 108.023 ;
  END
END ot_qwen_tile_romleaf
END LIBRARY
